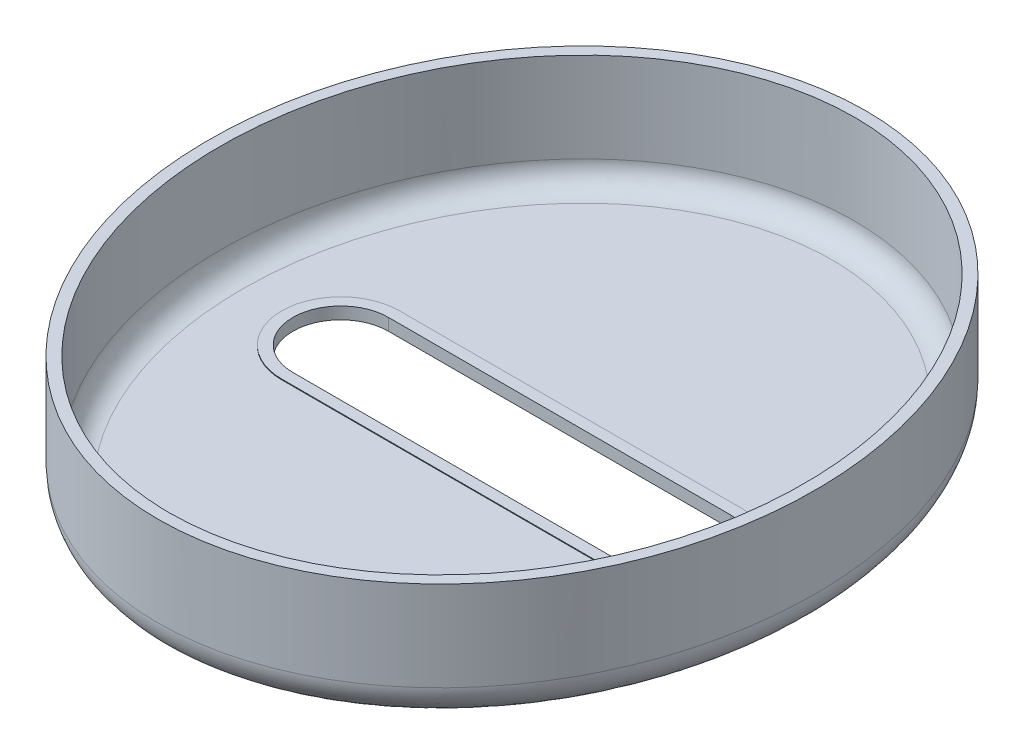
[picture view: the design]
ISO-10303-21;
HEADER;
FILE_DESCRIPTION(('STEP AP214'),'2;1');
FILE_NAME('part.step','',(''),(''),'','','');
FILE_SCHEMA(('AUTOMOTIVE_DESIGN { 1 0 10303 214 1 1 1 1 }'));
ENDSEC;
DATA;
#1=APPLICATION_CONTEXT('core data for automotive mechanical design processes');
#2=APPLICATION_PROTOCOL_DEFINITION('international standard','automotive_design',2000,#1);
#3=PRODUCT_CONTEXT('',#1,'mechanical');
#4=PRODUCT('Part','Part','',(#3));
#5=PRODUCT_RELATED_PRODUCT_CATEGORY('part','',(#4));
#6=PRODUCT_DEFINITION_FORMATION('','',#4);
#7=PRODUCT_DEFINITION_CONTEXT('part definition',#1,'design');
#8=PRODUCT_DEFINITION('design','',#6,#7);
#9=PRODUCT_DEFINITION_SHAPE('','',#8);
#10=(LENGTH_UNIT() NAMED_UNIT(*) SI_UNIT(.MILLI.,.METRE.));
#11=(NAMED_UNIT(*) PLANE_ANGLE_UNIT() SI_UNIT($,.RADIAN.));
#12=(NAMED_UNIT(*) SI_UNIT($,.STERADIAN.) SOLID_ANGLE_UNIT());
#13=UNCERTAINTY_MEASURE_WITH_UNIT(LENGTH_MEASURE(1.E-05),#10,'distance_accuracy_value','');
#14=(GEOMETRIC_REPRESENTATION_CONTEXT(3) GLOBAL_UNCERTAINTY_ASSIGNED_CONTEXT((#13)) GLOBAL_UNIT_ASSIGNED_CONTEXT((#10,
#11,#12)) REPRESENTATION_CONTEXT('',''));
#15=CARTESIAN_POINT('',(0.,0.,0.));
#16=DIRECTION('',(0.,0.,1.));
#17=DIRECTION('',(1.,0.,0.));
#18=AXIS2_PLACEMENT_3D('',#15,#16,#17);
#19=CARTESIAN_POINT('',(0.,11.,0.));
#20=DIRECTION('',(0.,1.,0.));
#21=DIRECTION('',(0.,0.,1.));
#22=AXIS2_PLACEMENT_3D('',#19,#20,#21);
#23=PLANE('',#22);
#24=CARTESIAN_POINT('',(0.,11.,0.));
#25=DIRECTION('',(0.,1.,0.));
#26=DIRECTION('',(0.,0.,-1.));
#27=AXIS2_PLACEMENT_3D('',#24,#25,#26);
#28=ELLIPSE('',#27,31.5,27.);
#29=CARTESIAN_POINT('',(0.,11.,-31.5));
#30=VERTEX_POINT('',#29);
#31=EDGE_CURVE('E205',#30,#30,#28,.T.);
#32=ORIENTED_EDGE('',*,*,#31,.T.);
#33=EDGE_LOOP('',(#32));
#34=FACE_BOUND('',#33,.T.);
#35=CARTESIAN_POINT('',(0.,11.,30.5));
#36=CARTESIAN_POINT('',(0.644223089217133,11.,30.499998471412));
#37=CARTESIAN_POINT('',(1.28846602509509,11.,30.4718512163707));
#38=CARTESIAN_POINT('',(2.57207033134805,11.,30.3596490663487));
#39=CARTESIAN_POINT('',(3.21143150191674,11.,30.2755918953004));
#40=CARTESIAN_POINT('',(4.48066001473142,11.,30.0526973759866));
#41=CARTESIAN_POINT('',(5.1105252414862,11.,29.9138480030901));
#42=CARTESIAN_POINT('',(6.35617141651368,11.,29.5832082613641));
#43=CARTESIAN_POINT('',(6.97195242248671,11.,29.3914181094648));
#44=CARTESIAN_POINT('',(8.18352809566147,11.,28.9579812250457));
#45=CARTESIAN_POINT('',(8.77937859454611,11.,28.7164902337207));
#46=CARTESIAN_POINT('',(9.94955938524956,11.,28.1861236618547));
#47=CARTESIAN_POINT('',(10.5238897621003,11.,27.8972482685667));
#48=CARTESIAN_POINT('',(11.6480725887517,11.,27.2752154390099));
#49=CARTESIAN_POINT('',(12.1979228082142,11.,26.9420539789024));
#50=CARTESIAN_POINT('',(13.2705915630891,11.,26.2347747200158));
#51=CARTESIAN_POINT('',(13.7934090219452,11.,25.8606552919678));
#52=CARTESIAN_POINT('',(14.8443375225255,11.,25.0482671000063));
#53=CARTESIAN_POINT('',(15.3704172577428,11.,24.6073714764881));
#54=CARTESIAN_POINT('',(16.3874753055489,11.,23.686844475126));
#55=CARTESIAN_POINT('',(16.8784523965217,11.,23.2072117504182));
#56=CARTESIAN_POINT('',(17.8239367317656,11.,22.2130919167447));
#57=CARTESIAN_POINT('',(18.2784346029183,11.,21.6985959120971));
#58=CARTESIAN_POINT('',(19.1498214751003,11.,20.6385796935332));
#59=CARTESIAN_POINT('',(19.566706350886,11.,20.0930560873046));
#60=CARTESIAN_POINT('',(20.190901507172,11.,19.2153396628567));
#61=CARTESIAN_POINT('',(20.4112281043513,11.,18.8923141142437));
#62=CARTESIAN_POINT('',(20.8392573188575,11.,18.2381042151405));
#63=CARTESIAN_POINT('',(21.0469625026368,11.,17.906921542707));
#64=CARTESIAN_POINT('',(21.6511362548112,11.,16.9018733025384));
#65=CARTESIAN_POINT('',(22.028665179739,11.,16.2165044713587));
#66=CARTESIAN_POINT('',(22.7327191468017,11.,14.8198249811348));
#67=CARTESIAN_POINT('',(23.0592226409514,11.,14.1085035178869));
#68=CARTESIAN_POINT('',(23.6608798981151,11.,12.664464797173));
#69=CARTESIAN_POINT('',(23.9360313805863,11.,11.9317465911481));
#70=CARTESIAN_POINT('',(24.4708720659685,11.,10.342021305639));
#71=CARTESIAN_POINT('',(24.7226069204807,11.,9.48233066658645));
#72=CARTESIAN_POINT('',(25.1587049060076,11.,7.74604003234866));
#73=CARTESIAN_POINT('',(25.3430623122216,11.,6.86943860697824));
#74=CARTESIAN_POINT('',(25.6445168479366,11.,5.10430928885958));
#75=CARTESIAN_POINT('',(25.7615871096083,11.,4.2157767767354));
#76=CARTESIAN_POINT('',(25.8866834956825,11.,2.87848787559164));
#77=CARTESIAN_POINT('',(25.9199644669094,11.,2.43195733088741));
#78=CARTESIAN_POINT('',(25.969713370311,11.,1.53785125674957));
#79=CARTESIAN_POINT('',(25.9861771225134,11.,1.09027549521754));
#80=CARTESIAN_POINT('',(26.0119135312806,11.,-0.341520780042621));
#81=CARTESIAN_POINT('',(25.9889619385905,11.,-1.32650344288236));
#82=CARTESIAN_POINT('',(25.8617095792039,11.,-3.29122285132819));
#83=CARTESIAN_POINT('',(25.7574073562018,11.,-4.27095950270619));
#84=CARTESIAN_POINT('',(25.5398768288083,11.,-5.7317745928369));
#85=CARTESIAN_POINT('',(25.4571177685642,11.,-6.21754243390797));
#86=CARTESIAN_POINT('',(25.271228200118,11.,-7.18503290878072));
#87=CARTESIAN_POINT('',(25.1681028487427,11.,-7.66675653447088));
#88=CARTESIAN_POINT('',(24.8282111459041,11.,-9.10429602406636));
#89=CARTESIAN_POINT('',(24.5608402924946,11.,-10.0530796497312));
#90=CARTESIAN_POINT('',(23.9420389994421,11.,-11.9313774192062));
#91=CARTESIAN_POINT('',(23.5899391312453,11.,-12.8606705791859));
#92=CARTESIAN_POINT('',(22.8029566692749,11.,-14.6837695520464));
#93=CARTESIAN_POINT('',(22.3680664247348,11.,-15.5775720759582));
#94=CARTESIAN_POINT('',(21.4167276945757,11.,-17.3192728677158));
#95=CARTESIAN_POINT('',(20.9003843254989,11.,-18.1672284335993));
#96=CARTESIAN_POINT('',(19.7870291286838,11.,-19.8083201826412));
#97=CARTESIAN_POINT('',(19.1900447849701,11.,-20.6014749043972));
#98=CARTESIAN_POINT('',(18.0791028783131,11.,-21.9292565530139));
#99=CARTESIAN_POINT('',(17.5824664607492,11.,-22.4784471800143));
#100=CARTESIAN_POINT('',(16.54696833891,11.,-23.5354446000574));
#101=CARTESIAN_POINT('',(16.0081136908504,11.,-24.0432582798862));
#102=CARTESIAN_POINT('',(14.890326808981,11.,-25.0123268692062));
#103=CARTESIAN_POINT('',(14.3114091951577,11.,-25.4735986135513));
#104=CARTESIAN_POINT('',(13.1159448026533,11.,-26.3446623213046));
#105=CARTESIAN_POINT('',(12.4993967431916,11.,-26.7544525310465));
#106=CARTESIAN_POINT('',(11.2280382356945,11.,-27.519856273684));
#107=CARTESIAN_POINT('',(10.5730069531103,11.,-27.8751039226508));
#108=CARTESIAN_POINT('',(9.23269544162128,11.,-28.5232263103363));
#109=CARTESIAN_POINT('',(8.54741484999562,11.,-28.8161003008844));
#110=CARTESIAN_POINT('',(7.15227044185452,11.,-29.3348060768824));
#111=CARTESIAN_POINT('',(6.44241915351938,11.,-29.5606714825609));
#112=CARTESIAN_POINT('',(5.00401481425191,11.,-29.9417582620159));
#113=CARTESIAN_POINT('',(4.27546419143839,11.,-30.0969887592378));
#114=CARTESIAN_POINT('',(2.88999504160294,11.,-30.3206349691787));
#115=CARTESIAN_POINT('',(2.23433463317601,11.,-30.3969060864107));
#116=CARTESIAN_POINT('',(0.918847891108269,11.,-30.4907361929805));
#117=CARTESIAN_POINT('',(0.259021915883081,11.,-30.5083001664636));
#118=CARTESIAN_POINT('',(-1.05934969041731,11.,-30.4844676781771));
#119=CARTESIAN_POINT('',(-1.717895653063,11.,-30.4430893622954));
#120=CARTESIAN_POINT('',(-3.02870017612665,11.,-30.3020075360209));
#121=CARTESIAN_POINT('',(-3.68095880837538,11.,-30.2023046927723));
#122=CARTESIAN_POINT('',(-4.94004583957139,11.,-29.9527667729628));
#123=CARTESIAN_POINT('',(-5.54745628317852,11.,-29.8058521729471));
#124=CARTESIAN_POINT('',(-6.7481607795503,11.,-29.4627882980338));
#125=CARTESIAN_POINT('',(-7.34145552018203,11.,-29.2666414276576));
#126=CARTESIAN_POINT('',(-8.51039797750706,11.,-28.8273863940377));
#127=CARTESIAN_POINT('',(-9.08604481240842,11.,-28.5842758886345));
#128=CARTESIAN_POINT('',(-10.2165331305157,11.,-28.053749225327));
#129=CARTESIAN_POINT('',(-10.7713736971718,11.,-27.7663311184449));
#130=CARTESIAN_POINT('',(-11.8839652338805,11.,-27.1351011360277));
#131=CARTESIAN_POINT('',(-12.4405451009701,11.,-26.7892262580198));
#132=CARTESIAN_POINT('',(-13.5252496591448,11.,-26.0554770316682));
#133=CARTESIAN_POINT('',(-14.0533737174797,11.,-25.6676017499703));
#134=CARTESIAN_POINT('',(-15.0792025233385,11.,-24.8533413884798));
#135=CARTESIAN_POINT('',(-15.5769002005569,11.,-24.4269474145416));
#136=CARTESIAN_POINT('',(-16.5401544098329,11.,-23.5392445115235));
#137=CARTESIAN_POINT('',(-17.0057070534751,11.,-23.0779313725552));
#138=CARTESIAN_POINT('',(-17.9570683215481,11.,-22.0668072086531));
#139=CARTESIAN_POINT('',(-18.4386430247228,11.,-21.5130098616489));
#140=CARTESIAN_POINT('',(-19.3586029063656,11.,-20.3706629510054));
#141=CARTESIAN_POINT('',(-19.7969851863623,11.,-19.7821110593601));
#142=CARTESIAN_POINT('',(-20.6298248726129,11.,-18.574440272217));
#143=CARTESIAN_POINT('',(-21.0242665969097,11.,-17.9553105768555));
#144=CARTESIAN_POINT('',(-21.7685015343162,11.,-16.6907670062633));
#145=CARTESIAN_POINT('',(-22.1182908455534,11.,-16.0453508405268));
#146=CARTESIAN_POINT('',(-22.8211831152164,11.,-14.6351444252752));
#147=CARTESIAN_POINT('',(-23.1671565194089,11.,-13.8667941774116));
#148=CARTESIAN_POINT('',(-23.7995656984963,11.,-12.3059750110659));
#149=CARTESIAN_POINT('',(-24.0859964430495,11.,-11.5135040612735));
#150=CARTESIAN_POINT('',(-24.5993301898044,11.,-9.90916573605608));
#151=CARTESIAN_POINT('',(-24.8262080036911,11.,-9.09729031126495));
#152=CARTESIAN_POINT('',(-25.2202914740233,11.,-7.45920121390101));
#153=CARTESIAN_POINT('',(-25.38749469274,11.,-6.63298695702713));
#154=CARTESIAN_POINT('',(-25.679695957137,11.,-4.86527590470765));
#155=CARTESIAN_POINT('',(-25.7966573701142,11.,-3.92244166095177));
#156=CARTESIAN_POINT('',(-25.9549412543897,11.,-2.03043896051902));
#157=CARTESIAN_POINT('',(-25.9962574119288,11.,-1.08126998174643));
#158=CARTESIAN_POINT('',(-26.0032573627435,11.,0.817856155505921));
#159=CARTESIAN_POINT('',(-25.9689100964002,11.,1.76781347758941));
#160=CARTESIAN_POINT('',(-25.860632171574,11.,3.18813072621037));
#161=CARTESIAN_POINT('',(-25.8150787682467,11.,3.66080802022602));
#162=CARTESIAN_POINT('',(-25.7050268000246,11.,4.60412450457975));
#163=CARTESIAN_POINT('',(-25.6405213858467,11.,5.07476289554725));
#164=CARTESIAN_POINT('',(-25.4104715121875,11.,6.53355258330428));
#165=CARTESIAN_POINT('',(-25.2122129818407,11.,7.51674329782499));
#166=CARTESIAN_POINT('',(-24.7312433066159,11.,9.46224155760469));
#167=CARTESIAN_POINT('',(-24.4485381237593,11.,10.4245505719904));
#168=CARTESIAN_POINT('',(-23.9611661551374,11.,11.8463902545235));
#169=CARTESIAN_POINT('',(-23.7880745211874,11.,12.3169167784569));
#170=CARTESIAN_POINT('',(-23.4208427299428,11.,13.2495371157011));
#171=CARTESIAN_POINT('',(-23.2267079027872,11.,13.7116330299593));
#172=CARTESIAN_POINT('',(-22.6126923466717,11.,15.0838170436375));
#173=CARTESIAN_POINT('',(-22.1611280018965,11.,15.9800139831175));
#174=CARTESIAN_POINT('',(-21.199602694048,11.,17.6806588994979));
#175=CARTESIAN_POINT('',(-20.6937843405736,11.,18.4874550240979));
#176=CARTESIAN_POINT('',(-19.6079406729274,11.,20.0497735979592));
#177=CARTESIAN_POINT('',(-19.0279107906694,11.,20.8052928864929));
#178=CARTESIAN_POINT('',(-17.7968313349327,11.,22.2539731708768));
#179=CARTESIAN_POINT('',(-17.1459049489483,11.,22.9472386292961));
#180=CARTESIAN_POINT('',(-15.7756219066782,11.,24.2623346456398));
#181=CARTESIAN_POINT('',(-15.0562940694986,11.,24.8841950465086));
#182=CARTESIAN_POINT('',(-13.7674275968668,11.,25.8809000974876));
#183=CARTESIAN_POINT('',(-13.2132808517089,11.,26.2757757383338));
#184=CARTESIAN_POINT('',(-12.0748825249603,11.,27.019418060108));
#185=CARTESIAN_POINT('',(-11.4906362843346,11.,27.3681928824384));
#186=CARTESIAN_POINT('',(-10.29555248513,11.,28.0154681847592));
#187=CARTESIAN_POINT('',(-9.68473840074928,11.,28.3140119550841));
#188=CARTESIAN_POINT('',(-8.43968412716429,11.,28.857535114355));
#189=CARTESIAN_POINT('',(-7.80544507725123,11.,29.1025171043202));
#190=CARTESIAN_POINT('',(-6.58580222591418,11.,29.5128105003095));
#191=CARTESIAN_POINT('',(-6.00230381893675,11.,29.6837998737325));
#192=CARTESIAN_POINT('',(-4.82348424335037,11.,29.9783949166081));
#193=CARTESIAN_POINT('',(-4.22816414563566,11.,30.1020048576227));
#194=CARTESIAN_POINT('',(-3.02944012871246,11.,30.3003877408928));
#195=CARTESIAN_POINT('',(-2.42603636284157,11.,30.3751616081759));
#196=CARTESIAN_POINT('',(-1.21509444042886,11.,30.4749699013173));
#197=CARTESIAN_POINT('',(-0.607556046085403,11.,30.5000014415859));
#198=CARTESIAN_POINT('',(0.,11.,30.5));
#199=B_SPLINE_CURVE_WITH_KNOTS('',3,(#35,#36,#37,#38,#39,#40,#41,#42,#43,#44,#45,#46,#47,#48,
#49,#50,#51,#52,#53,#54,#55,#56,#57,#58,#59,#60,#61,#62,#63,#64,#65,#66,#67,#68,#69,#70,#71,#72,
#73,#74,#75,#76,#77,#78,#79,#80,#81,#82,#83,#84,#85,#86,#87,#88,#89,#90,#91,#92,#93,#94,#95,#96,
#97,#98,#99,#100,#101,#102,#103,#104,#105,#106,#107,#108,#109,#110,#111,#112,#113,#114,#115,
#116,#117,#118,#119,#120,#121,#122,#123,#124,#125,#126,#127,#128,#129,#130,#131,#132,#133,#134,
#135,#136,#137,#138,#139,#140,#141,#142,#143,#144,#145,#146,#147,#148,#149,#150,#151,#152,#153,
#154,#155,#156,#157,#158,#159,#160,#161,#162,#163,#164,#165,#166,#167,#168,#169,#170,#171,#172,
#173,#174,#175,#176,#177,#178,#179,#180,#181,#182,#183,#184,#185,#186,#187,#188,#189,#190,#191,
#192,#193,#194,#195,#196,#197,#198),.UNSPECIFIED.,.T.,.F.,(4,2,2,2,2,2,2,2,2,2,2,2,2,2,2,2,2,2,
2,2,2,2,2,2,2,2,2,2,2,2,2,2,2,2,2,2,2,2,2,2,2,2,2,2,2,2,2,2,2,2,2,2,2,2,2,2,2,2,2,2,2,2,2,2,2,2,
2,2,2,2,2,2,2,2,2,2,2,2,2,2,2,4),(0.,1.93209281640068,3.86426429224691,5.79686003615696,
7.72944786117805,9.65606955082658,11.5826836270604,13.5094728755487,15.4363387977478,
17.4934609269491,19.55065461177,21.6083751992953,23.6663211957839,24.8390915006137,
26.011622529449,28.3566734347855,30.7027119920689,33.0488547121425,35.7333925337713,
38.4181583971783,41.1039955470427,42.4470291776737,43.7903965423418,46.7425554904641,
49.6947672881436,51.1726824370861,52.6502238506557,55.6034954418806,58.580914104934,
61.5586080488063,64.5324902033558,67.5053613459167,69.7245436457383,71.9433558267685,
74.1613625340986,76.3794447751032,78.6118111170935,80.8442042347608,83.0754753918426,
85.3064582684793,87.2841534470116,89.2616807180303,91.238599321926,93.2154953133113,
95.0881565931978,96.960726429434,98.8333896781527,100.706135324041,102.66997115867,
104.63385064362,106.598184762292,108.562756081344,110.762229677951,112.96185077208,
115.162254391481,117.36285015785,119.888214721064,122.413792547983,124.94043687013,
127.467184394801,130.314224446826,133.161502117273,136.009948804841,137.434220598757,
138.859007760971,141.864027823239,144.868835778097,146.372443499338,147.875671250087,
150.881455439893,153.734236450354,156.587193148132,159.435269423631,162.28215101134,
164.321466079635,166.360420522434,168.397608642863,170.434697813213,172.256915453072,
174.078968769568,175.900987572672,177.723112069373),.UNSPECIFIED.);
#200=CARTESIAN_POINT('',(0.,11.,30.5));
#201=VERTEX_POINT('',#200);
#202=EDGE_CURVE('E139',#201,#201,#199,.T.);
#203=ORIENTED_EDGE('',*,*,#202,.F.);
#204=EDGE_LOOP('',(#203));
#205=FACE_BOUND('',#204,.T.);
#206=ADVANCED_FACE('F50',(#34,#205),#23,.T.);
#207=CARTESIAN_POINT('',(0.,0.,0.));
#208=DIRECTION('',(0.,1.,0.));
#209=DIRECTION('',(0.,0.,1.));
#210=AXIS2_PLACEMENT_3D('',#207,#208,#209);
#211=PLANE('',#210);
#212=CARTESIAN_POINT('',(3.32786790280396,0.,-28.2237790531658));
#213=CARTESIAN_POINT('',(3.82146034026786,0.,-31.1828948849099));
#214=CARTESIAN_POINT('',(3.82146034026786,3.,-31.1828948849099));
#215=CARTESIAN_POINT('',(2.73134909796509,0.,-28.3232849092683));
#216=CARTESIAN_POINT('',(3.13719519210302,0.,-31.297038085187));
#217=CARTESIAN_POINT('',(3.13719519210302,3.,-31.297038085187));
#218=CARTESIAN_POINT('',(2.13043339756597,0.,-28.3962141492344));
#219=CARTESIAN_POINT('',(2.44729713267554,0.,-31.3807861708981));
#220=CARTESIAN_POINT('',(2.44729713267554,3.,-31.3807861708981));
#221=CARTESIAN_POINT('',(0.92450201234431,0.,-28.487839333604));
#222=CARTESIAN_POINT('',(1.0622304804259,0.,-31.4860213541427));
#223=CARTESIAN_POINT('',(1.0622304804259,3.,-31.4860213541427));
#224=CARTESIAN_POINT('',(0.319486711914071,0.,-28.506540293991));
#225=CARTESIAN_POINT('',(0.367062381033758,0.,-31.5075142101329));
#226=CARTESIAN_POINT('',(0.367062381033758,3.,-31.5075142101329));
#227=CARTESIAN_POINT('',(-0.889564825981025,0.,-28.4894260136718));
#228=CARTESIAN_POINT('',(-1.02204315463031,0.,-31.4878513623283));
#229=CARTESIAN_POINT('',(-1.02204315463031,3.,-31.4878513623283));
#230=CARTESIAN_POINT('',(-1.49360131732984,0.,-28.4536284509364));
#231=CARTESIAN_POINT('',(-1.7159809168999,0.,-31.4467159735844));
#232=CARTESIAN_POINT('',(-1.7159809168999,3.,-31.4467159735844));
#233=CARTESIAN_POINT('',(-2.69603399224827,0.,-28.3281035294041));
#234=CARTESIAN_POINT('',(-3.09661690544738,0.,-31.30258818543));
#235=CARTESIAN_POINT('',(-3.09661690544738,3.,-31.30258818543));
#236=CARTESIAN_POINT('',(-3.29443025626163,0.,-28.2383769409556));
#237=CARTESIAN_POINT('',(-3.78331523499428,0.,-31.1995966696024));
#238=CARTESIAN_POINT('',(-3.78331523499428,3.,-31.1995966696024));
#239=CARTESIAN_POINT('',(-4.44531250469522,0.,-28.0133215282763));
#240=CARTESIAN_POINT('',(-5.10273207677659,0.,-30.9415850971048));
#241=CARTESIAN_POINT('',(-5.10273207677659,3.,-30.9415850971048));
#242=CARTESIAN_POINT('',(-4.99840002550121,0.,-27.8810493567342));
#243=CARTESIAN_POINT('',(-5.73621852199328,0.,-30.7900546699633));
#244=CARTESIAN_POINT('',(-5.73621852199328,3.,-30.7900546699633));
#245=CARTESIAN_POINT('',(-6.09187018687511,0.,-27.5717608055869));
#246=CARTESIAN_POINT('',(-6.98708067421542,0.,-30.4362480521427));
#247=CARTESIAN_POINT('',(-6.98708067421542,3.,-30.4362480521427));
#248=CARTESIAN_POINT('',(-6.63225352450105,0.,-27.3947468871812));
#249=CARTESIAN_POINT('',(-7.60445726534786,0.,-30.2339746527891));
#250=CARTESIAN_POINT('',(-7.60445726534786,3.,-30.2339746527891));
#251=CARTESIAN_POINT('',(-7.69714435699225,0.,-26.998099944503));
#252=CARTESIAN_POINT('',(-8.81924785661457,0.,-29.781494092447));
#253=CARTESIAN_POINT('',(-8.81924785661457,3.,-29.781494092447));
#254=CARTESIAN_POINT('',(-8.22165101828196,0.,-26.7784646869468));
#255=CARTESIAN_POINT('',(-9.4166608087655,0.,-29.5312844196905));
#256=CARTESIAN_POINT('',(-9.4166608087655,3.,-29.5312844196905));
#257=CARTESIAN_POINT('',(-9.25197105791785,0.,-26.2990468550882));
#258=CARTESIAN_POINT('',(-10.5882214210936,0.,-28.9861464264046));
#259=CARTESIAN_POINT('',(-10.5882214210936,3.,-28.9861464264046));
#260=CARTESIAN_POINT('',(-9.75778354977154,0.,-26.0392623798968));
#261=CARTESIAN_POINT('',(-11.1623679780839,0.,-28.6912159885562));
#262=CARTESIAN_POINT('',(-11.1623679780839,3.,-28.6912159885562));
#263=CARTESIAN_POINT('',(-10.7743096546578,0.,-25.4676185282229));
#264=CARTESIAN_POINT('',(-12.3141540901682,0.,-28.0435090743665));
#265=CARTESIAN_POINT('',(-12.3141540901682,3.,-28.0435090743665));
#266=CARTESIAN_POINT('',(-11.2838883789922,0.,-25.153742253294));
#267=CARTESIAN_POINT('',(-12.890396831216,0.,-27.6885096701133));
#268=CARTESIAN_POINT('',(-12.890396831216,3.,-27.6885096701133));
#269=CARTESIAN_POINT('',(-12.2773888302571,0.,-24.4877777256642));
#270=CARTESIAN_POINT('',(-14.0116913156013,0.,-26.9368825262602));
#271=CARTESIAN_POINT('',(-14.0116913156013,3.,-26.9368825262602));
#272=CARTESIAN_POINT('',(-12.7613099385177,0.,-24.1356885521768));
#273=CARTESIAN_POINT('',(-14.556742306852,0.,-26.5402537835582));
#274=CARTESIAN_POINT('',(-14.556742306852,3.,-26.5402537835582));
#275=CARTESIAN_POINT('',(-13.701734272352,0.,-23.3965640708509));
#276=CARTESIAN_POINT('',(-15.6139206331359,0.,-25.7093671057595));
#277=CARTESIAN_POINT('',(-15.6139206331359,3.,-25.7093671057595));
#278=CARTESIAN_POINT('',(-14.1582341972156,0.,-23.0095245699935));
#279=CARTESIAN_POINT('',(-16.1260440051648,0.,-25.2751046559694));
#280=CARTESIAN_POINT('',(-16.1260440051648,3.,-25.2751046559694));
#281=CARTESIAN_POINT('',(-15.0425010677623,0.,-22.2036609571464));
#282=CARTESIAN_POINT('',(-17.1162016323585,0.,-24.3727391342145));
#283=CARTESIAN_POINT('',(-17.1162016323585,3.,-24.3727391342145));
#284=CARTESIAN_POINT('',(-15.4702572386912,0.,-21.7848250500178));
#285=CARTESIAN_POINT('',(-17.5942231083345,0.,-23.9046235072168));
#286=CARTESIAN_POINT('',(-17.5942231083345,3.,-23.9046235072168));
#287=CARTESIAN_POINT('',(-16.3490233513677,0.,-20.86279771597));
#288=CARTESIAN_POINT('',(-18.5745076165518,0.,-22.8760808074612));
#289=CARTESIAN_POINT('',(-18.5745076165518,3.,-22.8760808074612));
#290=CARTESIAN_POINT('',(-16.7959278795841,0.,-20.3556907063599));
#291=CARTESIAN_POINT('',(-19.0719580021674,0.,-22.3115311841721));
#292=CARTESIAN_POINT('',(-19.0719580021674,3.,-22.3115311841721));
#293=CARTESIAN_POINT('',(-17.6506078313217,0.,-19.3092813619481));
#294=CARTESIAN_POINT('',(-20.0215515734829,0.,-21.1489163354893));
#295=CARTESIAN_POINT('',(-20.0215515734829,3.,-21.1489163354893));
#296=CARTESIAN_POINT('',(-18.0583685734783,0.,-18.7699670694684));
#297=CARTESIAN_POINT('',(-20.4736777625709,0.,-20.5508386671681));
#298=CARTESIAN_POINT('',(-20.4736777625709,3.,-20.5508386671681));
#299=CARTESIAN_POINT('',(-18.8339916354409,0.,-17.6631848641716));
#300=CARTESIAN_POINT('',(-21.3322577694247,0.,-19.3256804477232));
#301=CARTESIAN_POINT('',(-21.3322577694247,3.,-19.3256804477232));
#302=CARTESIAN_POINT('',(-19.201842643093,0.,-17.095709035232));
#303=CARTESIAN_POINT('',(-21.7386986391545,0.,-18.6985917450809));
#304=CARTESIAN_POINT('',(-21.7386986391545,3.,-18.6985917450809));
#305=CARTESIAN_POINT('',(-19.8970506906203,0.,-15.9365636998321));
#306=CARTESIAN_POINT('',(-22.5057024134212,0.,-17.419738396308));
#307=CARTESIAN_POINT('',(-22.5057024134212,3.,-17.419738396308));
#308=CARTESIAN_POINT('',(-20.2244091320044,0.,-15.3448950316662));
#309=CARTESIAN_POINT('',(-22.8662669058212,0.,-16.7679746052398));
#310=CARTESIAN_POINT('',(-22.8662669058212,3.,-16.7679746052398));
#311=CARTESIAN_POINT('',(-20.8869781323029,0.,-14.0455948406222));
#312=CARTESIAN_POINT('',(-23.5951070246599,0.,-15.3387179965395));
#313=CARTESIAN_POINT('',(-23.5951070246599,3.,-15.3387179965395));
#314=CARTESIAN_POINT('',(-21.2152491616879,0.,-13.3344175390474));
#315=CARTESIAN_POINT('',(-23.9555910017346,0.,-14.5576373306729));
#316=CARTESIAN_POINT('',(-23.9555910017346,3.,-14.5576373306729));
#317=CARTESIAN_POINT('',(-21.8171364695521,0.,-11.8890678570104));
#318=CARTESIAN_POINT('',(-24.6157385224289,0.,-12.972382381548));
#319=CARTESIAN_POINT('',(-24.6157385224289,3.,-12.972382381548));
#320=CARTESIAN_POINT('',(-22.0907316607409,0.,-11.1548867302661));
#321=CARTESIAN_POINT('',(-24.9153786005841,0.,-12.1681993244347));
#322=CARTESIAN_POINT('',(-24.9153786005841,3.,-12.1681993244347));
#323=CARTESIAN_POINT('',(-22.5832120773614,0.,-9.66813085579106));
#324=CARTESIAN_POINT('',(-25.4542238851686,0.,-10.5414744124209));
#325=CARTESIAN_POINT('',(-25.4542238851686,3.,-10.5414744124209));
#326=CARTESIAN_POINT('',(-22.8020803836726,0.,-8.91555049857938));
#327=CARTESIAN_POINT('',(-25.6934104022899,0.,-9.71892696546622));
#328=CARTESIAN_POINT('',(-25.6934104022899,3.,-9.71892696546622));
#329=CARTESIAN_POINT('',(-23.1850310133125,0.,-7.39682306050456));
#330=CARTESIAN_POINT('',(-26.1116081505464,0.,-8.06040137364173));
#331=CARTESIAN_POINT('',(-26.1116081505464,3.,-8.06040137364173));
#332=CARTESIAN_POINT('',(-23.3491164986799,0.,-6.63067676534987));
#333=CARTESIAN_POINT('',(-26.2906228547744,0.,-7.22442400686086));
#334=CARTESIAN_POINT('',(-26.2906228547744,3.,-7.22442400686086));
#335=CARTESIAN_POINT('',(-23.7965307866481,0.,-4.10810926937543));
#336=CARTESIAN_POINT('',(-26.7785440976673,0.,-4.47358145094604));
#337=CARTESIAN_POINT('',(-26.7785440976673,3.,-4.47358145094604));
#338=CARTESIAN_POINT('',(-23.9664753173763,0.,-2.3303018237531));
#339=CARTESIAN_POINT('',(-26.9634950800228,0.,-2.53747281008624));
#340=CARTESIAN_POINT('',(-26.9634950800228,3.,-2.53747281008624));
#341=CARTESIAN_POINT('',(-24.024571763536,0.,1.23096797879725));
#342=CARTESIAN_POINT('',(-27.0267561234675,0.,1.34041530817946));
#343=CARTESIAN_POINT('',(-27.0267561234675,3.,1.34041530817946));
#344=CARTESIAN_POINT('',(-23.9125218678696,0.,3.01443347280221));
#345=CARTESIAN_POINT('',(-26.904846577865,0.,3.28219785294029));
#346=CARTESIAN_POINT('',(-26.904846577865,3.,3.28219785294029));
#347=CARTESIAN_POINT('',(-23.5251938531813,0.,5.71298229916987));
#348=CARTESIAN_POINT('',(-26.4826591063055,0.,6.22347841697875));
#349=CARTESIAN_POINT('',(-26.4826591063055,3.,6.22347841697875));
#350=CARTESIAN_POINT('',(-23.3509709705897,0.,6.64347954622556));
#351=CARTESIAN_POINT('',(-26.2926926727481,0.,7.23826737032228));
#352=CARTESIAN_POINT('',(-26.2926926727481,3.,7.23826737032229));
#353=CARTESIAN_POINT('',(-22.9226386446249,0.,8.48627192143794));
#354=CARTESIAN_POINT('',(-25.8251309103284,0.,9.24985190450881));
#355=CARTESIAN_POINT('',(-25.8251309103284,3.,9.24985190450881));
#356=CARTESIAN_POINT('',(-22.6685206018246,0.,9.39856507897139));
#357=CARTESIAN_POINT('',(-25.5475261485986,0.,10.2466455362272));
#358=CARTESIAN_POINT('',(-25.5475261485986,3.,10.2466455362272));
#359=CARTESIAN_POINT('',(-22.0805876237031,0.,11.1960957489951));
#360=CARTESIAN_POINT('',(-24.9043125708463,0.,12.213186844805));
#361=CARTESIAN_POINT('',(-24.9043125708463,3.,12.213186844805));
#362=CARTESIAN_POINT('',(-21.7468523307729,0.,12.0813593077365));
#363=CARTESIAN_POINT('',(-24.5387916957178,0.,13.1829604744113));
#364=CARTESIAN_POINT('',(-24.5387916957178,3.,13.1829604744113));
#365=CARTESIAN_POINT('',(-20.9994051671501,0.,13.817919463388));
#366=CARTESIAN_POINT('',(-23.7186469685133,0.,15.088423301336));
#367=CARTESIAN_POINT('',(-23.7186469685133,3.,15.088423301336));
#368=CARTESIAN_POINT('',(-20.5856735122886,0.,14.6692075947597));
#369=CARTESIAN_POINT('',(-23.2640010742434,0.,16.0241039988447));
#370=CARTESIAN_POINT('',(-23.2640010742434,3.,16.0241039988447));
#371=CARTESIAN_POINT('',(-19.7704514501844,0.,16.1605539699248));
#372=CARTESIAN_POINT('',(-22.3661639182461,0.,17.6665802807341));
#373=CARTESIAN_POINT('',(-22.3661639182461,3.,17.6665802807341));
#374=CARTESIAN_POINT('',(-19.3833892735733,0.,16.8085283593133));
#375=CARTESIAN_POINT('',(-21.9392313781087,0.,18.3814127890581));
#376=CARTESIAN_POINT('',(-21.9392313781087,3.,18.3814127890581));
#377=CARTESIAN_POINT('',(-18.5591743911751,0.,18.0717388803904));
#378=CARTESIAN_POINT('',(-21.028309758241,0.,19.777512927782));
#379=CARTESIAN_POINT('',(-21.028309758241,3.,19.777512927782));
#380=CARTESIAN_POINT('',(-18.1220296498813,0.,18.686980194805));
#381=CARTESIAN_POINT('',(-20.5443297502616,0.,20.4587858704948));
#382=CARTESIAN_POINT('',(-20.5443297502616,3.,20.4587858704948));
#383=CARTESIAN_POINT('',(-17.1983499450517,0.,19.8794054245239));
#384=CARTESIAN_POINT('',(-19.5194254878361,0.,21.7818870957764));
#385=CARTESIAN_POINT('',(-19.5194254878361,3.,21.7818870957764));
#386=CARTESIAN_POINT('',(-16.7118156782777,0.,20.4565898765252));
#387=CARTESIAN_POINT('',(-18.9785020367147,0.,22.423715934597));
#388=CARTESIAN_POINT('',(-18.9785020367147,3.,22.423715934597));
#389=CARTESIAN_POINT('',(-15.9462153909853,0.,21.289158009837));
#390=CARTESIAN_POINT('',(-18.1252674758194,0.,23.3515821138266));
#391=CARTESIAN_POINT('',(-18.1252674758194,3.,23.3515821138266));
#392=CARTESIAN_POINT('',(-15.6850398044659,0.,21.5611542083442));
#393=CARTESIAN_POINT('',(-17.8338709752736,0.,23.6550672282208));
#394=CARTESIAN_POINT('',(-17.8338709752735,3.,23.6550672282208));
#395=CARTESIAN_POINT('',(-15.1508434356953,0.,22.0934678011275));
#396=CARTESIAN_POINT('',(-17.2371396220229,0.,24.2496955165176));
#397=CARTESIAN_POINT('',(-17.2371396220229,3.,24.2496955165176));
#398=CARTESIAN_POINT('',(-14.8778179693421,0.,22.3537804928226));
#399=CARTESIAN_POINT('',(-16.9317992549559,0.,24.5408337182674));
#400=CARTESIAN_POINT('',(-16.9317992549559,3.,24.5408337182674));
#401=CARTESIAN_POINT('',(-14.0368624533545,0.,23.1200580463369));
#402=CARTESIAN_POINT('',(-15.9901350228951,0.,25.3988779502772));
#403=CARTESIAN_POINT('',(-15.9901350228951,3.,25.3988779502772));
#404=CARTESIAN_POINT('',(-13.4511921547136,0.,23.6068409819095));
#405=CARTESIAN_POINT('',(-15.3327777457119,0.,25.9453734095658));
#406=CARTESIAN_POINT('',(-15.3327777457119,3.,25.9453734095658));
#407=CARTESIAN_POINT('',(-12.236253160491,0.,24.5223482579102));
#408=CARTESIAN_POINT('',(-13.9655222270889,0.,26.9756556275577));
#409=CARTESIAN_POINT('',(-13.9655222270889,3.,26.9756556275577));
#410=CARTESIAN_POINT('',(-11.6069913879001,0.,24.9510817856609));
#411=CARTESIAN_POINT('',(-13.2556323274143,0.,27.4594523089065));
#412=CARTESIAN_POINT('',(-13.2556323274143,3.,27.4594523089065));
#413=CARTESIAN_POINT('',(-10.3095790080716,0.,25.7433995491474));
#414=CARTESIAN_POINT('',(-11.7881825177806,0.,28.3556092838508));
#415=CARTESIAN_POINT('',(-11.7881825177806,3.,28.3556092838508));
#416=CARTESIAN_POINT('',(-9.64147433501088,0.,26.1070587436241));
#417=CARTESIAN_POINT('',(-11.0306788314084,0.,28.7680517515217));
#418=CARTESIAN_POINT('',(-11.0306788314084,3.,28.7680517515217));
#419=CARTESIAN_POINT('',(-8.27123936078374,0.,26.7631715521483));
#420=CARTESIAN_POINT('',(-9.47336569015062,0.,29.5137406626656));
#421=CARTESIAN_POINT('',(-9.47336569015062,3.,29.5137406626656));
#422=CARTESIAN_POINT('',(-7.56912000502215,0.,27.0556478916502));
#423=CARTESIAN_POINT('',(-8.67356983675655,0.,29.8470123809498));
#424=CARTESIAN_POINT('',(-8.67356983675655,3.,29.8470123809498));
#425=CARTESIAN_POINT('',(-6.30425870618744,0.,27.5044896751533));
#426=CARTESIAN_POINT('',(-7.22982696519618,0.,30.3593315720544));
#427=CARTESIAN_POINT('',(-7.22982696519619,3.,30.3593315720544));
#428=CARTESIAN_POINT('',(-5.74708937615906,0.,27.6766907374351));
#429=CARTESIAN_POINT('',(-6.59290668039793,0.,30.5562206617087));
#430=CARTESIAN_POINT('',(-6.59290668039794,3.,30.5562206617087));
#431=CARTESIAN_POINT('',(-4.62027441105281,0.,27.9735826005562));
#432=CARTESIAN_POINT('',(-5.30320841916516,0.,30.8960281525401));
#433=CARTESIAN_POINT('',(-5.30320841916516,3.,30.8960281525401));
#434=CARTESIAN_POINT('',(-4.05063112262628,0.,28.0982822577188));
#435=CARTESIAN_POINT('',(-4.65043342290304,0.,31.0389566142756));
#436=CARTESIAN_POINT('',(-4.65043342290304,3.,31.0389566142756));
#437=CARTESIAN_POINT('',(-2.90301959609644,0.,28.29844776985));
#438=CARTESIAN_POINT('',(-3.33420052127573,0.,31.2685325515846));
#439=CARTESIAN_POINT('',(-3.33420052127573,3.,31.2685325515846));
#440=CARTESIAN_POINT('',(-2.32505528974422,0.,28.373936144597));
#441=CARTESIAN_POINT('',(-2.67074764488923,0.,31.3552057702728));
#442=CARTESIAN_POINT('',(-2.67074764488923,3.,31.3552057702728));
#443=CARTESIAN_POINT('',(-1.16472832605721,0.,28.4747134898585));
#444=CARTESIAN_POINT('',(-1.33819768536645,0.,31.4709409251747));
#445=CARTESIAN_POINT('',(-1.33819768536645,3.,31.4709409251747));
#446=CARTESIAN_POINT('',(-0.582365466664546,0.,28.500000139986));
#447=CARTESIAN_POINT('',(-0.669100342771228,0.,31.5000001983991));
#448=CARTESIAN_POINT('',(-0.669100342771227,3.,31.5000001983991));
#449=CARTESIAN_POINT('',(0.587898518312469,0.,28.499999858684));
#450=CARTESIAN_POINT('',(0.675457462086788,0.,31.4999997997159));
#451=CARTESIAN_POINT('',(0.675457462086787,3.,31.4999997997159));
#452=CARTESIAN_POINT('',(1.17579969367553,0.,28.4742301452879));
#453=CARTESIAN_POINT('',(1.35091798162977,0.,31.4703853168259));
#454=CARTESIAN_POINT('',(1.35091798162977,3.,31.4703853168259));
#455=CARTESIAN_POINT('',(2.34710426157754,0.,28.3715291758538));
#456=CARTESIAN_POINT('',(2.69606347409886,0.,31.3524420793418));
#457=CARTESIAN_POINT('',(2.69606347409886,3.,31.3524420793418));
#458=CARTESIAN_POINT('',(2.93050765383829,0.,28.2945979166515));
#459=CARTESIAN_POINT('',(3.36574844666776,0.,31.264113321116));
#460=CARTESIAN_POINT('',(3.36574844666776,3.,31.264113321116));
#461=CARTESIAN_POINT('',(4.08859119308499,0.,28.0906614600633));
#462=CARTESIAN_POINT('',(4.69394889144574,0.,31.0302199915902));
#463=CARTESIAN_POINT('',(4.69394889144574,3.,31.0302199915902));
#464=CARTESIAN_POINT('',(4.66326964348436,0.,27.9636466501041));
#465=CARTESIAN_POINT('',(5.35246219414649,0.,30.8846444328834));
#466=CARTESIAN_POINT('',(5.35246219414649,3.,30.8846444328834));
#467=CARTESIAN_POINT('',(5.79974822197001,0.,27.6613010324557));
#468=CARTESIAN_POINT('',(6.65313012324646,0.,30.5386188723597));
#469=CARTESIAN_POINT('',(6.65313012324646,3.,30.5386188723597));
#470=CARTESIAN_POINT('',(6.36154826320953,0.,27.4859698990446));
#471=CARTESIAN_POINT('',(7.29528463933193,0.,30.3381685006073));
#472=CARTESIAN_POINT('',(7.29528463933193,3.,30.3381685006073));
#473=CARTESIAN_POINT('',(7.46676990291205,0.,27.0899514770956));
#474=CARTESIAN_POINT('',(8.55667163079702,0.,29.8861941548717));
#475=CARTESIAN_POINT('',(8.55667163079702,3.,29.8861941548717));
#476=CARTESIAN_POINT('',(8.01024668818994,0.,26.8694178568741));
#477=CARTESIAN_POINT('',(9.17597359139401,0.,29.6348432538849));
#478=CARTESIAN_POINT('',(9.17597359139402,3.,29.6348432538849));
#479=CARTESIAN_POINT('',(9.07763464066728,0.,26.3853103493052));
#480=CARTESIAN_POINT('',(10.3901961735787,0.,29.0841402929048));
#481=CARTESIAN_POINT('',(10.3901961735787,3.,29.0841402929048));
#482=CARTESIAN_POINT('',(9.60154593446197,0.,26.1217367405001));
#483=CARTESIAN_POINT('',(10.9851169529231,0.,28.7847885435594));
#484=CARTESIAN_POINT('',(10.9851169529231,3.,28.7847885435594));
#485=CARTESIAN_POINT('',(10.6271182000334,0.,25.554492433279));
#486=CARTESIAN_POINT('',(12.1475479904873,0.,28.141848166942));
#487=CARTESIAN_POINT('',(12.1475479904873,3.,28.141848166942));
#488=CARTESIAN_POINT('',(11.1287802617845,0.,25.250823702));
#489=CARTESIAN_POINT('',(12.7150595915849,0.,27.798261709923));
#490=CARTESIAN_POINT('',(12.7150595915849,3.,27.798261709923));
#491=CARTESIAN_POINT('',(12.1078621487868,0.,24.6063443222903));
#492=CARTESIAN_POINT('',(13.8205571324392,0.,27.070569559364));
#493=CARTESIAN_POINT('',(13.8205571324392,3.,27.070569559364));
#494=CARTESIAN_POINT('',(12.585272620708,0.,24.2655195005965));
#495=CARTESIAN_POINT('',(14.3585316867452,0.,26.6864484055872));
#496=CARTESIAN_POINT('',(14.3585316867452,3.,26.6864484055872));
#497=CARTESIAN_POINT('',(13.5482049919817,0.,23.5234809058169));
#498=CARTESIAN_POINT('',(15.4415642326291,0.,25.8518613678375));
#499=CARTESIAN_POINT('',(15.4415642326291,3.,25.8518613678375));
#500=CARTESIAN_POINT('',(14.0317244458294,0.,23.1196665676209));
#501=CARTESIAN_POINT('',(15.984213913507,0.,25.3985911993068));
#502=CARTESIAN_POINT('',(15.984213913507,3.,25.3985911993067));
#503=CARTESIAN_POINT('',(14.9669650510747,0.,22.2766477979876));
#504=CARTESIAN_POINT('',(17.0317578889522,0.,24.4543410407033));
#505=CARTESIAN_POINT('',(17.0317578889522,3.,24.4543410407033));
#506=CARTESIAN_POINT('',(15.4186746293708,0.,21.8374306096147));
#507=CARTESIAN_POINT('',(17.5366384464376,0.,23.9633474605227));
#508=CARTESIAN_POINT('',(17.5366384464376,3.,23.9633474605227));
#509=CARTESIAN_POINT('',(16.7239729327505,0.,20.4722717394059));
#510=CARTESIAN_POINT('',(18.9928546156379,0.,22.4403621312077));
#511=CARTESIAN_POINT('',(18.9928546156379,3.,22.4403621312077));
#512=CARTESIAN_POINT('',(17.5281926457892,0.,19.4984624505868));
#513=CARTESIAN_POINT('',(19.8862829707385,0.,21.3579601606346));
#514=CARTESIAN_POINT('',(19.8862829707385,3.,21.3579601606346));
#515=CARTESIAN_POINT('',(19.1079818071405,0.,17.2977565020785));
#516=CARTESIAN_POINT('',(21.6360228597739,0.,18.9205208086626));
#517=CARTESIAN_POINT('',(21.6360228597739,3.,18.9205208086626));
#518=CARTESIAN_POINT('',(19.8610461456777,0.,16.0548238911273));
#519=CARTESIAN_POINT('',(22.4665374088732,0.,17.5489640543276));
#520=CARTESIAN_POINT('',(22.4665374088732,3.,17.5489640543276));
#521=CARTESIAN_POINT('',(21.1801233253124,0.,13.4733214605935));
#522=CARTESIAN_POINT('',(23.9175950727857,0.,14.7091531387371));
#523=CARTESIAN_POINT('',(23.9175950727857,3.,14.7091531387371));
#524=CARTESIAN_POINT('',(21.7460253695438,0.,12.1346955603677));
#525=CARTESIAN_POINT('',(24.5380138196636,0.,13.2408423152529));
#526=CARTESIAN_POINT('',(24.5380138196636,3.,13.2408423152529));
#527=CARTESIAN_POINT('',(22.7627401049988,0.,9.18148031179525));
#528=CARTESIAN_POINT('',(25.6508428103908,0.,10.0084704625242));
#529=CARTESIAN_POINT('',(25.6508428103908,3.,10.0084704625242));
#530=CARTESIAN_POINT('',(23.1823682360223,0.,7.55615824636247));
#531=CARTESIAN_POINT('',(26.1087819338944,0.,8.23370794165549));
#532=CARTESIAN_POINT('',(26.1087819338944,3.,8.23370794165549));
#533=CARTESIAN_POINT('',(23.7721161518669,0.,4.25999473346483));
#534=CARTESIAN_POINT('',(26.7519155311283,0.,4.63916027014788));
#535=CARTESIAN_POINT('',(26.7519155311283,3.,4.63916027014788));
#536=CARTESIAN_POINT('',(23.9421075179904,0.,2.58913030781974));
#537=CARTESIAN_POINT('',(26.9369696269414,0.,2.81935243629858));
#538=CARTESIAN_POINT('',(26.9369696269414,3.,2.81935243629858));
#539=CARTESIAN_POINT('',(24.0127335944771,0.,-0.0102903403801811));
#540=CARTESIAN_POINT('',(27.013860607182,0.,-0.0112294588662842));
#541=CARTESIAN_POINT('',(27.013860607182,3.,-0.0112294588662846));
#542=CARTESIAN_POINT('',(23.9997225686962,0.,-0.9373304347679));
#543=CARTESIAN_POINT('',(26.9997004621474,0.,-1.0205999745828));
#544=CARTESIAN_POINT('',(26.9997004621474,3.,-1.0205999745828));
#545=CARTESIAN_POINT('',(23.8973913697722,0.,-2.78756822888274));
#546=CARTESIAN_POINT('',(26.8882598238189,0.,-3.03559922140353));
#547=CARTESIAN_POINT('',(26.8882598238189,3.,-3.03559922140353));
#548=CARTESIAN_POINT('',(23.8080569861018,0.,-3.71076518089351));
#549=CARTESIAN_POINT('',(26.7909638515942,0.,-4.04122722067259));
#550=CARTESIAN_POINT('',(26.7909638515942,3.,-4.04122722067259));
#551=CARTESIAN_POINT('',(23.5528290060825,0.,-5.54727258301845));
#552=CARTESIAN_POINT('',(26.5127940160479,0.,-6.04280925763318));
#553=CARTESIAN_POINT('',(26.5127940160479,3.,-6.04280925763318));
#554=CARTESIAN_POINT('',(23.3868720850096,0.,-6.46057421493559));
#555=CARTESIAN_POINT('',(26.3318510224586,0.,-7.03875459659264));
#556=CARTESIAN_POINT('',(26.3318510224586,3.,-7.03875459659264));
#557=CARTESIAN_POINT('',(22.9783156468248,0.,-8.26950818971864));
#558=CARTESIAN_POINT('',(25.8859321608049,0.,-9.01311693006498));
#559=CARTESIAN_POINT('',(25.8859321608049,3.,-9.01311693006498));
#560=CARTESIAN_POINT('',(22.7357498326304,0.,-9.16514811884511));
#561=CARTESIAN_POINT('',(25.6209932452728,0.,-9.99154143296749));
#562=CARTESIAN_POINT('',(25.6209932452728,3.,-9.9915414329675));
#563=CARTESIAN_POINT('',(22.1704958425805,0.,-10.9424754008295));
#564=CARTESIAN_POINT('',(25.0027377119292,0.,-11.9355224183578));
#565=CARTESIAN_POINT('',(25.0027377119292,3.,-11.9355224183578));
#566=CARTESIAN_POINT('',(21.8468981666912,0.,-11.8238744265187));
#567=CARTESIAN_POINT('',(24.6484175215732,0.,-12.9007918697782));
#568=CARTESIAN_POINT('',(24.6484175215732,3.,-12.9007918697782));
#569=CARTESIAN_POINT('',(21.121007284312,0.,-13.5538678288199));
#570=CARTESIAN_POINT('',(23.852187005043,0.,-14.7984242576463));
#571=CARTESIAN_POINT('',(23.8521870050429,3.,-14.7984242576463));
#572=CARTESIAN_POINT('',(20.7187058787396,0.,-14.4024587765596));
#573=CARTESIAN_POINT('',(23.4102675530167,0.,-15.7307837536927));
#574=CARTESIAN_POINT('',(23.4102675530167,3.,-15.7307837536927));
#575=CARTESIAN_POINT('',(19.8363503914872,0.,-16.0568107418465));
#576=CARTESIAN_POINT('',(22.4389181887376,0.,-17.5519930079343));
#577=CARTESIAN_POINT('',(22.4389181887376,3.,-17.5519930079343));
#578=CARTESIAN_POINT('',(19.3564040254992,0.,-16.8626290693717));
#579=CARTESIAN_POINT('',(21.9096094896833,0.,-18.4409008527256));
#580=CARTESIAN_POINT('',(21.9096094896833,3.,-18.4409008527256));
#581=CARTESIAN_POINT('',(18.3193044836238,0.,-18.422847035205));
#582=CARTESIAN_POINT('',(20.7629440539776,0.,-20.1659514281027));
#583=CARTESIAN_POINT('',(20.7629440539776,3.,-20.1659514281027));
#584=CARTESIAN_POINT('',(17.7621799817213,0.,-19.1772656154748));
#585=CARTESIAN_POINT('',(20.1456200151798,0.,-21.0021135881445));
#586=CARTESIAN_POINT('',(20.1456200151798,3.,-21.0021135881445));
#587=CARTESIAN_POINT('',(16.7320424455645,0.,-20.4301589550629));
#588=CARTESIAN_POINT('',(19.0008913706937,0.,-22.3943727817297));
#589=CARTESIAN_POINT('',(19.0008913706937,3.,-22.3943727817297));
#590=CARTESIAN_POINT('',(16.2764802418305,0.,-20.9430566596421));
#591=CARTESIAN_POINT('',(18.4937020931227,0.,-22.9654881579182));
#592=CARTESIAN_POINT('',(18.4937020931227,3.,-22.9654881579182));
#593=CARTESIAN_POINT('',(15.3261602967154,0.,-21.9310907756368));
#594=CARTESIAN_POINT('',(17.4333393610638,0.,-24.06793285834));
#595=CARTESIAN_POINT('',(17.4333393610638,3.,-24.06793285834));
#596=CARTESIAN_POINT('',(14.8314113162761,0.,-22.4062355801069));
#597=CARTESIAN_POINT('',(16.880176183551,0.,-24.5992710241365));
#598=CARTESIAN_POINT('',(16.880176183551,3.,-24.5992710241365));
#599=CARTESIAN_POINT('',(13.8044818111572,0.,-23.31391927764));
#600=CARTESIAN_POINT('',(15.7293282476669,0.,-25.6164831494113));
#601=CARTESIAN_POINT('',(15.7293282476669,3.,-25.6164831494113));
#602=CARTESIAN_POINT('',(13.2723134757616,0.,-23.7464719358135));
#603=CARTESIAN_POINT('',(15.1316579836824,0.,-26.1023717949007));
#604=CARTESIAN_POINT('',(15.1316579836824,3.,-26.1023717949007));
#605=CARTESIAN_POINT('',(12.1726512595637,0.,-24.5642353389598));
#606=CARTESIAN_POINT('',(13.8937160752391,0.,-27.022966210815));
#607=CARTESIAN_POINT('',(13.8937160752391,3.,-27.022966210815));
#608=CARTESIAN_POINT('',(11.6051561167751,0.,-24.9494443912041));
#609=CARTESIAN_POINT('',(13.2534429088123,0.,-27.4576701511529));
#610=CARTESIAN_POINT('',(13.2534429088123,3.,-27.4576701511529));
#611=CARTESIAN_POINT('',(10.4337247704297,0.,-25.670076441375));
#612=CARTESIAN_POINT('',(11.9287012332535,0.,-28.2726134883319));
#613=CARTESIAN_POINT('',(11.9287012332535,3.,-28.2726134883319));
#614=CARTESIAN_POINT('',(9.8295580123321,0.,-26.0051257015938));
#615=CARTESIAN_POINT('',(11.2439506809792,0.,-28.6524433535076));
#616=CARTESIAN_POINT('',(11.2439506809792,3.,-28.6524433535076));
#617=CARTESIAN_POINT('',(8.59242441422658,0.,-26.617200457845));
#618=CARTESIAN_POINT('',(9.83872532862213,0.,-29.3476806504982));
#619=CARTESIAN_POINT('',(9.83872532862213,3.,-29.3476806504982));
#620=CARTESIAN_POINT('',(7.95945718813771,0.,-26.8942251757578));
#621=CARTESIAN_POINT('',(9.11825004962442,0.,-29.6630872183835));
#622=CARTESIAN_POINT('',(9.11825004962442,3.,-29.6630872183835));
#623=CARTESIAN_POINT('',(6.67001602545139,0.,-27.3855637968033));
#624=CARTESIAN_POINT('',(7.6477216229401,0.,-30.2234275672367));
#625=CARTESIAN_POINT('',(7.6477216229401,3.,-30.2234275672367));
#626=CARTESIAN_POINT('',(6.01355664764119,0.,-27.5999158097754));
#627=CARTESIAN_POINT('',(6.89768676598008,0.,-30.4684041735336));
#628=CARTESIAN_POINT('',(6.89768676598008,3.,-30.4684041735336));
#629=CARTESIAN_POINT('',(4.68259149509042,0.,-27.9622844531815));
#630=CARTESIAN_POINT('',(5.374693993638,0.,-30.8830525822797));
#631=CARTESIAN_POINT('',(5.374693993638,3.,-30.8830525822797));
#632=CARTESIAN_POINT('',(4.00808839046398,0.,-28.1103108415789));
#633=CARTESIAN_POINT('',(4.60173946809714,0.,-31.0527354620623));
#634=CARTESIAN_POINT('',(4.60173946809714,3.,-31.0527354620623));
#635=CARTESIAN_POINT('',(3.32786790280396,0.,-28.2237790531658));
#636=CARTESIAN_POINT('',(3.82146034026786,0.,-31.1828948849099));
#637=CARTESIAN_POINT('',(3.82146034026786,3.,-31.1828948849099));
#638=(BOUNDED_SURFACE() B_SPLINE_SURFACE(3,2,((#212,#213,#214),(#215,#216,#217),(#218,#219,
#220),(#221,#222,#223),(#224,#225,#226),(#227,#228,#229),(#230,#231,#232),(#233,#234,#235),
(#236,#237,#238),(#239,#240,#241),(#242,#243,#244),(#245,#246,#247),(#248,#249,#250),(#251,#252,
#253),(#254,#255,#256),(#257,#258,#259),(#260,#261,#262),(#263,#264,#265),(#266,#267,#268),
(#269,#270,#271),(#272,#273,#274),(#275,#276,#277),(#278,#279,#280),(#281,#282,#283),(#284,#285,
#286),(#287,#288,#289),(#290,#291,#292),(#293,#294,#295),(#296,#297,#298),(#299,#300,#301),
(#302,#303,#304),(#305,#306,#307),(#308,#309,#310),(#311,#312,#313),(#314,#315,#316),(#317,#318,
#319),(#320,#321,#322),(#323,#324,#325),(#326,#327,#328),(#329,#330,#331),(#332,#333,#334),
(#335,#336,#337),(#338,#339,#340),(#341,#342,#343),(#344,#345,#346),(#347,#348,#349),(#350,#351,
#352),(#353,#354,#355),(#356,#357,#358),(#359,#360,#361),(#362,#363,#364),(#365,#366,#367),
(#368,#369,#370),(#371,#372,#373),(#374,#375,#376),(#377,#378,#379),(#380,#381,#382),(#383,#384,
#385),(#386,#387,#388),(#389,#390,#391),(#392,#393,#394),(#395,#396,#397),(#398,#399,#400),
(#401,#402,#403),(#404,#405,#406),(#407,#408,#409),(#410,#411,#412),(#413,#414,#415),(#416,#417,
#418),(#419,#420,#421),(#422,#423,#424),(#425,#426,#427),(#428,#429,#430),(#431,#432,#433),
(#434,#435,#436),(#437,#438,#439),(#440,#441,#442),(#443,#444,#445),(#446,#447,#448),(#449,#450,
#451),(#452,#453,#454),(#455,#456,#457),(#458,#459,#460),(#461,#462,#463),(#464,#465,#466),
(#467,#468,#469),(#470,#471,#472),(#473,#474,#475),(#476,#477,#478),(#479,#480,#481),(#482,#483,
#484),(#485,#486,#487),(#488,#489,#490),(#491,#492,#493),(#494,#495,#496),(#497,#498,#499),
(#500,#501,#502),(#503,#504,#505),(#506,#507,#508),(#509,#510,#511),(#512,#513,#514),(#515,#516,
#517),(#518,#519,#520),(#521,#522,#523),(#524,#525,#526),(#527,#528,#529),(#530,#531,#532),
(#533,#534,#535),(#536,#537,#538),(#539,#540,#541),(#542,#543,#544),(#545,#546,#547),(#548,#549,
#550),(#551,#552,#553),(#554,#555,#556),(#557,#558,#559),(#560,#561,#562),(#563,#564,#565),
(#566,#567,#568),(#569,#570,#571),(#572,#573,#574),(#575,#576,#577),(#578,#579,#580),(#581,#582,
#583),(#584,#585,#586),(#587,#588,#589),(#590,#591,#592),(#593,#594,#595),(#596,#597,#598),
(#599,#600,#601),(#602,#603,#604),(#605,#606,#607),(#608,#609,#610),(#611,#612,#613),(#614,#615,
#616),(#617,#618,#619),(#620,#621,#622),(#623,#624,#625),(#626,#627,#628),(#629,#630,#631),
(#632,#633,#634),(#635,#636,#637)),.UNSPECIFIED.,.T.,.F.,.F.) B_SPLINE_SURFACE_WITH_KNOTS((4,2,
2,2,2,2,2,2,2,2,2,2,2,2,2,2,2,2,2,2,2,2,2,2,2,2,2,2,2,2,2,2,2,2,2,2,2,2,2,2,2,2,2,2,2,2,2,2,2,2,
2,2,2,2,2,2,2,2,2,2,2,2,2,2,2,2,2,2,2,2,4),(3,3),(0.,1.81360808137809,3.62704840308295,
5.43990061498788,7.2527269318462,8.95686398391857,10.6609073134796,12.3650399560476,
14.069253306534,15.8628689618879,17.6565278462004,19.4504022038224,21.2449452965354,
23.2707135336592,25.2972386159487,27.324336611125,29.3513644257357,31.6988319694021,
34.047203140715,36.3962994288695,38.7452601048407,44.078740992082,49.4160399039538,
52.2530385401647,55.0903426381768,57.9248203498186,60.7599999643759,63.0221246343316,
65.2838900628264,67.545623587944,68.6765633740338,69.8079543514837,72.0890589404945,
74.3698020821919,76.6479008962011,78.9252714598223,80.6728623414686,82.420127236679,
84.1665919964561,85.9131374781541,87.6762768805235,89.4394163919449,91.2028944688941,
92.9663844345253,94.7239758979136,96.48155598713,98.2390498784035,99.9972165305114,
101.885160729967,103.773788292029,107.54930442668,111.89272141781,116.238705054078,
121.254568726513,126.27301176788,129.051728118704,131.830961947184,134.612496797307,
137.392809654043,140.205849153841,143.019181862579,145.828644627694,148.63706637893,
150.693121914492,152.74871907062,154.803649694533,156.858653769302,158.928279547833,
160.997933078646,163.066325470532,165.134413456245),(0.,1.),
.UNSPECIFIED.) GEOMETRIC_REPRESENTATION_ITEM() RATIONAL_B_SPLINE_SURFACE(((1.,0.707106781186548,
1.),(1.,0.707106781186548,1.),(1.,0.707106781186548,1.),(1.,0.707106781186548,1.),(1.,
0.707106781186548,1.),(1.,0.707106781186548,1.),(1.,0.707106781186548,1.),(1.,0.707106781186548,
1.),(1.,0.707106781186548,1.),(1.,0.707106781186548,1.),(1.,0.707106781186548,1.),(1.,
0.707106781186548,1.),(1.,0.707106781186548,1.),(1.,0.707106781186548,1.),(1.,0.707106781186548,
1.),(1.,0.707106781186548,1.),(1.,0.707106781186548,1.),(1.,0.707106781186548,1.),(1.,
0.707106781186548,1.),(1.,0.707106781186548,1.),(1.,0.707106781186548,1.),(1.,0.707106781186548,
1.),(1.,0.707106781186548,1.),(1.,0.707106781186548,1.),(1.,0.707106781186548,1.),(1.,
0.707106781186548,1.),(1.,0.707106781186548,1.),(1.,0.707106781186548,1.),(1.,0.707106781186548,
1.),(1.,0.707106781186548,1.),(1.,0.707106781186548,1.),(1.,0.707106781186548,1.),(1.,
0.707106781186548,1.),(1.,0.707106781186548,1.),(1.,0.707106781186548,1.),(1.,0.707106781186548,
1.),(1.,0.707106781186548,1.),(1.,0.707106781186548,1.),(1.,0.707106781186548,1.),(1.,
0.707106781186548,1.),(1.,0.707106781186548,1.),(1.,0.707106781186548,1.),(1.,0.707106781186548,
1.),(1.,0.707106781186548,1.),(1.,0.707106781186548,1.),(1.,0.707106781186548,1.),(1.,
0.707106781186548,1.),(1.,0.707106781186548,1.),(1.,0.707106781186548,1.),(1.,0.707106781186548,
1.),(1.,0.707106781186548,1.),(1.,0.707106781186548,1.),(1.,0.707106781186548,1.),(1.,
0.707106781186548,1.),(1.,0.707106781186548,1.),(1.,0.707106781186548,1.),(1.,0.707106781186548,
1.),(1.,0.707106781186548,1.),(1.,0.707106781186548,1.),(1.,0.707106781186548,1.),(1.,
0.707106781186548,1.),(1.,0.707106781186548,1.),(1.,0.707106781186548,1.),(1.,0.707106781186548,
1.),(1.,0.707106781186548,1.),(1.,0.707106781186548,1.),(1.,0.707106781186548,1.),(1.,
0.707106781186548,1.),(1.,0.707106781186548,1.),(1.,0.707106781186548,1.),(1.,0.707106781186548,
1.),(1.,0.707106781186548,1.),(1.,0.707106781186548,1.),(1.,0.707106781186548,1.),(1.,
0.707106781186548,1.),(1.,0.707106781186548,1.),(1.,0.707106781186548,1.),(1.,0.707106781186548,
1.),(1.,0.707106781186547,1.),(1.,0.707106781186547,1.),(1.,0.707106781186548,1.),(1.,
0.707106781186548,1.),(1.,0.707106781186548,1.),(1.,0.707106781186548,1.),(1.,0.707106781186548,
1.),(1.,0.707106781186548,1.),(1.,0.707106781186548,1.),(1.,0.707106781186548,1.),(1.,
0.707106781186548,1.),(1.,0.707106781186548,1.),(1.,0.707106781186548,1.),(1.,0.707106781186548,
1.),(1.,0.707106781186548,1.),(1.,0.707106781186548,1.),(1.,0.707106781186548,1.),(1.,
0.707106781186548,1.),(1.,0.707106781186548,1.),(1.,0.707106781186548,1.),(1.,0.707106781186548,
1.),(1.,0.707106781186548,1.),(1.,0.707106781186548,1.),(1.,0.707106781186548,1.),(1.,
0.707106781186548,1.),(1.,0.707106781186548,1.),(1.,0.707106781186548,1.),(1.,0.707106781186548,
1.),(1.,0.707106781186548,1.),(1.,0.707106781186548,1.),(1.,0.707106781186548,1.),(1.,
0.707106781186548,1.),(1.,0.707106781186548,1.),(1.,0.707106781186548,1.),(1.,0.707106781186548,
1.),(1.,0.707106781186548,1.),(1.,0.707106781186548,1.),(1.,0.707106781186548,1.),(1.,
0.707106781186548,1.),(1.,0.707106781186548,1.),(1.,0.707106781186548,1.),(1.,0.707106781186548,
1.),(1.,0.707106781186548,1.),(1.,0.707106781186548,1.),(1.,0.707106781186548,1.),(1.,
0.707106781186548,1.),(1.,0.707106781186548,1.),(1.,0.707106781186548,1.),(1.,0.707106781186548,
1.),(1.,0.707106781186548,1.),(1.,0.707106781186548,1.),(1.,0.707106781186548,1.),(1.,
0.707106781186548,1.),(1.,0.707106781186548,1.),(1.,0.707106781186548,1.),(1.,0.707106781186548,
1.),(1.,0.707106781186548,1.),(1.,0.707106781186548,1.),(1.,0.707106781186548,1.),(1.,
0.707106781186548,1.),(1.,0.707106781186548,1.),(1.,0.707106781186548,1.),(1.,0.707106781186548,
1.),(1.,0.707106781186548,1.))) REPRESENTATION_ITEM('') SURFACE());
#639=CARTESIAN_POINT('',(3.32786790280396,0.,-28.2237790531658));
#640=CARTESIAN_POINT('',(4.00808839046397,0.,-28.1103108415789));
#641=CARTESIAN_POINT('',(4.68259149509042,0.,-27.9622844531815));
#642=CARTESIAN_POINT('',(6.0135566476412,0.,-27.5999158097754));
#643=CARTESIAN_POINT('',(6.67001602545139,0.,-27.3855637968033));
#644=CARTESIAN_POINT('',(7.95945718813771,0.,-26.8942251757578));
#645=CARTESIAN_POINT('',(8.59242441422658,0.,-26.617200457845));
#646=CARTESIAN_POINT('',(9.8295580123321,0.,-26.0051257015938));
#647=CARTESIAN_POINT('',(10.4337247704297,0.,-25.670076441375));
#648=CARTESIAN_POINT('',(11.6051561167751,0.,-24.9494443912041));
#649=CARTESIAN_POINT('',(12.1726512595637,0.,-24.5642353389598));
#650=CARTESIAN_POINT('',(13.2723134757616,0.,-23.7464719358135));
#651=CARTESIAN_POINT('',(13.8044818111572,0.,-23.31391927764));
#652=CARTESIAN_POINT('',(14.8314113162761,0.,-22.4062355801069));
#653=CARTESIAN_POINT('',(15.3261602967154,0.,-21.9310907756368));
#654=CARTESIAN_POINT('',(16.2764802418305,0.,-20.9430566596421));
#655=CARTESIAN_POINT('',(16.7320424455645,0.,-20.4301589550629));
#656=CARTESIAN_POINT('',(17.7621799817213,0.,-19.1772656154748));
#657=CARTESIAN_POINT('',(18.3193044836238,0.,-18.422847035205));
#658=CARTESIAN_POINT('',(19.3564040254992,0.,-16.8626290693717));
#659=CARTESIAN_POINT('',(19.8363503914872,0.,-16.0568107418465));
#660=CARTESIAN_POINT('',(20.7187058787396,0.,-14.4024587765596));
#661=CARTESIAN_POINT('',(21.121007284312,0.,-13.5538678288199));
#662=CARTESIAN_POINT('',(21.8468981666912,0.,-11.8238744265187));
#663=CARTESIAN_POINT('',(22.1704958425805,0.,-10.9424754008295));
#664=CARTESIAN_POINT('',(22.7357498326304,0.,-9.16514811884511));
#665=CARTESIAN_POINT('',(22.9783156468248,0.,-8.26950818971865));
#666=CARTESIAN_POINT('',(23.3868720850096,0.,-6.46057421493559));
#667=CARTESIAN_POINT('',(23.5528290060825,0.,-5.54727258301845));
#668=CARTESIAN_POINT('',(23.8080569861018,0.,-3.71076518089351));
#669=CARTESIAN_POINT('',(23.8973913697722,0.,-2.78756822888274));
#670=CARTESIAN_POINT('',(23.9997225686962,0.,-0.937330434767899));
#671=CARTESIAN_POINT('',(24.0127335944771,0.,-0.0102903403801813));
#672=CARTESIAN_POINT('',(23.9421075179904,0.,2.58913030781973));
#673=CARTESIAN_POINT('',(23.7721161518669,0.,4.25999473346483));
#674=CARTESIAN_POINT('',(23.1823682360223,0.,7.55615824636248));
#675=CARTESIAN_POINT('',(22.7627401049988,0.,9.18148031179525));
#676=CARTESIAN_POINT('',(21.7460253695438,0.,12.1346955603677));
#677=CARTESIAN_POINT('',(21.1801233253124,0.,13.4733214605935));
#678=CARTESIAN_POINT('',(19.8610461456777,0.,16.0548238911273));
#679=CARTESIAN_POINT('',(19.1079818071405,0.,17.2977565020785));
#680=CARTESIAN_POINT('',(17.5281926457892,0.,19.4984624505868));
#681=CARTESIAN_POINT('',(16.7239729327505,0.,20.4722717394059));
#682=CARTESIAN_POINT('',(15.4186746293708,0.,21.8374306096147));
#683=CARTESIAN_POINT('',(14.9669650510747,0.,22.2766477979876));
#684=CARTESIAN_POINT('',(14.0317244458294,0.,23.1196665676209));
#685=CARTESIAN_POINT('',(13.5482049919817,0.,23.5234809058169));
#686=CARTESIAN_POINT('',(12.585272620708,0.,24.2655195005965));
#687=CARTESIAN_POINT('',(12.1078621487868,0.,24.6063443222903));
#688=CARTESIAN_POINT('',(11.1287802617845,0.,25.2508237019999));
#689=CARTESIAN_POINT('',(10.6271182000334,0.,25.554492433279));
#690=CARTESIAN_POINT('',(9.60154593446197,0.,26.1217367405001));
#691=CARTESIAN_POINT('',(9.07763464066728,0.,26.3853103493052));
#692=CARTESIAN_POINT('',(8.01024668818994,0.,26.8694178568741));
#693=CARTESIAN_POINT('',(7.46676990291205,0.,27.0899514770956));
#694=CARTESIAN_POINT('',(6.36154826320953,0.,27.4859698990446));
#695=CARTESIAN_POINT('',(5.79974822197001,0.,27.6613010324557));
#696=CARTESIAN_POINT('',(4.66326964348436,0.,27.9636466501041));
#697=CARTESIAN_POINT('',(4.08859119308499,0.,28.0906614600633));
#698=CARTESIAN_POINT('',(2.93050765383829,0.,28.2945979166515));
#699=CARTESIAN_POINT('',(2.34710426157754,0.,28.3715291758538));
#700=CARTESIAN_POINT('',(1.17579969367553,0.,28.4742301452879));
#701=CARTESIAN_POINT('',(0.58789851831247,0.,28.499999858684));
#702=CARTESIAN_POINT('',(-0.582365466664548,0.,28.500000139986));
#703=CARTESIAN_POINT('',(-1.16472832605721,0.,28.4747134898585));
#704=CARTESIAN_POINT('',(-2.32505528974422,0.,28.373936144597));
#705=CARTESIAN_POINT('',(-2.90301959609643,0.,28.2984477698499));
#706=CARTESIAN_POINT('',(-4.05063112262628,0.,28.0982822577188));
#707=CARTESIAN_POINT('',(-4.62027441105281,0.,27.9735826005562));
#708=CARTESIAN_POINT('',(-5.74708937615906,0.,27.6766907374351));
#709=CARTESIAN_POINT('',(-6.30425870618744,0.,27.5044896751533));
#710=CARTESIAN_POINT('',(-7.56912000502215,0.,27.0556478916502));
#711=CARTESIAN_POINT('',(-8.27123936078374,0.,26.7631715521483));
#712=CARTESIAN_POINT('',(-9.64147433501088,0.,26.1070587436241));
#713=CARTESIAN_POINT('',(-10.3095790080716,0.,25.7433995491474));
#714=CARTESIAN_POINT('',(-11.6069913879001,0.,24.9510817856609));
#715=CARTESIAN_POINT('',(-12.236253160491,0.,24.5223482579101));
#716=CARTESIAN_POINT('',(-13.4511921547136,0.,23.6068409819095));
#717=CARTESIAN_POINT('',(-14.0368624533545,0.,23.1200580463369));
#718=CARTESIAN_POINT('',(-14.8778179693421,0.,22.3537804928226));
#719=CARTESIAN_POINT('',(-15.1508434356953,0.,22.0934678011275));
#720=CARTESIAN_POINT('',(-15.6850398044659,0.,21.5611542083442));
#721=CARTESIAN_POINT('',(-15.9462153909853,0.,21.289158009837));
#722=CARTESIAN_POINT('',(-16.7118156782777,0.,20.4565898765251));
#723=CARTESIAN_POINT('',(-17.1983499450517,0.,19.8794054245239));
#724=CARTESIAN_POINT('',(-18.1220296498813,0.,18.686980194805));
#725=CARTESIAN_POINT('',(-18.5591743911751,0.,18.0717388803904));
#726=CARTESIAN_POINT('',(-19.3833892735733,0.,16.8085283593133));
#727=CARTESIAN_POINT('',(-19.7704514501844,0.,16.1605539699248));
#728=CARTESIAN_POINT('',(-20.5856735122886,0.,14.6692075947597));
#729=CARTESIAN_POINT('',(-20.9994051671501,0.,13.817919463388));
#730=CARTESIAN_POINT('',(-21.7468523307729,0.,12.0813593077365));
#731=CARTESIAN_POINT('',(-22.0805876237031,0.,11.1960957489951));
#732=CARTESIAN_POINT('',(-22.6685206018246,0.,9.39856507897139));
#733=CARTESIAN_POINT('',(-22.9226386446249,0.,8.48627192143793));
#734=CARTESIAN_POINT('',(-23.3509709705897,0.,6.64347954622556));
#735=CARTESIAN_POINT('',(-23.5251938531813,0.,5.71298229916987));
#736=CARTESIAN_POINT('',(-23.9125218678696,0.,3.01443347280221));
#737=CARTESIAN_POINT('',(-24.024571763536,0.,1.23096797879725));
#738=CARTESIAN_POINT('',(-23.9664753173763,0.,-2.3303018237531));
#739=CARTESIAN_POINT('',(-23.7965307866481,0.,-4.10810926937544));
#740=CARTESIAN_POINT('',(-23.3491164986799,0.,-6.63067676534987));
#741=CARTESIAN_POINT('',(-23.1850310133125,0.,-7.39682306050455));
#742=CARTESIAN_POINT('',(-22.8020803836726,0.,-8.91555049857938));
#743=CARTESIAN_POINT('',(-22.5832120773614,0.,-9.66813085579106));
#744=CARTESIAN_POINT('',(-22.0907316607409,0.,-11.1548867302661));
#745=CARTESIAN_POINT('',(-21.8171364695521,0.,-11.8890678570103));
#746=CARTESIAN_POINT('',(-21.2152491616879,0.,-13.3344175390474));
#747=CARTESIAN_POINT('',(-20.8869781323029,0.,-14.0455948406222));
#748=CARTESIAN_POINT('',(-20.2244091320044,0.,-15.3448950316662));
#749=CARTESIAN_POINT('',(-19.8970506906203,0.,-15.9365636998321));
#750=CARTESIAN_POINT('',(-19.201842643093,0.,-17.095709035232));
#751=CARTESIAN_POINT('',(-18.8339916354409,0.,-17.6631848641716));
#752=CARTESIAN_POINT('',(-18.0583685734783,0.,-18.7699670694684));
#753=CARTESIAN_POINT('',(-17.6506078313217,0.,-19.3092813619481));
#754=CARTESIAN_POINT('',(-16.7959278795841,0.,-20.3556907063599));
#755=CARTESIAN_POINT('',(-16.3490233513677,0.,-20.86279771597));
#756=CARTESIAN_POINT('',(-15.4702572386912,0.,-21.7848250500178));
#757=CARTESIAN_POINT('',(-15.0425010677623,0.,-22.2036609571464));
#758=CARTESIAN_POINT('',(-14.1582341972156,0.,-23.0095245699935));
#759=CARTESIAN_POINT('',(-13.701734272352,0.,-23.3965640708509));
#760=CARTESIAN_POINT('',(-12.7613099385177,0.,-24.1356885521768));
#761=CARTESIAN_POINT('',(-12.2773888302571,0.,-24.4877777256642));
#762=CARTESIAN_POINT('',(-11.2838883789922,0.,-25.153742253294));
#763=CARTESIAN_POINT('',(-10.7743096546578,0.,-25.4676185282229));
#764=CARTESIAN_POINT('',(-9.75778354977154,0.,-26.0392623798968));
#765=CARTESIAN_POINT('',(-9.25197105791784,0.,-26.2990468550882));
#766=CARTESIAN_POINT('',(-8.22165101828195,0.,-26.7784646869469));
#767=CARTESIAN_POINT('',(-7.69714435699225,0.,-26.998099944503));
#768=CARTESIAN_POINT('',(-6.63225352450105,0.,-27.3947468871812));
#769=CARTESIAN_POINT('',(-6.09187018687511,0.,-27.5717608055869));
#770=CARTESIAN_POINT('',(-4.99840002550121,0.,-27.8810493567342));
#771=CARTESIAN_POINT('',(-4.44531250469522,0.,-28.0133215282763));
#772=CARTESIAN_POINT('',(-3.29443025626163,0.,-28.2383769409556));
#773=CARTESIAN_POINT('',(-2.69603399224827,0.,-28.3281035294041));
#774=CARTESIAN_POINT('',(-1.49360131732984,0.,-28.4536284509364));
#775=CARTESIAN_POINT('',(-0.889564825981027,0.,-28.4894260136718));
#776=CARTESIAN_POINT('',(0.319486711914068,0.,-28.506540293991));
#777=CARTESIAN_POINT('',(0.924502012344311,0.,-28.487839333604));
#778=CARTESIAN_POINT('',(2.13043339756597,0.,-28.3962141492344));
#779=CARTESIAN_POINT('',(2.73134909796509,0.,-28.3232849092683));
#780=CARTESIAN_POINT('',(3.32786790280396,0.,-28.2237790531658));
#781=B_SPLINE_CURVE_WITH_KNOTS('',3,(#639,#640,#641,#642,#643,#644,#645,#646,#647,#648,#649,
#650,#651,#652,#653,#654,#655,#656,#657,#658,#659,#660,#661,#662,#663,#664,#665,#666,#667,#668,
#669,#670,#671,#672,#673,#674,#675,#676,#677,#678,#679,#680,#681,#682,#683,#684,#685,#686,#687,
#688,#689,#690,#691,#692,#693,#694,#695,#696,#697,#698,#699,#700,#701,#702,#703,#704,#705,#706,
#707,#708,#709,#710,#711,#712,#713,#714,#715,#716,#717,#718,#719,#720,#721,#722,#723,#724,#725,
#726,#727,#728,#729,#730,#731,#732,#733,#734,#735,#736,#737,#738,#739,#740,#741,#742,#743,#744,
#745,#746,#747,#748,#749,#750,#751,#752,#753,#754,#755,#756,#757,#758,#759,#760,#761,#762,#763,
#764,#765,#766,#767,#768,#769,#770,#771,#772,#773,#774,#775,#776,#777,#778,#779,#780),
.UNSPECIFIED.,.T.,.F.,(4,2,2,2,2,2,2,2,2,2,2,2,2,2,2,2,2,2,2,2,2,2,2,2,2,2,2,2,2,2,2,2,2,2,2,2,
2,2,2,2,2,2,2,2,2,2,2,2,2,2,2,2,2,2,2,2,2,2,2,2,2,2,2,2,2,2,2,2,2,2,4),(0.,2.06808798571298,
4.13648037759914,6.20613390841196,8.27575968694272,10.3307637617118,12.3856943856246,
14.4412915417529,16.4973470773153,19.3057688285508,22.1152315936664,24.9285643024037,
27.7416038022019,30.5219166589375,33.3034515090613,36.0826853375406,38.8614016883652,
43.8798447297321,48.8957084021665,53.2416920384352,57.585109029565,61.3606251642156,
63.249252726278,65.1371969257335,66.8953635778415,68.6528574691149,70.4104375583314,
72.1680290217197,73.9315189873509,75.6949970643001,77.4581365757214,79.2212759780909,
80.9678214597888,82.714286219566,84.4615511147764,86.2091419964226,88.4865125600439,
90.764611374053,93.0453545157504,95.3264591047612,96.4578500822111,97.5887898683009,
99.8505233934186,102.112288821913,104.374413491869,107.209593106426,110.044070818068,
112.88137491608,115.718373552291,121.055672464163,126.389153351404,128.738114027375,
131.08721031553,133.435581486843,135.783049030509,137.81007684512,139.837174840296,
141.863699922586,143.88946815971,145.684011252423,147.477885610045,149.271544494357,
151.065160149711,152.769373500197,154.473506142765,156.177549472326,157.881686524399,
159.694512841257,161.507365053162,163.320805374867,165.134413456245),.UNSPECIFIED.);
#782=CARTESIAN_POINT('',(3.32786790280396,0.,-28.2237790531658));
#783=VERTEX_POINT('',#782);
#784=EDGE_CURVE('E246',#783,#783,#781,.T.);
#785=ORIENTED_EDGE('',*,*,#784,.T.);
#786=EDGE_LOOP('',(#785));
#787=FACE_BOUND('',#786,.T.);
#788=CARTESIAN_POINT('',(-15.25,0.,0.));
#789=DIRECTION('',(0.,1.,0.));
#790=DIRECTION('',(0.,0.,1.));
#791=AXIS2_PLACEMENT_3D('',#788,#789,#790);
#792=CIRCLE('',#791,4.25);
#793=CARTESIAN_POINT('',(-15.25,0.,-4.25));
#794=VERTEX_POINT('',#793);
#795=CARTESIAN_POINT('',(-15.25,0.,4.25));
#796=VERTEX_POINT('',#795);
#797=EDGE_CURVE('E142',#794,#796,#792,.T.);
#798=ORIENTED_EDGE('',*,*,#797,.T.);
#799=DIRECTION('',(1.,0.,0.));
#800=VECTOR('',#799,1.);
#801=CARTESIAN_POINT('',(-15.25,0.,4.25));
#802=LINE('',#801,#800);
#803=CARTESIAN_POINT('',(15.25,0.,4.25));
#804=VERTEX_POINT('',#803);
#805=EDGE_CURVE('E203',#796,#804,#802,.T.);
#806=ORIENTED_EDGE('',*,*,#805,.T.);
#807=CARTESIAN_POINT('',(15.25,0.,0.));
#808=DIRECTION('',(0.,-1.,0.));
#809=DIRECTION('',(0.,0.,-1.));
#810=AXIS2_PLACEMENT_3D('',#807,#808,#809);
#811=CIRCLE('',#810,4.25);
#812=CARTESIAN_POINT('',(15.25,0.,-4.25));
#813=VERTEX_POINT('',#812);
#814=EDGE_CURVE('E413',#813,#804,#811,.T.);
#815=ORIENTED_EDGE('',*,*,#814,.F.);
#816=DIRECTION('',(1.,0.,0.));
#817=VECTOR('',#816,1.);
#818=CARTESIAN_POINT('',(-15.25,0.,-4.25));
#819=LINE('',#818,#817);
#820=EDGE_CURVE('E412',#794,#813,#819,.T.);
#821=ORIENTED_EDGE('',*,*,#820,.F.);
#822=EDGE_LOOP('',(#798,#806,#815,#821));
#823=FACE_BOUND('',#822,.T.);
#824=ADVANCED_FACE('F225',(#787,#823),#211,.F.);
#825=DIRECTION('',(0.,-1.,0.));
#826=VECTOR('',#825,1.);
#827=SURFACE_OF_LINEAR_EXTRUSION('',#28,#826);
#828=CARTESIAN_POINT('',(3.82146034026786,3.,-31.1828948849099));
#829=CARTESIAN_POINT('',(3.13719519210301,3.,-31.297038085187));
#830=CARTESIAN_POINT('',(2.44729713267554,3.,-31.3807861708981));
#831=CARTESIAN_POINT('',(1.0622304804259,3.,-31.4860213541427));
#832=CARTESIAN_POINT('',(0.367062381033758,3.,-31.5075142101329));
#833=CARTESIAN_POINT('',(-1.02204315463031,3.,-31.4878513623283));
#834=CARTESIAN_POINT('',(-1.7159809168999,3.,-31.4467159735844));
#835=CARTESIAN_POINT('',(-3.09661690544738,3.,-31.30258818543));
#836=CARTESIAN_POINT('',(-3.78331523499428,3.,-31.1995966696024));
#837=CARTESIAN_POINT('',(-5.10273207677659,3.,-30.9415850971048));
#838=CARTESIAN_POINT('',(-5.73621852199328,3.,-30.7900546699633));
#839=CARTESIAN_POINT('',(-6.98708067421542,3.,-30.4362480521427));
#840=CARTESIAN_POINT('',(-7.60445726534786,3.,-30.2339746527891));
#841=CARTESIAN_POINT('',(-8.81924785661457,3.,-29.781494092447));
#842=CARTESIAN_POINT('',(-9.4166608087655,3.,-29.5312844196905));
#843=CARTESIAN_POINT('',(-10.5882214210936,3.,-28.9861464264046));
#844=CARTESIAN_POINT('',(-11.1623679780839,3.,-28.6912159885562));
#845=CARTESIAN_POINT('',(-12.3141540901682,3.,-28.0435090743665));
#846=CARTESIAN_POINT('',(-12.890396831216,3.,-27.6885096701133));
#847=CARTESIAN_POINT('',(-14.0116913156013,3.,-26.9368825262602));
#848=CARTESIAN_POINT('',(-14.556742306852,3.,-26.5402537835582));
#849=CARTESIAN_POINT('',(-15.6139206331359,3.,-25.7093671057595));
#850=CARTESIAN_POINT('',(-16.1260440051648,3.,-25.2751046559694));
#851=CARTESIAN_POINT('',(-17.1162016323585,3.,-24.3727391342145));
#852=CARTESIAN_POINT('',(-17.5942231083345,3.,-23.9046235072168));
#853=CARTESIAN_POINT('',(-18.5745076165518,3.,-22.8760808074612));
#854=CARTESIAN_POINT('',(-19.0719580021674,3.,-22.3115311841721));
#855=CARTESIAN_POINT('',(-20.0215515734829,3.,-21.1489163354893));
#856=CARTESIAN_POINT('',(-20.4736777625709,3.,-20.5508386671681));
#857=CARTESIAN_POINT('',(-21.3322577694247,3.,-19.3256804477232));
#858=CARTESIAN_POINT('',(-21.7386986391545,3.,-18.6985917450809));
#859=CARTESIAN_POINT('',(-22.5057024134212,3.,-17.419738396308));
#860=CARTESIAN_POINT('',(-22.8662669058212,3.,-16.7679746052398));
#861=CARTESIAN_POINT('',(-23.5951070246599,3.,-15.3387179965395));
#862=CARTESIAN_POINT('',(-23.9555910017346,3.,-14.5576373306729));
#863=CARTESIAN_POINT('',(-24.6157385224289,3.,-12.972382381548));
#864=CARTESIAN_POINT('',(-24.9153786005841,3.,-12.1681993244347));
#865=CARTESIAN_POINT('',(-25.4542238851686,3.,-10.5414744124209));
#866=CARTESIAN_POINT('',(-25.6934104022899,3.,-9.71892696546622));
#867=CARTESIAN_POINT('',(-26.1116081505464,3.,-8.06040137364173));
#868=CARTESIAN_POINT('',(-26.2906228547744,3.,-7.22442400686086));
#869=CARTESIAN_POINT('',(-26.7785440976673,3.,-4.47358145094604));
#870=CARTESIAN_POINT('',(-26.9634950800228,3.,-2.53747281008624));
#871=CARTESIAN_POINT('',(-27.0267561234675,3.,1.34041530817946));
#872=CARTESIAN_POINT('',(-26.904846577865,3.,3.28219785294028));
#873=CARTESIAN_POINT('',(-26.4826591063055,3.,6.22347841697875));
#874=CARTESIAN_POINT('',(-26.2926926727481,3.,7.23826737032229));
#875=CARTESIAN_POINT('',(-25.8251309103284,3.,9.24985190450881));
#876=CARTESIAN_POINT('',(-25.5475261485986,3.,10.2466455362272));
#877=CARTESIAN_POINT('',(-24.9043125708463,3.,12.213186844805));
#878=CARTESIAN_POINT('',(-24.5387916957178,3.,13.1829604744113));
#879=CARTESIAN_POINT('',(-23.7186469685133,3.,15.088423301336));
#880=CARTESIAN_POINT('',(-23.2640010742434,3.,16.0241039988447));
#881=CARTESIAN_POINT('',(-22.3661639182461,3.,17.6665802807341));
#882=CARTESIAN_POINT('',(-21.9392313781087,3.,18.3814127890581));
#883=CARTESIAN_POINT('',(-21.028309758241,3.,19.777512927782));
#884=CARTESIAN_POINT('',(-20.5443297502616,3.,20.4587858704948));
#885=CARTESIAN_POINT('',(-19.5194254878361,3.,21.7818870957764));
#886=CARTESIAN_POINT('',(-18.9785020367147,3.,22.423715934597));
#887=CARTESIAN_POINT('',(-18.1252674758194,3.,23.3515821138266));
#888=CARTESIAN_POINT('',(-17.8338709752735,3.,23.6550672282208));
#889=CARTESIAN_POINT('',(-17.2371396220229,3.,24.2496955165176));
#890=CARTESIAN_POINT('',(-16.9317992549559,3.,24.5408337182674));
#891=CARTESIAN_POINT('',(-15.9901350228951,3.,25.3988779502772));
#892=CARTESIAN_POINT('',(-15.3327777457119,3.,25.9453734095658));
#893=CARTESIAN_POINT('',(-13.9655222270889,3.,26.9756556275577));
#894=CARTESIAN_POINT('',(-13.2556323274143,3.,27.4594523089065));
#895=CARTESIAN_POINT('',(-11.7881825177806,3.,28.3556092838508));
#896=CARTESIAN_POINT('',(-11.0306788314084,3.,28.7680517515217));
#897=CARTESIAN_POINT('',(-9.47336569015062,3.,29.5137406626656));
#898=CARTESIAN_POINT('',(-8.67356983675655,3.,29.8470123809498));
#899=CARTESIAN_POINT('',(-7.22982696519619,3.,30.3593315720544));
#900=CARTESIAN_POINT('',(-6.59290668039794,3.,30.5562206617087));
#901=CARTESIAN_POINT('',(-5.30320841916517,3.,30.8960281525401));
#902=CARTESIAN_POINT('',(-4.65043342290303,3.,31.0389566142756));
#903=CARTESIAN_POINT('',(-3.33420052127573,3.,31.2685325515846));
#904=CARTESIAN_POINT('',(-2.67074764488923,3.,31.3552057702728));
#905=CARTESIAN_POINT('',(-1.33819768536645,3.,31.4709409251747));
#906=CARTESIAN_POINT('',(-0.66910034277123,3.,31.5000001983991));
#907=CARTESIAN_POINT('',(0.675457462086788,3.,31.4999997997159));
#908=CARTESIAN_POINT('',(1.35091798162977,3.,31.4703853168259));
#909=CARTESIAN_POINT('',(2.69606347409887,3.,31.3524420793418));
#910=CARTESIAN_POINT('',(3.36574844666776,3.,31.264113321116));
#911=CARTESIAN_POINT('',(4.69394889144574,3.,31.0302199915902));
#912=CARTESIAN_POINT('',(5.35246219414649,3.,30.8846444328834));
#913=CARTESIAN_POINT('',(6.65313012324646,3.,30.5386188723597));
#914=CARTESIAN_POINT('',(7.29528463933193,3.,30.3381685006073));
#915=CARTESIAN_POINT('',(8.55667163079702,3.,29.8861941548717));
#916=CARTESIAN_POINT('',(9.17597359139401,3.,29.6348432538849));
#917=CARTESIAN_POINT('',(10.3901961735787,3.,29.0841402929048));
#918=CARTESIAN_POINT('',(10.9851169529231,3.,28.7847885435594));
#919=CARTESIAN_POINT('',(12.1475479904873,3.,28.141848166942));
#920=CARTESIAN_POINT('',(12.7150595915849,3.,27.798261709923));
#921=CARTESIAN_POINT('',(13.8205571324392,3.,27.070569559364));
#922=CARTESIAN_POINT('',(14.3585316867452,3.,26.6864484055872));
#923=CARTESIAN_POINT('',(15.4415642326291,3.,25.8518613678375));
#924=CARTESIAN_POINT('',(15.984213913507,3.,25.3985911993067));
#925=CARTESIAN_POINT('',(17.0317578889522,3.,24.4543410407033));
#926=CARTESIAN_POINT('',(17.5366384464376,3.,23.9633474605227));
#927=CARTESIAN_POINT('',(18.9928546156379,3.,22.4403621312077));
#928=CARTESIAN_POINT('',(19.8862829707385,3.,21.3579601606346));
#929=CARTESIAN_POINT('',(21.6360228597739,3.,18.9205208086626));
#930=CARTESIAN_POINT('',(22.4665374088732,3.,17.5489640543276));
#931=CARTESIAN_POINT('',(23.9175950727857,3.,14.7091531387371));
#932=CARTESIAN_POINT('',(24.5380138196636,3.,13.2408423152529));
#933=CARTESIAN_POINT('',(25.6508428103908,3.,10.0084704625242));
#934=CARTESIAN_POINT('',(26.1087819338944,3.,8.23370794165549));
#935=CARTESIAN_POINT('',(26.7519155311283,3.,4.63916027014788));
#936=CARTESIAN_POINT('',(26.9369696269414,3.,2.81935243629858));
#937=CARTESIAN_POINT('',(27.013860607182,3.,-0.0112294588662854));
#938=CARTESIAN_POINT('',(26.9997004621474,3.,-1.0205999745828));
#939=CARTESIAN_POINT('',(26.8882598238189,3.,-3.03559922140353));
#940=CARTESIAN_POINT('',(26.7909638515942,3.,-4.04122722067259));
#941=CARTESIAN_POINT('',(26.5127940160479,3.,-6.04280925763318));
#942=CARTESIAN_POINT('',(26.3318510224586,3.,-7.03875459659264));
#943=CARTESIAN_POINT('',(25.8859321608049,3.,-9.01311693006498));
#944=CARTESIAN_POINT('',(25.6209932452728,3.,-9.9915414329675));
#945=CARTESIAN_POINT('',(25.0027377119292,3.,-11.9355224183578));
#946=CARTESIAN_POINT('',(24.6484175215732,3.,-12.9007918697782));
#947=CARTESIAN_POINT('',(23.8521870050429,3.,-14.7984242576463));
#948=CARTESIAN_POINT('',(23.4102675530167,3.,-15.7307837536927));
#949=CARTESIAN_POINT('',(22.4389181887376,3.,-17.5519930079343));
#950=CARTESIAN_POINT('',(21.9096094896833,3.,-18.4409008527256));
#951=CARTESIAN_POINT('',(20.7629440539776,3.,-20.1659514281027));
#952=CARTESIAN_POINT('',(20.1456200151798,3.,-21.0021135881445));
#953=CARTESIAN_POINT('',(19.0008913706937,3.,-22.3943727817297));
#954=CARTESIAN_POINT('',(18.4937020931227,3.,-22.9654881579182));
#955=CARTESIAN_POINT('',(17.4333393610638,3.,-24.06793285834));
#956=CARTESIAN_POINT('',(16.880176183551,3.,-24.5992710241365));
#957=CARTESIAN_POINT('',(15.7293282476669,3.,-25.6164831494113));
#958=CARTESIAN_POINT('',(15.1316579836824,3.,-26.1023717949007));
#959=CARTESIAN_POINT('',(13.8937160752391,3.,-27.022966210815));
#960=CARTESIAN_POINT('',(13.2534429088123,3.,-27.4576701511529));
#961=CARTESIAN_POINT('',(11.9287012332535,3.,-28.2726134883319));
#962=CARTESIAN_POINT('',(11.2439506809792,3.,-28.6524433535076));
#963=CARTESIAN_POINT('',(9.83872532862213,3.,-29.3476806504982));
#964=CARTESIAN_POINT('',(9.11825004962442,3.,-29.6630872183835));
#965=CARTESIAN_POINT('',(7.6477216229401,3.,-30.2234275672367));
#966=CARTESIAN_POINT('',(6.89768676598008,3.,-30.4684041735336));
#967=CARTESIAN_POINT('',(5.374693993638,3.,-30.8830525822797));
#968=CARTESIAN_POINT('',(4.60173946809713,3.,-31.0527354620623));
#969=CARTESIAN_POINT('',(3.82146034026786,3.,-31.1828948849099));
#970=B_SPLINE_CURVE_WITH_KNOTS('',3,(#828,#829,#830,#831,#832,#833,#834,#835,#836,#837,#838,
#839,#840,#841,#842,#843,#844,#845,#846,#847,#848,#849,#850,#851,#852,#853,#854,#855,#856,#857,
#858,#859,#860,#861,#862,#863,#864,#865,#866,#867,#868,#869,#870,#871,#872,#873,#874,#875,#876,
#877,#878,#879,#880,#881,#882,#883,#884,#885,#886,#887,#888,#889,#890,#891,#892,#893,#894,#895,
#896,#897,#898,#899,#900,#901,#902,#903,#904,#905,#906,#907,#908,#909,#910,#911,#912,#913,#914,
#915,#916,#917,#918,#919,#920,#921,#922,#923,#924,#925,#926,#927,#928,#929,#930,#931,#932,#933,
#934,#935,#936,#937,#938,#939,#940,#941,#942,#943,#944,#945,#946,#947,#948,#949,#950,#951,#952,
#953,#954,#955,#956,#957,#958,#959,#960,#961,#962,#963,#964,#965,#966,#967,#968,#969),
.UNSPECIFIED.,.T.,.F.,(4,2,2,2,2,2,2,2,2,2,2,2,2,2,2,2,2,2,2,2,2,2,2,2,2,2,2,2,2,2,2,2,2,2,2,2,
2,2,2,2,2,2,2,2,2,2,2,2,2,2,2,2,2,2,2,2,2,2,2,2,2,2,2,2,2,2,2,2,2,2,4),(0.,1.81360808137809,
3.62704840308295,5.43990061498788,7.2527269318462,8.95686398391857,10.6609073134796,
12.3650399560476,14.069253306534,15.8628689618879,17.6565278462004,19.4504022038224,
21.2449452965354,23.2707135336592,25.2972386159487,27.324336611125,29.3513644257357,
31.6988319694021,34.047203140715,36.3962994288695,38.7452601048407,44.078740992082,
49.4160399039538,52.2530385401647,55.0903426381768,57.9248203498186,60.7599999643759,
63.0221246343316,65.2838900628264,67.545623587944,68.6765633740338,69.8079543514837,
72.0890589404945,74.3698020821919,76.6479008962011,78.9252714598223,80.6728623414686,
82.420127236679,84.1665919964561,85.9131374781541,87.6762768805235,89.4394163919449,
91.2028944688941,92.9663844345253,94.7239758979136,96.48155598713,98.2390498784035,
99.9972165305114,101.885160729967,103.773788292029,107.54930442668,111.89272141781,
116.238705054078,121.254568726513,126.27301176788,129.051728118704,131.830961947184,
134.612496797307,137.392809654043,140.205849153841,143.019181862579,145.828644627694,
148.63706637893,150.693121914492,152.74871907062,154.803649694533,156.858653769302,
158.928279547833,160.997933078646,163.066325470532,165.134413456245),.UNSPECIFIED.);
#971=CARTESIAN_POINT('',(3.82146034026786,3.,-31.1828948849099));
#972=VERTEX_POINT('',#971);
#973=EDGE_CURVE('E209',#972,#972,#970,.T.);
#974=ORIENTED_EDGE('',*,*,#973,.T.);
#975=EDGE_LOOP('',(#974));
#976=FACE_BOUND('',#975,.T.);
#977=ORIENTED_EDGE('',*,*,#31,.F.);
#978=EDGE_LOOP('',(#977));
#979=FACE_BOUND('',#978,.T.);
#980=ADVANCED_FACE('F221',(#976,#979),#827,.F.);
#981=CARTESIAN_POINT('',(-15.25,11.,0.));
#982=DIRECTION('',(0.,-1.,0.));
#983=DIRECTION('',(0.,0.,-1.));
#984=AXIS2_PLACEMENT_3D('',#981,#982,#983);
#985=CYLINDRICAL_SURFACE('',#984,4.25);
#986=CARTESIAN_POINT('',(-15.25,1.06856936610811,0.));
#987=DIRECTION('',(0.,-1.,0.));
#988=DIRECTION('',(0.,0.,-1.));
#989=AXIS2_PLACEMENT_3D('',#986,#987,#988);
#990=CIRCLE('',#989,4.25);
#991=CARTESIAN_POINT('',(-15.25,1.06856936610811,4.25));
#992=VERTEX_POINT('',#991);
#993=CARTESIAN_POINT('',(-15.25,1.06856936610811,-4.25));
#994=VERTEX_POINT('',#993);
#995=EDGE_CURVE('E69',#992,#994,#990,.T.);
#996=ORIENTED_EDGE('',*,*,#995,.F.);
#997=DIRECTION('',(0.,-1.,0.));
#998=VECTOR('',#997,1.);
#999=CARTESIAN_POINT('',(-15.25,11.,4.25));
#1000=LINE('',#999,#998);
#1001=EDGE_CURVE('E198',#992,#796,#1000,.T.);
#1002=ORIENTED_EDGE('',*,*,#1001,.T.);
#1003=ORIENTED_EDGE('',*,*,#797,.F.);
#1004=DIRECTION('',(0.,-1.,0.));
#1005=VECTOR('',#1004,1.);
#1006=CARTESIAN_POINT('',(-15.25,11.,-4.25));
#1007=LINE('',#1006,#1005);
#1008=EDGE_CURVE('E200',#994,#794,#1007,.T.);
#1009=ORIENTED_EDGE('',*,*,#1008,.F.);
#1010=EDGE_LOOP('',(#996,#1002,#1003,#1009));
#1011=FACE_BOUND('',#1010,.T.);
#1012=ADVANCED_FACE('F196',(#1011),#985,.F.);
#1013=CARTESIAN_POINT('',(-15.25,11.,4.25));
#1014=DIRECTION('',(0.,0.,-1.));
#1015=DIRECTION('',(-1.,0.,0.));
#1016=AXIS2_PLACEMENT_3D('',#1013,#1014,#1015);
#1017=PLANE('',#1016);
#1018=DIRECTION('',(-1.,0.,0.));
#1019=VECTOR('',#1018,1.);
#1020=CARTESIAN_POINT('',(-15.25,1.06856936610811,4.25));
#1021=LINE('',#1020,#1019);
#1022=CARTESIAN_POINT('',(15.25,1.06856936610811,4.25));
#1023=VERTEX_POINT('',#1022);
#1024=EDGE_CURVE('E189',#1023,#992,#1021,.T.);
#1025=ORIENTED_EDGE('',*,*,#1024,.F.);
#1026=DIRECTION('',(0.,-1.,0.));
#1027=VECTOR('',#1026,1.);
#1028=CARTESIAN_POINT('',(15.25,11.,4.25));
#1029=LINE('',#1028,#1027);
#1030=EDGE_CURVE('E206',#1023,#804,#1029,.T.);
#1031=ORIENTED_EDGE('',*,*,#1030,.T.);
#1032=ORIENTED_EDGE('',*,*,#805,.F.);
#1033=ORIENTED_EDGE('',*,*,#1001,.F.);
#1034=EDGE_LOOP('',(#1025,#1031,#1032,#1033));
#1035=FACE_BOUND('',#1034,.T.);
#1036=ADVANCED_FACE('F201',(#1035),#1017,.T.);
#1037=CARTESIAN_POINT('',(15.25,11.,0.));
#1038=DIRECTION('',(0.,-1.,0.));
#1039=DIRECTION('',(0.,0.,-1.));
#1040=AXIS2_PLACEMENT_3D('',#1037,#1038,#1039);
#1041=CYLINDRICAL_SURFACE('',#1040,4.25);
#1042=ORIENTED_EDGE('',*,*,#1030,.F.);
#1043=CARTESIAN_POINT('',(15.25,1.06856936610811,0.));
#1044=DIRECTION('',(0.,-1.,0.));
#1045=DIRECTION('',(0.,0.,-1.));
#1046=AXIS2_PLACEMENT_3D('',#1043,#1044,#1045);
#1047=CIRCLE('',#1046,4.25);
#1048=CARTESIAN_POINT('',(15.25,1.06856936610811,-4.25));
#1049=VERTEX_POINT('',#1048);
#1050=EDGE_CURVE('E187',#1023,#1049,#1047,.F.);
#1051=ORIENTED_EDGE('',*,*,#1050,.T.);
#1052=DIRECTION('',(0.,-1.,0.));
#1053=VECTOR('',#1052,1.);
#1054=CARTESIAN_POINT('',(15.25,11.,-4.25));
#1055=LINE('',#1054,#1053);
#1056=EDGE_CURVE('E211',#1049,#813,#1055,.T.);
#1057=ORIENTED_EDGE('',*,*,#1056,.T.);
#1058=ORIENTED_EDGE('',*,*,#814,.T.);
#1059=EDGE_LOOP('',(#1042,#1051,#1057,#1058));
#1060=FACE_BOUND('',#1059,.T.);
#1061=ADVANCED_FACE('F289',(#1060),#1041,.F.);
#1062=CARTESIAN_POINT('',(-15.25,11.,-4.25));
#1063=DIRECTION('',(0.,0.,-1.));
#1064=DIRECTION('',(-1.,0.,0.));
#1065=AXIS2_PLACEMENT_3D('',#1062,#1063,#1064);
#1066=PLANE('',#1065);
#1067=ORIENTED_EDGE('',*,*,#1056,.F.);
#1068=DIRECTION('',(-1.,0.,0.));
#1069=VECTOR('',#1068,1.);
#1070=CARTESIAN_POINT('',(-15.25,1.06856936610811,-4.25));
#1071=LINE('',#1070,#1069);
#1072=EDGE_CURVE('E125',#1049,#994,#1071,.T.);
#1073=ORIENTED_EDGE('',*,*,#1072,.T.);
#1074=ORIENTED_EDGE('',*,*,#1008,.T.);
#1075=ORIENTED_EDGE('',*,*,#820,.T.);
#1076=EDGE_LOOP('',(#1067,#1073,#1074,#1075));
#1077=FACE_BOUND('',#1076,.T.);
#1078=ADVANCED_FACE('F261',(#1077),#1066,.F.);
#1079=CARTESIAN_POINT('',(0.,1.,0.));
#1080=DIRECTION('',(0.,1.,0.));
#1081=DIRECTION('',(0.,0.,1.));
#1082=AXIS2_PLACEMENT_3D('',#1079,#1080,#1081);
#1083=PLANE('',#1082);
#1084=CARTESIAN_POINT('',(-0.852127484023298,3.,30.4835993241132));
#1085=CARTESIAN_POINT('',(-0.852127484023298,0.999999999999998,30.4835993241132));
#1086=CARTESIAN_POINT('',(-0.77517688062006,1.,28.4850802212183));
#1087=CARTESIAN_POINT('',(-1.48441312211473,3.,30.4592585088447));
#1088=CARTESIAN_POINT('',(-1.48441312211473,0.999999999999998,30.4592585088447));
#1089=CARTESIAN_POINT('',(-1.35038823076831,1.,28.4629362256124));
#1090=CARTESIAN_POINT('',(-2.11552294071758,3.,30.4077956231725));
#1091=CARTESIAN_POINT('',(-2.11552294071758,1.,30.4077956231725));
#1092=CARTESIAN_POINT('',(-1.92460887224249,1.,28.4161196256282));
#1093=CARTESIAN_POINT('',(-3.37048370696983,3.,30.2514603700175));
#1094=CARTESIAN_POINT('',(-3.37048370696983,1.,30.2514603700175));
#1095=CARTESIAN_POINT('',(-3.0669382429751,1.,28.2738152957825));
#1096=CARTESIAN_POINT('',(-3.99433534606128,3.,30.1465931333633));
#1097=CARTESIAN_POINT('',(-3.99433534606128,1.,30.1465931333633));
#1098=CARTESIAN_POINT('',(-3.63504755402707,1.,28.178332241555));
#1099=CARTESIAN_POINT('',(-5.23009165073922,3.,29.885060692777));
#1100=CARTESIAN_POINT('',(-5.23009165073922,1.,29.885060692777));
#1101=CARTESIAN_POINT('',(-4.76117045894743,1.,27.9400020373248));
#1102=CARTESIAN_POINT('',(-5.84199721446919,3.,29.7283993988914));
#1103=CARTESIAN_POINT('',(-5.84199721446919,1.,29.7283993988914));
#1104=CARTESIAN_POINT('',(-5.31918481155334,1.,27.7971584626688));
#1105=CARTESIAN_POINT('',(-7.04969616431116,3.,29.3655467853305));
#1106=CARTESIAN_POINT('',(-7.04969616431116,1.,29.3655467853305));
#1107=CARTESIAN_POINT('',(-6.42153165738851,1.,27.4659585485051));
#1108=CARTESIAN_POINT('',(-7.64548899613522,3.,29.1593537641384));
#1109=CARTESIAN_POINT('',(-7.64548899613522,0.999999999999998,29.1593537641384));
#1110=CARTESIAN_POINT('',(-6.9658636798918,1.,27.2776006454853));
#1111=CARTESIAN_POINT('',(-8.81949779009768,3.,28.6993444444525));
#1112=CARTESIAN_POINT('',(-8.81949779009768,0.999999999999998,28.6993444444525));
#1113=CARTESIAN_POINT('',(-8.03963724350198,1.,26.8568659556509));
#1114=CARTESIAN_POINT('',(-9.39763688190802,3.,28.4453470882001));
#1115=CARTESIAN_POINT('',(-9.39763688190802,1.,28.4453470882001));
#1116=CARTESIAN_POINT('',(-8.56901307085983,1.,26.6243217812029));
#1117=CARTESIAN_POINT('',(-10.5307464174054,3.,27.8934440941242));
#1118=CARTESIAN_POINT('',(-10.5307464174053,1.,27.8934440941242));
#1119=CARTESIAN_POINT('',(-9.60780749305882,1.,26.1183565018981));
#1120=CARTESIAN_POINT('',(-11.0857170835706,3.,27.5955388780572));
#1121=CARTESIAN_POINT('',(-11.0857170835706,1.,27.5955388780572));
#1122=CARTESIAN_POINT('',(-10.1172262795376,1.,25.8449357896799));
#1123=CARTESIAN_POINT('',(-12.1699389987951,3.,26.9591917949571));
#1124=CARTESIAN_POINT('',(-12.1699389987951,1.,26.9591917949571));
#1125=CARTESIAN_POINT('',(-11.1137287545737,1.,25.2600723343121));
#1126=CARTESIAN_POINT('',(-12.6991895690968,3.,26.6207488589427));
#1127=CARTESIAN_POINT('',(-12.6991895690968,1.,26.6207488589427));
#1128=CARTESIAN_POINT('',(-11.6008118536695,1.,24.9486285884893));
#1129=CARTESIAN_POINT('',(-13.7301084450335,3.,25.9066678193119));
#1130=CARTESIAN_POINT('',(-13.7301084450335,1.,25.9066678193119));
#1131=CARTESIAN_POINT('',(-12.550828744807,1.,24.290585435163));
#1132=CARTESIAN_POINT('',(-14.2317662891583,3.,25.5310157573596));
#1133=CARTESIAN_POINT('',(-14.2317662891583,0.999999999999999,25.5310157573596));
#1134=CARTESIAN_POINT('',(-13.0137533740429,1.,23.943972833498));
#1135=CARTESIAN_POINT('',(-15.2546879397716,3.,24.7065809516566));
#1136=CARTESIAN_POINT('',(-15.2546879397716,0.999999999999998,24.7065809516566));
#1137=CARTESIAN_POINT('',(-13.9589115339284,1.,23.182211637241));
#1138=CARTESIAN_POINT('',(-15.7728649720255,3.,24.2542424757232));
#1139=CARTESIAN_POINT('',(-15.7728649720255,1.,24.2542424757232));
#1140=CARTESIAN_POINT('',(-14.438418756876,1.,22.763675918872));
#1141=CARTESIAN_POINT('',(-16.7723361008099,3.,23.3130969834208));
#1142=CARTESIAN_POINT('',(-16.7723361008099,1.,23.3130969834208));
#1143=CARTESIAN_POINT('',(-15.3645608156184,1.,21.8915815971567));
#1144=CARTESIAN_POINT('',(-17.2536164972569,3.,22.8242765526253));
#1145=CARTESIAN_POINT('',(-17.2536164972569,1.,22.8242765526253));
#1146=CARTESIAN_POINT('',(-15.8111834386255,1.,21.4380101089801));
#1147=CARTESIAN_POINT('',(-18.6404370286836,3.,21.3093664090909));
#1148=CARTESIAN_POINT('',(-18.6404370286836,0.999999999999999,21.3093664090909));
#1149=CARTESIAN_POINT('',(-17.0997840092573,1.,20.030383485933));
#1150=CARTESIAN_POINT('',(-19.4893788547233,3.,20.2344823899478));
#1151=CARTESIAN_POINT('',(-19.4893788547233,0.999999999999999,20.2344823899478));
#1152=CARTESIAN_POINT('',(-17.8908853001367,1.,19.0290971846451));
#1153=CARTESIAN_POINT('',(-21.1476564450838,3.,17.8158425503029));
#1154=CARTESIAN_POINT('',(-21.1476564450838,0.999999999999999,17.8158425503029));
#1155=CARTESIAN_POINT('',(-19.4393134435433,1.,16.7706669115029));
#1156=CARTESIAN_POINT('',(-21.9315814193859,3.,16.4560094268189));
#1157=CARTESIAN_POINT('',(-21.9315814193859,1.,16.4560094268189));
#1158=CARTESIAN_POINT('',(-20.1734346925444,1.,15.4977303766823));
#1159=CARTESIAN_POINT('',(-23.2927075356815,3.,13.6431180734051));
#1160=CARTESIAN_POINT('',(-23.2927075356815,1.,13.6431180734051));
#1161=CARTESIAN_POINT('',(-21.4502113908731,1.,12.8591655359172));
#1162=CARTESIAN_POINT('',(-23.8697904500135,3.,12.1900070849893));
#1163=CARTESIAN_POINT('',(-23.8697904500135,0.999999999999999,12.1900070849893));
#1164=CARTESIAN_POINT('',(-21.9927573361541,1.,11.4934847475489));
#1165=CARTESIAN_POINT('',(-24.891136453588,3.,8.99626356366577));
#1166=CARTESIAN_POINT('',(-24.891136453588,0.999999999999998,8.99626356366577));
#1167=CARTESIAN_POINT('',(-22.9539794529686,1.,8.48773290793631));
#1168=CARTESIAN_POINT('',(-25.3017130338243,3.,7.24558330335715));
#1169=CARTESIAN_POINT('',(-25.3017130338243,1.,7.24558330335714));
#1170=CARTESIAN_POINT('',(-23.3411378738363,1.,6.83758288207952));
#1171=CARTESIAN_POINT('',(-25.8530212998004,3.,3.70399488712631));
#1172=CARTESIAN_POINT('',(-25.8530212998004,1.,3.70399488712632));
#1173=CARTESIAN_POINT('',(-23.8611959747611,1.,3.49674706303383));
#1174=CARTESIAN_POINT('',(-25.9936128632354,3.,1.91306632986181));
#1175=CARTESIAN_POINT('',(-25.9936128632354,0.999999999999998,1.91306632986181));
#1176=CARTESIAN_POINT('',(-23.9939636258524,1.,1.80604068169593));
#1177=CARTESIAN_POINT('',(-26.0031903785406,3.,-0.863109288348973));
#1178=CARTESIAN_POINT('',(-26.0031903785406,0.999999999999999,-0.863109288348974));
#1179=CARTESIAN_POINT('',(-24.0030155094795,1.,-0.814822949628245));
#1180=CARTESIAN_POINT('',(-25.9658018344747,3.,-1.84895501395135));
#1181=CARTESIAN_POINT('',(-25.9658018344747,1.,-1.84895501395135));
#1182=CARTESIAN_POINT('',(-23.9677116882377,1.,-1.74552487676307));
#1183=CARTESIAN_POINT('',(-25.8093757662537,3.,-3.81499186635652));
#1184=CARTESIAN_POINT('',(-25.8093757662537,1.,-3.81499186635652));
#1185=CARTESIAN_POINT('',(-23.8200654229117,1.,-3.60118812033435));
#1186=CARTESIAN_POINT('',(-25.6903229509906,3.,-4.79518189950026));
#1187=CARTESIAN_POINT('',(-25.6903229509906,1.,-4.79518189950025));
#1188=CARTESIAN_POINT('',(-23.7077085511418,1.,-4.52614832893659));
#1189=CARTESIAN_POINT('',(-25.3701131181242,3.,-6.74375741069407));
#1190=CARTESIAN_POINT('',(-25.3701131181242,1.,-6.74375741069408));
#1191=CARTESIAN_POINT('',(-23.4056760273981,1.,-6.36411191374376));
#1192=CARTESIAN_POINT('',(-25.1688895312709,3.,-7.71213266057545));
#1193=CARTESIAN_POINT('',(-25.1688895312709,1.,-7.71213266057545));
#1194=CARTESIAN_POINT('',(-23.2159376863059,1.,-7.2771049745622));
#1195=CARTESIAN_POINT('',(-24.6839927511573,3.,-9.62902842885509));
#1196=CARTESIAN_POINT('',(-24.6839927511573,1.,-9.62902842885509));
#1197=CARTESIAN_POINT('',(-22.7590819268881,1.,-9.08314780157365));
#1198=CARTESIAN_POINT('',(-24.4003571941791,3.,-10.5775577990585));
#1199=CARTESIAN_POINT('',(-24.4003571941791,0.999999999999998,-10.5775577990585));
#1200=CARTESIAN_POINT('',(-22.4919998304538,1.,-9.97620647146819));
#1201=CARTESIAN_POINT('',(-23.7489948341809,3.,-12.4508599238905));
#1202=CARTESIAN_POINT('',(-23.7489948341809,0.999999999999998,-12.4508599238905));
#1203=CARTESIAN_POINT('',(-21.8792906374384,1.,-11.7383425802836));
#1204=CARTESIAN_POINT('',(-23.380993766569,3.,-13.3755440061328));
#1205=CARTESIAN_POINT('',(-23.380993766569,1.,-13.3755440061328));
#1206=CARTESIAN_POINT('',(-21.5334073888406,1.,-12.6073312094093));
#1207=CARTESIAN_POINT('',(-22.560890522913,3.,-15.1897186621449));
#1208=CARTESIAN_POINT('',(-22.560890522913,1.,-15.1897186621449));
#1209=CARTESIAN_POINT('',(-20.7635960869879,1.,-14.3102531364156));
#1210=CARTESIAN_POINT('',(-22.1087797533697,3.,-16.0792056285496));
#1211=CARTESIAN_POINT('',(-22.1087797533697,1.,-16.0792056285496));
#1212=CARTESIAN_POINT('',(-20.3396600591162,1.,-15.1441828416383));
#1213=CARTESIAN_POINT('',(-21.1210199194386,3.,-17.8122984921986));
#1214=CARTESIAN_POINT('',(-21.1210199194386,1.,-17.8122984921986));
#1215=CARTESIAN_POINT('',(-19.4148979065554,1.,-16.7667417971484));
#1216=CARTESIAN_POINT('',(-20.5854950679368,3.,-18.6559701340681));
#1217=CARTESIAN_POINT('',(-20.5854950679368,1.,-18.6559701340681));
#1218=CARTESIAN_POINT('',(-18.9141861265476,1.,-17.5554360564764));
#1219=CARTESIAN_POINT('',(-19.4308784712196,3.,-20.2882286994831));
#1220=CARTESIAN_POINT('',(-19.4308784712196,1.,-20.2882286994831));
#1221=CARTESIAN_POINT('',(-17.8365779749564,1.,-19.0788287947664));
#1222=CARTESIAN_POINT('',(-18.8118193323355,3.,-21.0768369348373));
#1223=CARTESIAN_POINT('',(-18.8118193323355,0.999999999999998,-21.0768369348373));
#1224=CARTESIAN_POINT('',(-17.2597113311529,1.,-19.8135481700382));
#1225=CARTESIAN_POINT('',(-17.6735773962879,3.,-22.3791400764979));
#1226=CARTESIAN_POINT('',(-17.6735773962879,0.999999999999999,-22.3791400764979));
#1227=CARTESIAN_POINT('',(-16.2011984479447,1.,-21.0246330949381));
#1228=CARTESIAN_POINT('',(-17.1738568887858,3.,-22.9087236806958));
#1229=CARTESIAN_POINT('',(-17.1738568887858,1.,-22.9087236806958));
#1230=CARTESIAN_POINT('',(-15.7370954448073,1.,-21.5164149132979));
#1231=CARTESIAN_POINT('',(-16.1323991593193,3.,-23.9279742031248));
#1232=CARTESIAN_POINT('',(-16.1323991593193,1.,-23.9279742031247));
#1233=CARTESIAN_POINT('',(-14.7713551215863,1.,-22.4615621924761));
#1234=CARTESIAN_POINT('',(-15.5906714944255,3.,-24.4176501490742));
#1235=CARTESIAN_POINT('',(-15.5906714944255,1.,-24.4176501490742));
#1236=CARTESIAN_POINT('',(-14.2697263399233,1.,-22.9149363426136));
#1237=CARTESIAN_POINT('',(-14.4669080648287,3.,-25.3518279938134));
#1238=CARTESIAN_POINT('',(-14.4669080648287,1.,-25.3518279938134));
#1239=CARTESIAN_POINT('',(-13.2308076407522,1.,-23.7785837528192));
#1240=CARTESIAN_POINT('',(-13.8848830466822,3.,-25.7963418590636));
#1241=CARTESIAN_POINT('',(-13.8848830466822,1.,-25.7963418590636));
#1242=CARTESIAN_POINT('',(-12.6935272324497,1.,-24.188868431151));
#1243=CARTESIAN_POINT('',(-12.6827326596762,3.,-26.6349270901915));
#1244=CARTESIAN_POINT('',(-12.6827326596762,1.,-26.6349270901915));
#1245=CARTESIAN_POINT('',(-11.5855841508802,1.,-24.9617377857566));
#1246=CARTESIAN_POINT('',(-12.0626061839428,3.,-27.0289969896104));
#1247=CARTESIAN_POINT('',(-12.0626061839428,0.999999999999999,-27.0289969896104));
#1248=CARTESIAN_POINT('',(-11.01492050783,1.,-25.3243210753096));
#1249=CARTESIAN_POINT('',(-10.783025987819,3.,-27.7637450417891));
#1250=CARTESIAN_POINT('',(-10.783025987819,0.999999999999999,-27.7637450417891));
#1251=CARTESIAN_POINT('',(-9.83924532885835,1.,-25.9994063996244));
#1252=CARTESIAN_POINT('',(-10.1233251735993,3.,-28.1040259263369));
#1253=CARTESIAN_POINT('',(-10.1233251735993,1.,-28.1040259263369));
#1254=CARTESIAN_POINT('',(-9.2340194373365,1.,-26.3115361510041));
#1255=CARTESIAN_POINT('',(-8.77298140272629,3.,-28.7223406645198));
#1256=CARTESIAN_POINT('',(-8.77298140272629,1.,-28.7223406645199));
#1257=CARTESIAN_POINT('',(-7.99697818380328,1.,-26.8779710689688));
#1258=CARTESIAN_POINT('',(-8.08233704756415,3.,-29.0003717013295));
#1259=CARTESIAN_POINT('',(-8.08233704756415,1.,-29.0003717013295));
#1260=CARTESIAN_POINT('',(-7.36516162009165,1.,-27.1322736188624));
#1261=CARTESIAN_POINT('',(-6.67645318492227,3.,-29.4888994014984));
#1262=CARTESIAN_POINT('',(-6.67645318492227,1.,-29.4888994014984));
#1263=CARTESIAN_POINT('',(-6.08062209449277,1.,-27.5786362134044));
#1264=CARTESIAN_POINT('',(-5.96124058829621,3.,-29.6994675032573));
#1265=CARTESIAN_POINT('',(-5.9612405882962,1.,-29.6994675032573));
#1266=CARTESIAN_POINT('',(-5.42792205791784,1.,-27.7707621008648));
#1267=CARTESIAN_POINT('',(-4.51225347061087,3.,-30.049274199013));
#1268=CARTESIAN_POINT('',(-4.51225347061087,1.,-30.049274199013));
#1269=CARTESIAN_POINT('',(-4.10682694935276,1.,-28.0896949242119));
#1270=CARTESIAN_POINT('',(-3.77848413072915,3.,-30.1885324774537));
#1271=CARTESIAN_POINT('',(-3.77848413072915,0.999999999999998,-30.1885324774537));
#1272=CARTESIAN_POINT('',(-3.43843626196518,1.,-28.2165198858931));
#1273=CARTESIAN_POINT('',(-2.49418411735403,3.,-30.3660438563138));
#1274=CARTESIAN_POINT('',(-2.49418411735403,0.999999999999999,-30.3660438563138));
#1275=CARTESIAN_POINT('',(-2.26923331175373,1.,-28.3781218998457));
#1276=CARTESIAN_POINT('',(-1.94612685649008,3.,-30.4212167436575));
#1277=CARTESIAN_POINT('',(-1.94612685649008,1.,-30.4212167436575));
#1278=CARTESIAN_POINT('',(-1.77049914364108,1.,-28.4283240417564));
#1279=CARTESIAN_POINT('',(-0.847230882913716,3.,-30.4906231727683));
#1280=CARTESIAN_POINT('',(-0.847230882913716,1.,-30.4906231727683));
#1281=CARTESIAN_POINT('',(-0.770694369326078,1.,-28.4914721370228));
#1282=CARTESIAN_POINT('',(-0.296392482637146,3.,-30.5048612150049));
#1283=CARTESIAN_POINT('',(-0.296392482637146,1.,-30.5048612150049));
#1284=CARTESIAN_POINT('',(-0.269624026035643,1.,-28.5044221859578));
#1285=CARTESIAN_POINT('',(0.804659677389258,3.,-30.4922220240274));
#1286=CARTESIAN_POINT('',(0.804659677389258,1.,-30.4922220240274));
#1287=CARTESIAN_POINT('',(0.731984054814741,1.,-28.4929244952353));
#1288=CARTESIAN_POINT('',(1.3548735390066,3.,-30.465352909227));
#1289=CARTESIAN_POINT('',(1.3548735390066,1.,-30.465352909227));
#1290=CARTESIAN_POINT('',(1.23252187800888,1.,-28.4684841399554));
#1291=CARTESIAN_POINT('',(2.45155714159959,3.,-30.3708436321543));
#1292=CARTESIAN_POINT('',(2.45155714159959,1.,-30.3708436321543));
#1293=CARTESIAN_POINT('',(2.23045374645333,1.,-28.3824848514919));
#1294=CARTESIAN_POINT('',(2.99802627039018,3.,-30.3031969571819));
#1295=CARTESIAN_POINT('',(2.99802627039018,0.999999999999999,-30.3031969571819));
#1296=CARTESIAN_POINT('',(2.72784727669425,1.,-28.3209199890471));
#1297=CARTESIAN_POINT('',(4.20471419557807,3.,-30.1084085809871));
#1298=CARTESIAN_POINT('',(4.20471419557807,0.999999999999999,-30.1084085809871));
#1299=CARTESIAN_POINT('',(3.82669359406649,1.,-28.1435403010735));
#1300=CARTESIAN_POINT('',(4.86322638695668,3.,-29.9713867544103));
#1301=CARTESIAN_POINT('',(4.86322638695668,1.,-29.9713867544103));
#1302=CARTESIAN_POINT('',(4.42670966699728,1.,-28.0187105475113));
#1303=CARTESIAN_POINT('',(6.16442847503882,3.,-29.6398674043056));
#1304=CARTESIAN_POINT('',(6.16442847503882,1.,-29.6398674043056));
#1305=CARTESIAN_POINT('',(5.6133483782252,1.,-27.7163789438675));
#1306=CARTESIAN_POINT('',(6.8071159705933,3.,-29.4453612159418));
#1307=CARTESIAN_POINT('',(6.80711597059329,1.,-29.4453612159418));
#1308=CARTESIAN_POINT('',(6.19996898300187,1.,-27.5388691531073));
#1309=CARTESIAN_POINT('',(8.0722777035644,3.,-29.0018130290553));
#1310=CARTESIAN_POINT('',(8.0722777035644,1.,-29.0018130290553));
#1311=CARTESIAN_POINT('',(7.35601252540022,1.,-27.1335759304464));
#1312=CARTESIAN_POINT('',(8.69473731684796,3.,-28.7527325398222));
#1313=CARTESIAN_POINT('',(8.69473731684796,1.,-28.7527325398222));
#1314=CARTESIAN_POINT('',(7.92542300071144,1.,-26.9057570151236));
#1315=CARTESIAN_POINT('',(9.91486759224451,3.,-28.2037696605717));
#1316=CARTESIAN_POINT('',(9.91486759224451,1.,-28.2037696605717));
#1317=CARTESIAN_POINT('',(9.04295507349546,1.,-26.4029548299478));
#1318=CARTESIAN_POINT('',(10.5125389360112,3.,-27.9038886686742));
#1319=CARTESIAN_POINT('',(10.5125389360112,0.999999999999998,-27.9038886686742));
#1320=CARTESIAN_POINT('',(9.59107725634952,1.,-26.1279728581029));
#1321=CARTESIAN_POINT('',(11.6768482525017,3.,-27.2589289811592));
#1322=CARTESIAN_POINT('',(11.6768482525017,0.999999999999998,-27.2589289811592));
#1323=CARTESIAN_POINT('',(10.6602898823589,1.,-25.5356908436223));
#1324=CARTESIAN_POINT('',(12.2436276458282,3.,-26.9140860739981));
#1325=CARTESIAN_POINT('',(12.2436276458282,1.,-26.9140860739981));
#1326=CARTESIAN_POINT('',(11.1815028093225,1.,-25.2186114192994));
#1327=CARTESIAN_POINT('',(13.3470190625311,3.,-26.1819583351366));
#1328=CARTESIAN_POINT('',(13.3470190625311,1.,-26.1819583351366));
#1329=CARTESIAN_POINT('',(12.1975771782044,1.,-24.5444204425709));
#1330=CARTESIAN_POINT('',(13.8836200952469,3.,-25.794658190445));
#1331=CARTESIAN_POINT('',(13.8836200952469,1.,-25.794658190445));
#1332=CARTESIAN_POINT('',(12.6924290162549,1.,-24.1872944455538));
#1333=CARTESIAN_POINT('',(14.9243041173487,3.,-24.981901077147));
#1334=CARTESIAN_POINT('',(14.9243041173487,1.,-24.981901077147));
#1335=CARTESIAN_POINT('',(13.6534536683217,1.,-23.4367497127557));
#1336=CARTESIAN_POINT('',(15.4283990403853,3.,-24.5564582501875));
#1337=CARTESIAN_POINT('',(15.4283990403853,1.,-24.5564582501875));
#1338=CARTESIAN_POINT('',(14.119637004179,1.,-23.0433444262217));
#1339=CARTESIAN_POINT('',(16.4030550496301,3.,-23.6710547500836));
#1340=CARTESIAN_POINT('',(16.4030550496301,1.,-23.6710547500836));
#1341=CARTESIAN_POINT('',(15.0221821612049,1.,-22.2234483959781));
#1342=CARTESIAN_POINT('',(16.8736033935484,3.,-23.2110810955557));
#1343=CARTESIAN_POINT('',(16.8736033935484,0.999999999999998,-23.2110810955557));
#1344=CARTESIAN_POINT('',(15.4585326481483,1.,-21.7969452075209));
#1345=CARTESIAN_POINT('',(17.8280299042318,3.,-22.2100796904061));
#1346=CARTESIAN_POINT('',(17.8280299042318,0.999999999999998,-22.2100796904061));
#1347=CARTESIAN_POINT('',(16.3447026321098,1.,-20.8675302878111));
#1348=CARTESIAN_POINT('',(18.3080442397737,3.,-21.6656265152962));
#1349=CARTESIAN_POINT('',(18.3080442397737,1.,-21.6656265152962));
#1350=CARTESIAN_POINT('',(16.7910564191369,1.,-20.361309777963));
#1351=CARTESIAN_POINT('',(19.2249068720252,3.,-20.543820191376));
#1352=CARTESIAN_POINT('',(19.2249068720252,1.,-20.543820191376));
#1353=CARTESIAN_POINT('',(17.6447095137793,1.,-19.3168439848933));
#1354=CARTESIAN_POINT('',(19.6617392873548,3.,-19.9664550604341));
#1355=CARTESIAN_POINT('',(19.6617392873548,1.,-19.9664550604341));
#1356=CARTESIAN_POINT('',(18.0519944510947,1.,-18.7785870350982));
#1357=CARTESIAN_POINT('',(20.9066563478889,3.,-18.1915365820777));
#1358=CARTESIAN_POINT('',(20.9066563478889,0.999999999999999,-18.1915365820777));
#1359=CARTESIAN_POINT('',(19.2140338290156,1.,-17.1218185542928));
#1360=CARTESIAN_POINT('',(21.6495131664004,3.,-16.9507853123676));
#1361=CARTESIAN_POINT('',(21.6495131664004,0.999999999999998,-16.9507853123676));
#1362=CARTESIAN_POINT('',(19.9093004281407,1.,-15.9609614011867));
#1363=CARTESIAN_POINT('',(23.0639150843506,3.,-14.1814101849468));
#1364=CARTESIAN_POINT('',(23.0639150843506,0.999999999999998,-14.1814101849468));
#1365=CARTESIAN_POINT('',(21.2352561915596,1.,-13.3647550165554));
#1366=CARTESIAN_POINT('',(23.7051156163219,3.,-12.6384608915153));
#1367=CARTESIAN_POINT('',(23.7051156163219,1.,-12.6384608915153));
#1368=CARTESIAN_POINT('',(21.8378907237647,1.,-11.9151791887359));
#1369=CARTESIAN_POINT('',(24.7534588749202,3.,-9.47995182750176));
#1370=CARTESIAN_POINT('',(24.7534588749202,1.,-9.47995182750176));
#1371=CARTESIAN_POINT('',(22.8243147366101,1.,-8.94324060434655));
#1372=CARTESIAN_POINT('',(25.1604715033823,3.,-7.86435223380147));
#1373=CARTESIAN_POINT('',(25.1604715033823,0.999999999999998,-7.86435223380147));
#1374=CARTESIAN_POINT('',(23.2079825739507,1.,-7.42083789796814));
#1375=CARTESIAN_POINT('',(25.7820877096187,3.,-4.37217195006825));
#1376=CARTESIAN_POINT('',(25.7820877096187,0.999999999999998,-4.37217195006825));
#1377=CARTESIAN_POINT('',(23.7942215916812,1.,-4.12737648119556));
#1378=CARTESIAN_POINT('',(25.9630035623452,3.,-2.48997524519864));
#1379=CARTESIAN_POINT('',(25.9630035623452,1.,-2.48997524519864));
#1380=CARTESIAN_POINT('',(23.9650748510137,1.,-2.35065454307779));
#1381=CARTESIAN_POINT('',(26.0267757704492,3.,1.28108716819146));
#1382=CARTESIAN_POINT('',(26.0267757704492,1.,1.28108716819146));
#1383=CARTESIAN_POINT('',(24.0252763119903,1.,1.20940015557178));
#1384=CARTESIAN_POINT('',(25.9094195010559,3.,3.16995667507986));
#1385=CARTESIAN_POINT('',(25.9094195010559,0.999999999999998,3.16995667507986));
#1386=CARTESIAN_POINT('',(23.9144236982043,1.,2.99273672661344));
#1387=CARTESIAN_POINT('',(25.5008212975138,3.,6.03023401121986));
#1388=CARTESIAN_POINT('',(25.5008212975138,0.999999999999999,6.03023401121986));
#1389=CARTESIAN_POINT('',(23.5289517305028,1.,5.69121456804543));
#1390=CARTESIAN_POINT('',(25.3167636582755,3.,7.01700030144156));
#1391=CARTESIAN_POINT('',(25.3167636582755,1.,7.01700030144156));
#1392=CARTESIAN_POINT('',(23.3553507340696,1.,6.62178968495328));
#1393=CARTESIAN_POINT('',(24.8636129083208,3.,8.97254972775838));
#1394=CARTESIAN_POINT('',(24.8636129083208,1.,8.97254972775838));
#1395=CARTESIAN_POINT('',(22.9282718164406,1.,8.46481619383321));
#1396=CARTESIAN_POINT('',(24.5945106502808,3.,9.94133091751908));
#1397=CARTESIAN_POINT('',(24.5945106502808,1.,9.94133091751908));
#1398=CARTESIAN_POINT('',(22.6747853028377,1.,9.37726562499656));
#1399=CARTESIAN_POINT('',(23.9710636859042,3.,11.8519456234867));
#1400=CARTESIAN_POINT('',(23.9710636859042,1.,11.8519456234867));
#1401=CARTESIAN_POINT('',(22.0881049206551,1.,11.1752073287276));
#1402=CARTESIAN_POINT('',(23.6168001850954,3.,12.793803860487));
#1403=CARTESIAN_POINT('',(23.6168001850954,1.,12.793803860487));
#1404=CARTESIAN_POINT('',(21.7549869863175,1.,12.0607243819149));
#1405=CARTESIAN_POINT('',(22.8222425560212,3.,14.6434715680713));
#1406=CARTESIAN_POINT('',(22.8222425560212,1.,14.6434715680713));
#1407=CARTESIAN_POINT('',(21.0087986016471,1.,13.7977905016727));
#1408=CARTESIAN_POINT('',(22.3819340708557,3.,15.5512753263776));
#1409=CARTESIAN_POINT('',(22.3819340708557,0.999999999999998,15.5512753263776));
#1410=CARTESIAN_POINT('',(20.5957148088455,1.,14.6493338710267));
#1411=CARTESIAN_POINT('',(21.5127172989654,3.,17.1442502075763));
#1412=CARTESIAN_POINT('',(21.5127172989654,0.999999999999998,17.1442502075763));
#1413=CARTESIAN_POINT('',(19.7814882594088,1.,16.1415331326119));
#1414=CARTESIAN_POINT('',(21.0994270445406,3.,17.8373904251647));
#1415=CARTESIAN_POINT('',(21.0994270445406,1.,17.8373904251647));
#1416=CARTESIAN_POINT('',(19.3947465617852,1.,16.79007824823));
#1417=CARTESIAN_POINT('',(20.2180515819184,3.,19.1904094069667));
#1418=CARTESIAN_POINT('',(20.2180515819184,1.,19.1904094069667));
#1419=CARTESIAN_POINT('',(18.5711135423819,1.,18.0544549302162));
#1420=CARTESIAN_POINT('',(19.749976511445,3.,19.8502942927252));
#1421=CARTESIAN_POINT('',(19.749976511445,1.,19.8502942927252));
#1422=CARTESIAN_POINT('',(18.1342314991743,1.,18.6702925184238));
#1423=CARTESIAN_POINT('',(18.7593206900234,3.,21.1311634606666));
#1424=CARTESIAN_POINT('',(18.7593206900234,1.,21.1311634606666));
#1425=CARTESIAN_POINT('',(17.2109999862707,1.,19.8639856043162));
#1426=CARTESIAN_POINT('',(18.2367286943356,3.,21.7521396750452));
#1427=CARTESIAN_POINT('',(18.2367286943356,1.,21.7521396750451));
#1428=CARTESIAN_POINT('',(16.7246403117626,1.,20.4418332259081));
#1429=CARTESIAN_POINT('',(17.1383629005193,3.,22.9483024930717));
#1430=CARTESIAN_POINT('',(17.1383629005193,1.,22.9483024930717));
#1431=CARTESIAN_POINT('',(15.7041215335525,1.,21.5532178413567));
#1432=CARTESIAN_POINT('',(16.56261692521,3.,23.5235127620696));
#1433=CARTESIAN_POINT('',(16.56261692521,0.999999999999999,23.5235127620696));
#1434=CARTESIAN_POINT('',(15.1699874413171,1.,22.0867777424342));
#1435=CARTESIAN_POINT('',(15.3540947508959,3.,24.626383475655));
#1436=CARTESIAN_POINT('',(15.3540947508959,0.999999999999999,24.626383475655));
#1437=CARTESIAN_POINT('',(14.0507846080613,1.,23.1081379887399));
#1438=CARTESIAN_POINT('',(14.7208588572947,3.,25.1535779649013));
#1439=CARTESIAN_POINT('',(14.7208588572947,1.,25.1535779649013));
#1440=CARTESIAN_POINT('',(13.4653068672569,1.,23.5954914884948));
#1441=CARTESIAN_POINT('',(13.4049605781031,3.,26.1466892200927));
#1442=CARTESIAN_POINT('',(13.4049605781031,1.,26.1466892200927));
#1443=CARTESIAN_POINT('',(12.2508748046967,1.,24.5120267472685));
#1444=CARTESIAN_POINT('',(12.7223274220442,3.,26.612641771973));
#1445=CARTESIAN_POINT('',(12.7223274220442,1.,26.612641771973));
#1446=CARTESIAN_POINT('',(11.6219462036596,1.,24.9412424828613));
#1447=CARTESIAN_POINT('',(11.3118783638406,3.,27.4755071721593));
#1448=CARTESIAN_POINT('',(11.3118783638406,1.,27.4755071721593));
#1449=CARTESIAN_POINT('',(10.3247943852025,1.,25.7347972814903));
#1450=CARTESIAN_POINT('',(10.5840883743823,3.,27.872459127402));
#1451=CARTESIAN_POINT('',(10.5840883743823,1.,27.872459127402));
#1452=CARTESIAN_POINT('',(9.65659371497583,1.,26.0991730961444));
#1453=CARTESIAN_POINT('',(9.08881917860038,3.,28.589834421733));
#1454=CARTESIAN_POINT('',(9.08881917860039,1.,28.589834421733));
#1455=CARTESIAN_POINT('',(8.28603730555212,1.,26.756717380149));
#1456=CARTESIAN_POINT('',(8.3213486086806,3.,28.9102743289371));
#1457=CARTESIAN_POINT('',(8.3213486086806,0.999999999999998,28.9102743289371));
#1458=CARTESIAN_POINT('',(7.58368900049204,1.,27.0499012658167));
#1459=CARTESIAN_POINT('',(6.86907257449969,3.,29.4267795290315));
#1460=CARTESIAN_POINT('',(6.8690725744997,0.999999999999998,29.4267795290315));
#1461=CARTESIAN_POINT('',(6.25651667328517,1.,27.5219132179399));
#1462=CARTESIAN_POINT('',(6.18861490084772,3.,29.63418546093));
#1463=CARTESIAN_POINT('',(6.18861490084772,1.,29.6341854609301));
#1464=CARTESIAN_POINT('',(5.63539721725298,1.,27.7111993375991));
#1465=CARTESIAN_POINT('',(4.80994534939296,3.,29.984471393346));
#1466=CARTESIAN_POINT('',(4.80994534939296,1.,29.984471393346));
#1467=CARTESIAN_POINT('',(4.37812799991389,1.,28.0306410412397));
#1468=CARTESIAN_POINT('',(4.11173534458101,3.,30.1273581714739));
#1469=CARTESIAN_POINT('',(4.11173534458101,1.,30.1273581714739));
#1470=CARTESIAN_POINT('',(3.74197982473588,1.,28.1608028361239));
#1471=CARTESIAN_POINT('',(2.70448121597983,3.,30.3458195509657));
#1472=CARTESIAN_POINT('',(2.70448121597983,1.,30.3458195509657));
#1473=CARTESIAN_POINT('',(2.46059022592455,1.,28.3597253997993));
#1474=CARTESIAN_POINT('',(1.99544484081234,3.,30.4214401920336));
#1475=CARTESIAN_POINT('',(1.99544484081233,1.,30.4214401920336));
#1476=CARTESIAN_POINT('',(1.81535532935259,1.,28.4285281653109));
#1477=CARTESIAN_POINT('',(0.573066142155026,3.,30.5040294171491));
#1478=CARTESIAN_POINT('',(0.573066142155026,1.,30.5040294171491));
#1479=CARTESIAN_POINT('',(0.521269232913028,1.,28.5036685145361));
#1480=CARTESIAN_POINT('',(-0.140275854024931,3.,30.5110031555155));
#1481=CARTESIAN_POINT('',(-0.14027585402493,0.999999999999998,30.5110031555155));
#1482=CARTESIAN_POINT('',(-0.127581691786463,1.,28.5100107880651));
#1483=CARTESIAN_POINT('',(-0.852127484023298,3.,30.4835993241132));
#1484=CARTESIAN_POINT('',(-0.852127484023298,0.999999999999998,30.4835993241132));
#1485=CARTESIAN_POINT('',(-0.77517688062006,1.,28.4850802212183));
#1486=(BOUNDED_SURFACE() B_SPLINE_SURFACE(3,2,((#1084,#1085,#1086),(#1087,#1088,#1089),(#1090,
#1091,#1092),(#1093,#1094,#1095),(#1096,#1097,#1098),(#1099,#1100,#1101),(#1102,#1103,#1104),
(#1105,#1106,#1107),(#1108,#1109,#1110),(#1111,#1112,#1113),(#1114,#1115,#1116),(#1117,#1118,
#1119),(#1120,#1121,#1122),(#1123,#1124,#1125),(#1126,#1127,#1128),(#1129,#1130,#1131),(#1132,
#1133,#1134),(#1135,#1136,#1137),(#1138,#1139,#1140),(#1141,#1142,#1143),(#1144,#1145,#1146),
(#1147,#1148,#1149),(#1150,#1151,#1152),(#1153,#1154,#1155),(#1156,#1157,#1158),(#1159,#1160,
#1161),(#1162,#1163,#1164),(#1165,#1166,#1167),(#1168,#1169,#1170),(#1171,#1172,#1173),(#1174,
#1175,#1176),(#1177,#1178,#1179),(#1180,#1181,#1182),(#1183,#1184,#1185),(#1186,#1187,#1188),
(#1189,#1190,#1191),(#1192,#1193,#1194),(#1195,#1196,#1197),(#1198,#1199,#1200),(#1201,#1202,
#1203),(#1204,#1205,#1206),(#1207,#1208,#1209),(#1210,#1211,#1212),(#1213,#1214,#1215),(#1216,
#1217,#1218),(#1219,#1220,#1221),(#1222,#1223,#1224),(#1225,#1226,#1227),(#1228,#1229,#1230),
(#1231,#1232,#1233),(#1234,#1235,#1236),(#1237,#1238,#1239),(#1240,#1241,#1242),(#1243,#1244,
#1245),(#1246,#1247,#1248),(#1249,#1250,#1251),(#1252,#1253,#1254),(#1255,#1256,#1257),(#1258,
#1259,#1260),(#1261,#1262,#1263),(#1264,#1265,#1266),(#1267,#1268,#1269),(#1270,#1271,#1272),
(#1273,#1274,#1275),(#1276,#1277,#1278),(#1279,#1280,#1281),(#1282,#1283,#1284),(#1285,#1286,
#1287),(#1288,#1289,#1290),(#1291,#1292,#1293),(#1294,#1295,#1296),(#1297,#1298,#1299),(#1300,
#1301,#1302),(#1303,#1304,#1305),(#1306,#1307,#1308),(#1309,#1310,#1311),(#1312,#1313,#1314),
(#1315,#1316,#1317),(#1318,#1319,#1320),(#1321,#1322,#1323),(#1324,#1325,#1326),(#1327,#1328,
#1329),(#1330,#1331,#1332),(#1333,#1334,#1335),(#1336,#1337,#1338),(#1339,#1340,#1341),(#1342,
#1343,#1344),(#1345,#1346,#1347),(#1348,#1349,#1350),(#1351,#1352,#1353),(#1354,#1355,#1356),
(#1357,#1358,#1359),(#1360,#1361,#1362),(#1363,#1364,#1365),(#1366,#1367,#1368),(#1369,#1370,
#1371),(#1372,#1373,#1374),(#1375,#1376,#1377),(#1378,#1379,#1380),(#1381,#1382,#1383),(#1384,
#1385,#1386),(#1387,#1388,#1389),(#1390,#1391,#1392),(#1393,#1394,#1395),(#1396,#1397,#1398),
(#1399,#1400,#1401),(#1402,#1403,#1404),(#1405,#1406,#1407),(#1408,#1409,#1410),(#1411,#1412,
#1413),(#1414,#1415,#1416),(#1417,#1418,#1419),(#1420,#1421,#1422),(#1423,#1424,#1425),(#1426,
#1427,#1428),(#1429,#1430,#1431),(#1432,#1433,#1434),(#1435,#1436,#1437),(#1438,#1439,#1440),
(#1441,#1442,#1443),(#1444,#1445,#1446),(#1447,#1448,#1449),(#1450,#1451,#1452),(#1453,#1454,
#1455),(#1456,#1457,#1458),(#1459,#1460,#1461),(#1462,#1463,#1464),(#1465,#1466,#1467),(#1468,
#1469,#1470),(#1471,#1472,#1473),(#1474,#1475,#1476),(#1477,#1478,#1479),(#1480,#1481,#1482),
(#1483,#1484,#1485)),.UNSPECIFIED.,.T.,.F.,.F.) B_SPLINE_SURFACE_WITH_KNOTS((4,2,2,2,2,2,2,2,2,
2,2,2,2,2,2,2,2,2,2,2,2,2,2,2,2,2,2,2,2,2,2,2,2,2,2,2,2,2,2,2,2,2,2,2,2,2,2,2,2,2,2,2,2,2,2,2,2,
2,2,2,2,2,2,2,2,2,4),(3,3),(0.,1.72631974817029,3.45247367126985,5.17849731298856,
6.90458025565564,8.63733728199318,10.3700776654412,12.1028637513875,13.8363023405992,
15.7437444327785,17.6518913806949,21.4666870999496,25.8584642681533,30.2527477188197,
35.317311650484,40.3845033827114,43.1758990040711,45.9678174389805,48.7620022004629,
51.5549129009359,54.3570351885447,57.1594439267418,59.9577187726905,62.7549044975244,
64.78156437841,66.8077645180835,68.8334263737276,70.8591471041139,72.8991928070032,
74.9393308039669,76.9773012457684,79.0147088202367,80.5171731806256,82.0194723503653,
83.5214748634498,85.0237173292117,86.8597702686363,88.6961001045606,90.5337292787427,
92.3713078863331,94.1996108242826,96.0285753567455,97.8568645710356,99.6858445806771,
101.708478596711,103.731853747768,107.777184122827,112.468687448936,117.16279453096,
122.495176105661,127.831359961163,130.668292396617,133.505530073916,136.340072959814,
139.175089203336,141.438207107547,143.700906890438,145.964074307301,148.226063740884,
150.508075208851,152.788747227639,155.068122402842,157.347003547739,159.292243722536,
161.237279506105,163.180983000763,165.124540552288),(0.,1.),
.UNSPECIFIED.) GEOMETRIC_REPRESENTATION_ITEM() RATIONAL_B_SPLINE_SURFACE(((1.,0.707106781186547,
1.),(1.,0.707106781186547,1.),(1.,0.707106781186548,1.),(1.,0.707106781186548,1.),(1.,
0.707106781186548,1.),(1.,0.707106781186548,1.),(1.,0.707106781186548,1.),(1.,0.707106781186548,
1.),(1.,0.707106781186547,1.),(1.,0.707106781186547,1.),(1.,0.707106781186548,1.),(1.,
0.707106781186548,1.),(1.,0.707106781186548,1.),(1.,0.707106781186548,1.),(1.,0.707106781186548,
1.),(1.,0.707106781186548,1.),(1.,0.707106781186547,1.),(1.,0.707106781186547,1.),(1.,
0.707106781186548,1.),(1.,0.707106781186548,1.),(1.,0.707106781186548,1.),(1.,0.707106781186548,
1.),(1.,0.707106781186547,1.),(1.,0.707106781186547,1.),(1.,0.707106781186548,1.),(1.,
0.707106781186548,1.),(1.,0.707106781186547,1.),(1.,0.707106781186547,1.),(1.,0.707106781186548,
1.),(1.,0.707106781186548,1.),(1.,0.707106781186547,1.),(1.,0.707106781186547,1.),(1.,
0.707106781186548,1.),(1.,0.707106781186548,1.),(1.,0.707106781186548,1.),(1.,0.707106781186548,
1.),(1.,0.707106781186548,1.),(1.,0.707106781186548,1.),(1.,0.707106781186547,1.),(1.,
0.707106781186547,1.),(1.,0.707106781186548,1.),(1.,0.707106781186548,1.),(1.,0.707106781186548,
1.),(1.,0.707106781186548,1.),(1.,0.707106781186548,1.),(1.,0.707106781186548,1.),(1.,
0.707106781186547,1.),(1.,0.707106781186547,1.),(1.,0.707106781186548,1.),(1.,0.707106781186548,
1.),(1.,0.707106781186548,1.),(1.,0.707106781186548,1.),(1.,0.707106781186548,1.),(1.,
0.707106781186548,1.),(1.,0.707106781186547,1.),(1.,0.707106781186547,1.),(1.,0.707106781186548,
1.),(1.,0.707106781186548,1.),(1.,0.707106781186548,1.),(1.,0.707106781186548,1.),(1.,
0.707106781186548,1.),(1.,0.707106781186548,1.),(1.,0.707106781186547,1.),(1.,0.707106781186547,
1.),(1.,0.707106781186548,1.),(1.,0.707106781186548,1.),(1.,0.707106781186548,1.),(1.,
0.707106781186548,1.),(1.,0.707106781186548,1.),(1.,0.707106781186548,1.),(1.,0.707106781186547,
1.),(1.,0.707106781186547,1.),(1.,0.707106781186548,1.),(1.,0.707106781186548,1.),(1.,
0.707106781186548,1.),(1.,0.707106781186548,1.),(1.,0.707106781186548,1.),(1.,0.707106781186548,
1.),(1.,0.707106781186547,1.),(1.,0.707106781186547,1.),(1.,0.707106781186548,1.),(1.,
0.707106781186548,1.),(1.,0.707106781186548,1.),(1.,0.707106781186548,1.),(1.,0.707106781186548,
1.),(1.,0.707106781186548,1.),(1.,0.707106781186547,1.),(1.,0.707106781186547,1.),(1.,
0.707106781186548,1.),(1.,0.707106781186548,1.),(1.,0.707106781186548,1.),(1.,0.707106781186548,
1.),(1.,0.707106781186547,1.),(1.,0.707106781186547,1.),(1.,0.707106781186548,1.),(1.,
0.707106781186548,1.),(1.,0.707106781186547,1.),(1.,0.707106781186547,1.),(1.,0.707106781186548,
1.),(1.,0.707106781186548,1.),(1.,0.707106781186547,1.),(1.,0.707106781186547,1.),(1.,
0.707106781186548,1.),(1.,0.707106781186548,1.),(1.,0.707106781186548,1.),(1.,0.707106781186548,
1.),(1.,0.707106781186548,1.),(1.,0.707106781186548,1.),(1.,0.707106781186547,1.),(1.,
0.707106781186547,1.),(1.,0.707106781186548,1.),(1.,0.707106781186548,1.),(1.,0.707106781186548,
1.),(1.,0.707106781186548,1.),(1.,0.707106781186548,1.),(1.,0.707106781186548,1.),(1.,
0.707106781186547,1.),(1.,0.707106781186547,1.),(1.,0.707106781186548,1.),(1.,0.707106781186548,
1.),(1.,0.707106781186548,1.),(1.,0.707106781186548,1.),(1.,0.707106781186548,1.),(1.,
0.707106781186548,1.),(1.,0.707106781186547,1.),(1.,0.707106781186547,1.),(1.,0.707106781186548,
1.),(1.,0.707106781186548,1.),(1.,0.707106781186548,1.),(1.,0.707106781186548,1.),(1.,
0.707106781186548,1.),(1.,0.707106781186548,1.),(1.,0.707106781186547,1.),(1.,0.707106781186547,1.))) REPRESENTATION_ITEM('') SURFACE());
#1487=CARTESIAN_POINT('',(-0.77517688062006,1.,28.4850802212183));
#1488=CARTESIAN_POINT('',(-0.127581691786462,1.,28.5100107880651));
#1489=CARTESIAN_POINT('',(0.521269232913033,1.,28.5036685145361));
#1490=CARTESIAN_POINT('',(1.8153553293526,1.,28.4285281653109));
#1491=CARTESIAN_POINT('',(2.46059022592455,1.,28.3597253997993));
#1492=CARTESIAN_POINT('',(3.74197982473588,1.,28.1608028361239));
#1493=CARTESIAN_POINT('',(4.3781279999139,1.,28.0306410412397));
#1494=CARTESIAN_POINT('',(5.63539721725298,1.,27.7111993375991));
#1495=CARTESIAN_POINT('',(6.25651667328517,1.,27.5219132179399));
#1496=CARTESIAN_POINT('',(7.58368900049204,1.,27.0499012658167));
#1497=CARTESIAN_POINT('',(8.28603730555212,1.,26.756717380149));
#1498=CARTESIAN_POINT('',(9.65659371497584,1.,26.0991730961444));
#1499=CARTESIAN_POINT('',(10.3247943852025,1.,25.7347972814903));
#1500=CARTESIAN_POINT('',(11.6219462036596,1.,24.9412424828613));
#1501=CARTESIAN_POINT('',(12.2508748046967,1.,24.5120267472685));
#1502=CARTESIAN_POINT('',(13.4653068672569,1.,23.5954914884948));
#1503=CARTESIAN_POINT('',(14.0507846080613,1.,23.1081379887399));
#1504=CARTESIAN_POINT('',(15.1699874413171,1.,22.0867777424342));
#1505=CARTESIAN_POINT('',(15.7041215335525,1.,21.5532178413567));
#1506=CARTESIAN_POINT('',(16.7246403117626,1.,20.4418332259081));
#1507=CARTESIAN_POINT('',(17.2109999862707,1.,19.8639856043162));
#1508=CARTESIAN_POINT('',(18.1342314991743,1.,18.6702925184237));
#1509=CARTESIAN_POINT('',(18.5711135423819,1.,18.0544549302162));
#1510=CARTESIAN_POINT('',(19.3947465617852,1.,16.79007824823));
#1511=CARTESIAN_POINT('',(19.7814882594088,1.,16.1415331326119));
#1512=CARTESIAN_POINT('',(20.5957148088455,1.,14.6493338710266));
#1513=CARTESIAN_POINT('',(21.0087986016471,1.,13.7977905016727));
#1514=CARTESIAN_POINT('',(21.7549869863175,1.,12.0607243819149));
#1515=CARTESIAN_POINT('',(22.0881049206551,1.,11.1752073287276));
#1516=CARTESIAN_POINT('',(22.6747853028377,1.,9.37726562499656));
#1517=CARTESIAN_POINT('',(22.9282718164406,1.,8.46481619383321));
#1518=CARTESIAN_POINT('',(23.3553507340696,1.,6.62178968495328));
#1519=CARTESIAN_POINT('',(23.5289517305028,1.,5.69121456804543));
#1520=CARTESIAN_POINT('',(23.9144236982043,1.,2.99273672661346));
#1521=CARTESIAN_POINT('',(24.0252763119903,1.,1.20940015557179));
#1522=CARTESIAN_POINT('',(23.9650748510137,1.,-2.3506545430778));
#1523=CARTESIAN_POINT('',(23.7942215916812,1.,-4.12737648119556));
#1524=CARTESIAN_POINT('',(23.2079825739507,1.,-7.42083789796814));
#1525=CARTESIAN_POINT('',(22.8243147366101,1.,-8.94324060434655));
#1526=CARTESIAN_POINT('',(21.8378907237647,1.,-11.9151791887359));
#1527=CARTESIAN_POINT('',(21.2352561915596,1.,-13.3647550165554));
#1528=CARTESIAN_POINT('',(19.9093004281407,1.,-15.9609614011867));
#1529=CARTESIAN_POINT('',(19.2140338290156,1.,-17.1218185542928));
#1530=CARTESIAN_POINT('',(18.0519944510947,1.,-18.7785870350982));
#1531=CARTESIAN_POINT('',(17.6447095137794,1.,-19.3168439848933));
#1532=CARTESIAN_POINT('',(16.7910564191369,1.,-20.361309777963));
#1533=CARTESIAN_POINT('',(16.3447026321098,1.,-20.8675302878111));
#1534=CARTESIAN_POINT('',(15.4585326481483,1.,-21.7969452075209));
#1535=CARTESIAN_POINT('',(15.0221821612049,1.,-22.2234483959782));
#1536=CARTESIAN_POINT('',(14.119637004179,1.,-23.0433444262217));
#1537=CARTESIAN_POINT('',(13.6534536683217,1.,-23.4367497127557));
#1538=CARTESIAN_POINT('',(12.6924290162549,1.,-24.1872944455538));
#1539=CARTESIAN_POINT('',(12.1975771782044,1.,-24.5444204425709));
#1540=CARTESIAN_POINT('',(11.1815028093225,1.,-25.2186114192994));
#1541=CARTESIAN_POINT('',(10.6602898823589,1.,-25.5356908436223));
#1542=CARTESIAN_POINT('',(9.59107725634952,1.,-26.1279728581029));
#1543=CARTESIAN_POINT('',(9.04295507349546,1.,-26.4029548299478));
#1544=CARTESIAN_POINT('',(7.92542300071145,1.,-26.9057570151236));
#1545=CARTESIAN_POINT('',(7.35601252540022,1.,-27.1335759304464));
#1546=CARTESIAN_POINT('',(6.19996898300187,1.,-27.5388691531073));
#1547=CARTESIAN_POINT('',(5.6133483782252,1.,-27.7163789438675));
#1548=CARTESIAN_POINT('',(4.42670966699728,1.,-28.0187105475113));
#1549=CARTESIAN_POINT('',(3.82669359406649,1.,-28.1435403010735));
#1550=CARTESIAN_POINT('',(2.72784727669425,1.,-28.3209199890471));
#1551=CARTESIAN_POINT('',(2.23045374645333,1.,-28.3824848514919));
#1552=CARTESIAN_POINT('',(1.23252187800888,1.,-28.4684841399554));
#1553=CARTESIAN_POINT('',(0.731984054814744,1.,-28.4929244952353));
#1554=CARTESIAN_POINT('',(-0.269624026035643,1.,-28.5044221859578));
#1555=CARTESIAN_POINT('',(-0.770694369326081,1.,-28.4914721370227));
#1556=CARTESIAN_POINT('',(-1.77049914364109,1.,-28.4283240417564));
#1557=CARTESIAN_POINT('',(-2.26923331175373,1.,-28.3781218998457));
#1558=CARTESIAN_POINT('',(-3.43843626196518,1.,-28.2165198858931));
#1559=CARTESIAN_POINT('',(-4.10682694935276,1.,-28.0896949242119));
#1560=CARTESIAN_POINT('',(-5.42792205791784,1.,-27.7707621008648));
#1561=CARTESIAN_POINT('',(-6.08062209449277,1.,-27.5786362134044));
#1562=CARTESIAN_POINT('',(-7.36516162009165,1.,-27.1322736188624));
#1563=CARTESIAN_POINT('',(-7.99697818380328,1.,-26.8779710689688));
#1564=CARTESIAN_POINT('',(-9.2340194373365,1.,-26.3115361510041));
#1565=CARTESIAN_POINT('',(-9.83924532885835,1.,-25.9994063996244));
#1566=CARTESIAN_POINT('',(-11.01492050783,1.,-25.3243210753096));
#1567=CARTESIAN_POINT('',(-11.5855841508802,1.,-24.9617377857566));
#1568=CARTESIAN_POINT('',(-12.6935272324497,1.,-24.188868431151));
#1569=CARTESIAN_POINT('',(-13.2308076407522,1.,-23.7785837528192));
#1570=CARTESIAN_POINT('',(-14.2697263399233,1.,-22.9149363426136));
#1571=CARTESIAN_POINT('',(-14.7713551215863,1.,-22.4615621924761));
#1572=CARTESIAN_POINT('',(-15.7370954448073,1.,-21.5164149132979));
#1573=CARTESIAN_POINT('',(-16.2011984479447,1.,-21.0246330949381));
#1574=CARTESIAN_POINT('',(-17.2597113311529,1.,-19.8135481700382));
#1575=CARTESIAN_POINT('',(-17.8365779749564,1.,-19.0788287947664));
#1576=CARTESIAN_POINT('',(-18.9141861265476,1.,-17.5554360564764));
#1577=CARTESIAN_POINT('',(-19.4148979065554,1.,-16.7667417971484));
#1578=CARTESIAN_POINT('',(-20.3396600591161,1.,-15.1441828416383));
#1579=CARTESIAN_POINT('',(-20.7635960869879,1.,-14.3102531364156));
#1580=CARTESIAN_POINT('',(-21.5334073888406,1.,-12.6073312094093));
#1581=CARTESIAN_POINT('',(-21.8792906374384,1.,-11.7383425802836));
#1582=CARTESIAN_POINT('',(-22.4919998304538,1.,-9.9762064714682));
#1583=CARTESIAN_POINT('',(-22.7590819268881,1.,-9.08314780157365));
#1584=CARTESIAN_POINT('',(-23.2159376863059,1.,-7.2771049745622));
#1585=CARTESIAN_POINT('',(-23.4056760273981,1.,-6.36411191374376));
#1586=CARTESIAN_POINT('',(-23.7077085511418,1.,-4.52614832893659));
#1587=CARTESIAN_POINT('',(-23.8200654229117,1.,-3.60118812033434));
#1588=CARTESIAN_POINT('',(-23.9677116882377,1.,-1.74552487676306));
#1589=CARTESIAN_POINT('',(-24.0030155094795,1.,-0.814822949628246));
#1590=CARTESIAN_POINT('',(-23.9939636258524,1.,1.80604068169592));
#1591=CARTESIAN_POINT('',(-23.8611959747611,1.,3.49674706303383));
#1592=CARTESIAN_POINT('',(-23.3411378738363,1.,6.83758288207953));
#1593=CARTESIAN_POINT('',(-22.9539794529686,1.,8.48773290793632));
#1594=CARTESIAN_POINT('',(-21.9927573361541,1.,11.4934847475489));
#1595=CARTESIAN_POINT('',(-21.4502113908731,1.,12.8591655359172));
#1596=CARTESIAN_POINT('',(-20.1734346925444,1.,15.4977303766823));
#1597=CARTESIAN_POINT('',(-19.4393134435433,1.,16.7706669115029));
#1598=CARTESIAN_POINT('',(-17.8908853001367,1.,19.0290971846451));
#1599=CARTESIAN_POINT('',(-17.0997840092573,1.,20.030383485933));
#1600=CARTESIAN_POINT('',(-15.8111834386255,1.,21.4380101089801));
#1601=CARTESIAN_POINT('',(-15.3645608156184,1.,21.8915815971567));
#1602=CARTESIAN_POINT('',(-14.438418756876,1.,22.763675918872));
#1603=CARTESIAN_POINT('',(-13.9589115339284,1.,23.182211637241));
#1604=CARTESIAN_POINT('',(-13.0137533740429,1.,23.943972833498));
#1605=CARTESIAN_POINT('',(-12.550828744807,1.,24.290585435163));
#1606=CARTESIAN_POINT('',(-11.6008118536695,1.,24.9486285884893));
#1607=CARTESIAN_POINT('',(-11.1137287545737,1.,25.2600723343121));
#1608=CARTESIAN_POINT('',(-10.1172262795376,1.,25.8449357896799));
#1609=CARTESIAN_POINT('',(-9.60780749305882,1.,26.1183565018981));
#1610=CARTESIAN_POINT('',(-8.56901307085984,1.,26.6243217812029));
#1611=CARTESIAN_POINT('',(-8.03963724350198,1.,26.8568659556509));
#1612=CARTESIAN_POINT('',(-6.9658636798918,1.,27.2776006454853));
#1613=CARTESIAN_POINT('',(-6.42153165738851,1.,27.4659585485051));
#1614=CARTESIAN_POINT('',(-5.31918481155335,1.,27.7971584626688));
#1615=CARTESIAN_POINT('',(-4.76117045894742,1.,27.9400020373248));
#1616=CARTESIAN_POINT('',(-3.63504755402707,1.,28.178332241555));
#1617=CARTESIAN_POINT('',(-3.0669382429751,1.,28.2738152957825));
#1618=CARTESIAN_POINT('',(-1.9246088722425,1.,28.4161196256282));
#1619=CARTESIAN_POINT('',(-1.35038823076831,1.,28.4629362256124));
#1620=CARTESIAN_POINT('',(-0.77517688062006,1.,28.4850802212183));
#1621=B_SPLINE_CURVE_WITH_KNOTS('',3,(#1487,#1488,#1489,#1490,#1491,#1492,#1493,#1494,#1495,
#1496,#1497,#1498,#1499,#1500,#1501,#1502,#1503,#1504,#1505,#1506,#1507,#1508,#1509,#1510,#1511,
#1512,#1513,#1514,#1515,#1516,#1517,#1518,#1519,#1520,#1521,#1522,#1523,#1524,#1525,#1526,#1527,
#1528,#1529,#1530,#1531,#1532,#1533,#1534,#1535,#1536,#1537,#1538,#1539,#1540,#1541,#1542,#1543,
#1544,#1545,#1546,#1547,#1548,#1549,#1550,#1551,#1552,#1553,#1554,#1555,#1556,#1557,#1558,#1559,
#1560,#1561,#1562,#1563,#1564,#1565,#1566,#1567,#1568,#1569,#1570,#1571,#1572,#1573,#1574,#1575,
#1576,#1577,#1578,#1579,#1580,#1581,#1582,#1583,#1584,#1585,#1586,#1587,#1588,#1589,#1590,#1591,
#1592,#1593,#1594,#1595,#1596,#1597,#1598,#1599,#1600,#1601,#1602,#1603,#1604,#1605,#1606,#1607,
#1608,#1609,#1610,#1611,#1612,#1613,#1614,#1615,#1616,#1617,#1618,#1619,#1620),.UNSPECIFIED.,
.T.,.F.,(4,2,2,2,2,2,2,2,2,2,2,2,2,2,2,2,2,2,2,2,2,2,2,2,2,2,2,2,2,2,2,2,2,2,2,2,2,2,2,2,2,2,2,
2,2,2,2,2,2,2,2,2,2,2,2,2,2,2,2,2,2,2,2,2,2,2,4),(0.,1.94355755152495,3.887261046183,
5.83229682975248,7.77753700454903,10.0564181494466,12.335793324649,14.6164653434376,
16.8984768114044,19.160466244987,21.42363366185,23.6863334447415,25.949451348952,
28.784467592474,31.619010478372,34.4562481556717,37.2931805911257,42.6293644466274,
47.9617460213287,52.655853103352,57.3473564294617,61.3926868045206,63.4160619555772,
65.4386959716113,67.2676759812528,69.0959651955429,70.9249297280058,72.7532326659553,
74.5908112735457,76.4284404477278,78.2647702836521,80.1008232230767,81.6030656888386,
83.1050682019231,84.6073673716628,86.1098317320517,88.14723930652,90.1852097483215,
92.2253477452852,94.2653934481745,96.2911141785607,98.3167760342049,100.342976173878,
102.369636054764,105.166821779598,107.965096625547,110.767505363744,113.569627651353,
116.362538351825,119.156723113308,121.948641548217,124.740037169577,129.807228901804,
134.871792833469,139.266076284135,143.657853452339,147.472649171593,149.38079611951,
151.288238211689,153.021676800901,154.754462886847,156.487203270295,158.219960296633,
159.9460432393,161.672066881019,163.398220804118,165.124540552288),.UNSPECIFIED.);
#1622=CARTESIAN_POINT('',(-0.77517688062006,1.,28.4850802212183));
#1623=VERTEX_POINT('',#1622);
#1624=EDGE_CURVE('E62',#1623,#1623,#1621,.T.);
#1625=ORIENTED_EDGE('',*,*,#1624,.T.);
#1626=EDGE_LOOP('',(#1625));
#1627=FACE_BOUND('',#1626,.T.);
#1628=CARTESIAN_POINT('',(-15.25,1.,0.));
#1629=DIRECTION('',(0.,1.,0.));
#1630=DIRECTION('',(0.,0.,1.));
#1631=AXIS2_PLACEMENT_3D('',#1628,#1629,#1630);
#1632=CIRCLE('',#1631,5.25);
#1633=CARTESIAN_POINT('',(-15.25,1.,-5.25));
#1634=VERTEX_POINT('',#1633);
#1635=CARTESIAN_POINT('',(-15.25,1.,5.25));
#1636=VERTEX_POINT('',#1635);
#1637=EDGE_CURVE('E138',#1634,#1636,#1632,.T.);
#1638=ORIENTED_EDGE('',*,*,#1637,.F.);
#1639=DIRECTION('',(1.,0.,0.));
#1640=VECTOR('',#1639,1.);
#1641=CARTESIAN_POINT('',(-15.25,1.,-5.25));
#1642=LINE('',#1641,#1640);
#1643=CARTESIAN_POINT('',(15.25,1.,-5.25));
#1644=VERTEX_POINT('',#1643);
#1645=EDGE_CURVE('E173',#1634,#1644,#1642,.T.);
#1646=ORIENTED_EDGE('',*,*,#1645,.T.);
#1647=CARTESIAN_POINT('',(15.25,1.,0.));
#1648=DIRECTION('',(0.,1.,0.));
#1649=DIRECTION('',(0.,0.,1.));
#1650=AXIS2_PLACEMENT_3D('',#1647,#1648,#1649);
#1651=CIRCLE('',#1650,5.25);
#1652=CARTESIAN_POINT('',(15.25,1.,5.25));
#1653=VERTEX_POINT('',#1652);
#1654=EDGE_CURVE('E171',#1644,#1653,#1651,.F.);
#1655=ORIENTED_EDGE('',*,*,#1654,.T.);
#1656=DIRECTION('',(1.,0.,0.));
#1657=VECTOR('',#1656,1.);
#1658=CARTESIAN_POINT('',(-15.25,1.,5.25));
#1659=LINE('',#1658,#1657);
#1660=EDGE_CURVE('E169',#1636,#1653,#1659,.T.);
#1661=ORIENTED_EDGE('',*,*,#1660,.F.);
#1662=EDGE_LOOP('',(#1638,#1646,#1655,#1661));
#1663=FACE_BOUND('',#1662,.T.);
#1664=ADVANCED_FACE('F179',(#1627,#1663),#1083,.T.);
#1665=CARTESIAN_POINT('',(0.,11.,0.));
#1666=DIRECTION('',(0.,1.,0.));
#1667=DIRECTION('',(0.,0.,-1.));
#1668=AXIS2_PLACEMENT_3D('',#1665,#1666,#1667);
#1669=ELLIPSE('',#1668,31.5,27.);
#1670=DIRECTION('',(0.,-1.,0.));
#1671=VECTOR('',#1670,1.);
#1672=SURFACE_OF_LINEAR_EXTRUSION('',#1669,#1671);
#1673=OFFSET_SURFACE('',#1672,1.,.F.);
#1674=CARTESIAN_POINT('',(-0.852127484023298,3.,30.4835993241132));
#1675=CARTESIAN_POINT('',(-1.48441312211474,3.,30.4592585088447));
#1676=CARTESIAN_POINT('',(-2.11552294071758,3.,30.4077956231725));
#1677=CARTESIAN_POINT('',(-3.37048370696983,3.,30.2514603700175));
#1678=CARTESIAN_POINT('',(-3.99433534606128,3.,30.1465931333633));
#1679=CARTESIAN_POINT('',(-5.23009165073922,3.,29.885060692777));
#1680=CARTESIAN_POINT('',(-5.84199721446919,3.,29.7283993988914));
#1681=CARTESIAN_POINT('',(-7.04969616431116,3.,29.3655467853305));
#1682=CARTESIAN_POINT('',(-7.64548899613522,3.,29.1593537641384));
#1683=CARTESIAN_POINT('',(-8.81949779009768,3.,28.6993444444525));
#1684=CARTESIAN_POINT('',(-9.39763688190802,3.,28.4453470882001));
#1685=CARTESIAN_POINT('',(-10.5307464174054,3.,27.8934440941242));
#1686=CARTESIAN_POINT('',(-11.0857170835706,3.,27.5955388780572));
#1687=CARTESIAN_POINT('',(-12.1699389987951,3.,26.9591917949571));
#1688=CARTESIAN_POINT('',(-12.6991895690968,3.,26.6207488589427));
#1689=CARTESIAN_POINT('',(-13.7301084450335,3.,25.9066678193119));
#1690=CARTESIAN_POINT('',(-14.2317662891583,3.,25.5310157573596));
#1691=CARTESIAN_POINT('',(-15.2546879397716,3.,24.7065809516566));
#1692=CARTESIAN_POINT('',(-15.7728649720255,3.,24.2542424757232));
#1693=CARTESIAN_POINT('',(-16.7723361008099,3.,23.3130969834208));
#1694=CARTESIAN_POINT('',(-17.2536164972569,3.,22.8242765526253));
#1695=CARTESIAN_POINT('',(-18.6404370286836,3.,21.3093664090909));
#1696=CARTESIAN_POINT('',(-19.4893788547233,3.,20.2344823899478));
#1697=CARTESIAN_POINT('',(-21.1476564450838,3.,17.8158425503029));
#1698=CARTESIAN_POINT('',(-21.9315814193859,3.,16.4560094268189));
#1699=CARTESIAN_POINT('',(-23.2927075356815,3.,13.6431180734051));
#1700=CARTESIAN_POINT('',(-23.8697904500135,3.,12.1900070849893));
#1701=CARTESIAN_POINT('',(-24.891136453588,3.,8.99626356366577));
#1702=CARTESIAN_POINT('',(-25.3017130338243,3.,7.24558330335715));
#1703=CARTESIAN_POINT('',(-25.8530212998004,3.,3.70399488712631));
#1704=CARTESIAN_POINT('',(-25.9936128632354,3.,1.91306632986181));
#1705=CARTESIAN_POINT('',(-26.0031903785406,3.,-0.863109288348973));
#1706=CARTESIAN_POINT('',(-25.9658018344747,3.,-1.84895501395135));
#1707=CARTESIAN_POINT('',(-25.8093757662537,3.,-3.81499186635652));
#1708=CARTESIAN_POINT('',(-25.6903229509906,3.,-4.79518189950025));
#1709=CARTESIAN_POINT('',(-25.3701131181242,3.,-6.74375741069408));
#1710=CARTESIAN_POINT('',(-25.1688895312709,3.,-7.71213266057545));
#1711=CARTESIAN_POINT('',(-24.6839927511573,3.,-9.62902842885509));
#1712=CARTESIAN_POINT('',(-24.4003571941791,3.,-10.5775577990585));
#1713=CARTESIAN_POINT('',(-23.7489948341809,3.,-12.4508599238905));
#1714=CARTESIAN_POINT('',(-23.380993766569,3.,-13.3755440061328));
#1715=CARTESIAN_POINT('',(-22.560890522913,3.,-15.1897186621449));
#1716=CARTESIAN_POINT('',(-22.1087797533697,3.,-16.0792056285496));
#1717=CARTESIAN_POINT('',(-21.1210199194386,3.,-17.8122984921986));
#1718=CARTESIAN_POINT('',(-20.5854950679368,3.,-18.6559701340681));
#1719=CARTESIAN_POINT('',(-19.4308784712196,3.,-20.2882286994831));
#1720=CARTESIAN_POINT('',(-18.8118193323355,3.,-21.0768369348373));
#1721=CARTESIAN_POINT('',(-17.6735773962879,3.,-22.3791400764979));
#1722=CARTESIAN_POINT('',(-17.1738568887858,3.,-22.9087236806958));
#1723=CARTESIAN_POINT('',(-16.1323991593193,3.,-23.9279742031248));
#1724=CARTESIAN_POINT('',(-15.5906714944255,3.,-24.4176501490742));
#1725=CARTESIAN_POINT('',(-14.4669080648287,3.,-25.3518279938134));
#1726=CARTESIAN_POINT('',(-13.8848830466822,3.,-25.7963418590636));
#1727=CARTESIAN_POINT('',(-12.6827326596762,3.,-26.6349270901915));
#1728=CARTESIAN_POINT('',(-12.0626061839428,3.,-27.0289969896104));
#1729=CARTESIAN_POINT('',(-10.783025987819,3.,-27.7637450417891));
#1730=CARTESIAN_POINT('',(-10.1233251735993,3.,-28.1040259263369));
#1731=CARTESIAN_POINT('',(-8.77298140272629,3.,-28.7223406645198));
#1732=CARTESIAN_POINT('',(-8.08233704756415,3.,-29.0003717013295));
#1733=CARTESIAN_POINT('',(-6.67645318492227,3.,-29.4888994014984));
#1734=CARTESIAN_POINT('',(-5.96124058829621,3.,-29.6994675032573));
#1735=CARTESIAN_POINT('',(-4.51225347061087,3.,-30.049274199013));
#1736=CARTESIAN_POINT('',(-3.77848413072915,3.,-30.1885324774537));
#1737=CARTESIAN_POINT('',(-2.49418411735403,3.,-30.3660438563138));
#1738=CARTESIAN_POINT('',(-1.94612685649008,3.,-30.4212167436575));
#1739=CARTESIAN_POINT('',(-0.847230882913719,3.,-30.4906231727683));
#1740=CARTESIAN_POINT('',(-0.296392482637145,3.,-30.5048612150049));
#1741=CARTESIAN_POINT('',(0.804659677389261,3.,-30.4922220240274));
#1742=CARTESIAN_POINT('',(1.35487353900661,3.,-30.4653529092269));
#1743=CARTESIAN_POINT('',(2.45155714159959,3.,-30.3708436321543));
#1744=CARTESIAN_POINT('',(2.99802627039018,3.,-30.3031969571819));
#1745=CARTESIAN_POINT('',(4.20471419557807,3.,-30.1084085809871));
#1746=CARTESIAN_POINT('',(4.86322638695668,3.,-29.9713867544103));
#1747=CARTESIAN_POINT('',(6.16442847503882,3.,-29.6398674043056));
#1748=CARTESIAN_POINT('',(6.8071159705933,3.,-29.4453612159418));
#1749=CARTESIAN_POINT('',(8.0722777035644,3.,-29.0018130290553));
#1750=CARTESIAN_POINT('',(8.69473731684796,3.,-28.7527325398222));
#1751=CARTESIAN_POINT('',(9.91486759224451,3.,-28.2037696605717));
#1752=CARTESIAN_POINT('',(10.5125389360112,3.,-27.9038886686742));
#1753=CARTESIAN_POINT('',(11.6768482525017,3.,-27.2589289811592));
#1754=CARTESIAN_POINT('',(12.2436276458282,3.,-26.9140860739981));
#1755=CARTESIAN_POINT('',(13.3470190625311,3.,-26.1819583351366));
#1756=CARTESIAN_POINT('',(13.8836200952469,3.,-25.794658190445));
#1757=CARTESIAN_POINT('',(14.9243041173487,3.,-24.981901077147));
#1758=CARTESIAN_POINT('',(15.4283990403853,3.,-24.5564582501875));
#1759=CARTESIAN_POINT('',(16.4030550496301,3.,-23.6710547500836));
#1760=CARTESIAN_POINT('',(16.8736033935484,3.,-23.2110810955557));
#1761=CARTESIAN_POINT('',(17.8280299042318,3.,-22.2100796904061));
#1762=CARTESIAN_POINT('',(18.3080442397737,3.,-21.6656265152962));
#1763=CARTESIAN_POINT('',(19.2249068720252,3.,-20.543820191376));
#1764=CARTESIAN_POINT('',(19.6617392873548,3.,-19.9664550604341));
#1765=CARTESIAN_POINT('',(20.9066563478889,3.,-18.1915365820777));
#1766=CARTESIAN_POINT('',(21.6495131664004,3.,-16.9507853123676));
#1767=CARTESIAN_POINT('',(23.0639150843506,3.,-14.1814101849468));
#1768=CARTESIAN_POINT('',(23.7051156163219,3.,-12.6384608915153));
#1769=CARTESIAN_POINT('',(24.7534588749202,3.,-9.47995182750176));
#1770=CARTESIAN_POINT('',(25.1604715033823,3.,-7.86435223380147));
#1771=CARTESIAN_POINT('',(25.7820877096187,3.,-4.37217195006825));
#1772=CARTESIAN_POINT('',(25.9630035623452,3.,-2.48997524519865));
#1773=CARTESIAN_POINT('',(26.0267757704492,3.,1.28108716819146));
#1774=CARTESIAN_POINT('',(25.9094195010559,3.,3.16995667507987));
#1775=CARTESIAN_POINT('',(25.5008212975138,3.,6.03023401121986));
#1776=CARTESIAN_POINT('',(25.3167636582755,3.,7.01700030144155));
#1777=CARTESIAN_POINT('',(24.8636129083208,3.,8.97254972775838));
#1778=CARTESIAN_POINT('',(24.5945106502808,3.,9.94133091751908));
#1779=CARTESIAN_POINT('',(23.9710636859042,3.,11.8519456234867));
#1780=CARTESIAN_POINT('',(23.6168001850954,3.,12.793803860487));
#1781=CARTESIAN_POINT('',(22.8222425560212,3.,14.6434715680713));
#1782=CARTESIAN_POINT('',(22.3819340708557,3.,15.5512753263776));
#1783=CARTESIAN_POINT('',(21.5127172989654,3.,17.1442502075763));
#1784=CARTESIAN_POINT('',(21.0994270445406,3.,17.8373904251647));
#1785=CARTESIAN_POINT('',(20.2180515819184,3.,19.1904094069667));
#1786=CARTESIAN_POINT('',(19.749976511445,3.,19.8502942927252));
#1787=CARTESIAN_POINT('',(18.7593206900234,3.,21.1311634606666));
#1788=CARTESIAN_POINT('',(18.2367286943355,3.,21.7521396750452));
#1789=CARTESIAN_POINT('',(17.1383629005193,3.,22.9483024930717));
#1790=CARTESIAN_POINT('',(16.56261692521,3.,23.5235127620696));
#1791=CARTESIAN_POINT('',(15.3540947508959,3.,24.626383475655));
#1792=CARTESIAN_POINT('',(14.7208588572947,3.,25.1535779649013));
#1793=CARTESIAN_POINT('',(13.4049605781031,3.,26.1466892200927));
#1794=CARTESIAN_POINT('',(12.7223274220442,3.,26.612641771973));
#1795=CARTESIAN_POINT('',(11.3118783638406,3.,27.4755071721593));
#1796=CARTESIAN_POINT('',(10.5840883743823,3.,27.872459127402));
#1797=CARTESIAN_POINT('',(9.08881917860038,3.,28.589834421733));
#1798=CARTESIAN_POINT('',(8.32134860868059,3.,28.9102743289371));
#1799=CARTESIAN_POINT('',(6.86907257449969,3.,29.4267795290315));
#1800=CARTESIAN_POINT('',(6.18861490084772,3.,29.6341854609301));
#1801=CARTESIAN_POINT('',(4.80994534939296,3.,29.984471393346));
#1802=CARTESIAN_POINT('',(4.111735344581,3.,30.1273581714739));
#1803=CARTESIAN_POINT('',(2.70448121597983,3.,30.3458195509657));
#1804=CARTESIAN_POINT('',(1.99544484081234,3.,30.4214401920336));
#1805=CARTESIAN_POINT('',(0.57306614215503,3.,30.5040294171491));
#1806=CARTESIAN_POINT('',(-0.140275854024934,3.,30.5110031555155));
#1807=CARTESIAN_POINT('',(-0.852127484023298,3.,30.4835993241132));
#1808=B_SPLINE_CURVE_WITH_KNOTS('',3,(#1674,#1675,#1676,#1677,#1678,#1679,#1680,#1681,#1682,
#1683,#1684,#1685,#1686,#1687,#1688,#1689,#1690,#1691,#1692,#1693,#1694,#1695,#1696,#1697,#1698,
#1699,#1700,#1701,#1702,#1703,#1704,#1705,#1706,#1707,#1708,#1709,#1710,#1711,#1712,#1713,#1714,
#1715,#1716,#1717,#1718,#1719,#1720,#1721,#1722,#1723,#1724,#1725,#1726,#1727,#1728,#1729,#1730,
#1731,#1732,#1733,#1734,#1735,#1736,#1737,#1738,#1739,#1740,#1741,#1742,#1743,#1744,#1745,#1746,
#1747,#1748,#1749,#1750,#1751,#1752,#1753,#1754,#1755,#1756,#1757,#1758,#1759,#1760,#1761,#1762,
#1763,#1764,#1765,#1766,#1767,#1768,#1769,#1770,#1771,#1772,#1773,#1774,#1775,#1776,#1777,#1778,
#1779,#1780,#1781,#1782,#1783,#1784,#1785,#1786,#1787,#1788,#1789,#1790,#1791,#1792,#1793,#1794,
#1795,#1796,#1797,#1798,#1799,#1800,#1801,#1802,#1803,#1804,#1805,#1806,#1807),.UNSPECIFIED.,
.T.,.F.,(4,2,2,2,2,2,2,2,2,2,2,2,2,2,2,2,2,2,2,2,2,2,2,2,2,2,2,2,2,2,2,2,2,2,2,2,2,2,2,2,2,2,2,
2,2,2,2,2,2,2,2,2,2,2,2,2,2,2,2,2,2,2,2,2,2,2,4),(0.,1.72631974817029,3.45247367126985,
5.17849731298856,6.90458025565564,8.63733728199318,10.3700776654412,12.1028637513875,
13.8363023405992,15.7437444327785,17.6518913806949,21.4666870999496,25.8584642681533,
30.2527477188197,35.317311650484,40.3845033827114,43.1758990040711,45.9678174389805,
48.7620022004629,51.5549129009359,54.3570351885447,57.1594439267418,59.9577187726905,
62.7549044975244,64.78156437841,66.8077645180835,68.8334263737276,70.8591471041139,
72.8991928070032,74.9393308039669,76.9773012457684,79.0147088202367,80.5171731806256,
82.0194723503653,83.5214748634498,85.0237173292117,86.8597702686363,88.6961001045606,
90.5337292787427,92.3713078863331,94.1996108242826,96.0285753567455,97.8568645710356,
99.6858445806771,101.708478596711,103.731853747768,107.777184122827,112.468687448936,
117.16279453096,122.495176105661,127.831359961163,130.668292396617,133.505530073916,
136.340072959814,139.175089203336,141.438207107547,143.700906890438,145.964074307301,
148.226063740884,150.508075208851,152.788747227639,155.068122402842,157.347003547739,
159.292243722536,161.237279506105,163.180983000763,165.124540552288),.UNSPECIFIED.);
#1809=CARTESIAN_POINT('',(-0.852127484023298,3.,30.4835993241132));
#1810=VERTEX_POINT('',#1809);
#1811=EDGE_CURVE('E12',#1810,#1810,#1808,.T.);
#1812=ORIENTED_EDGE('',*,*,#1811,.T.);
#1813=EDGE_LOOP('',(#1812));
#1814=FACE_BOUND('',#1813,.T.);
#1815=ORIENTED_EDGE('',*,*,#202,.T.);
#1816=EDGE_LOOP('',(#1815));
#1817=FACE_BOUND('',#1816,.T.);
#1818=ADVANCED_FACE('F156',(#1814,#1817),#1673,.T.);
#1819=CARTESIAN_POINT('',(-15.25,11.,0.));
#1820=DIRECTION('',(0.,-1.,0.));
#1821=DIRECTION('',(0.,0.,-1.));
#1822=AXIS2_PLACEMENT_3D('',#1819,#1820,#1821);
#1823=CYLINDRICAL_SURFACE('',#1822,5.25);
#1824=DIRECTION('',(0.,-1.,0.));
#1825=VECTOR('',#1824,1.);
#1826=CARTESIAN_POINT('',(-15.25,11.,5.25));
#1827=LINE('',#1826,#1825);
#1828=CARTESIAN_POINT('',(-15.25,1.06856936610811,5.25));
#1829=VERTEX_POINT('',#1828);
#1830=EDGE_CURVE('E131',#1829,#1636,#1827,.T.);
#1831=ORIENTED_EDGE('',*,*,#1830,.F.);
#1832=CARTESIAN_POINT('',(-15.25,1.06856936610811,0.));
#1833=DIRECTION('',(0.,-1.,0.));
#1834=DIRECTION('',(0.,0.,-1.));
#1835=AXIS2_PLACEMENT_3D('',#1832,#1833,#1834);
#1836=CIRCLE('',#1835,5.25);
#1837=CARTESIAN_POINT('',(-15.25,1.06856936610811,-5.25));
#1838=VERTEX_POINT('',#1837);
#1839=EDGE_CURVE('E117',#1829,#1838,#1836,.T.);
#1840=ORIENTED_EDGE('',*,*,#1839,.T.);
#1841=DIRECTION('',(0.,1.,0.));
#1842=VECTOR('',#1841,1.);
#1843=CARTESIAN_POINT('',(-15.25,11.,-5.25));
#1844=LINE('',#1843,#1842);
#1845=EDGE_CURVE('E147',#1838,#1634,#1844,.F.);
#1846=ORIENTED_EDGE('',*,*,#1845,.T.);
#1847=ORIENTED_EDGE('',*,*,#1637,.T.);
#1848=EDGE_LOOP('',(#1831,#1840,#1846,#1847));
#1849=FACE_BOUND('',#1848,.T.);
#1850=ADVANCED_FACE('F136',(#1849),#1823,.T.);
#1851=CARTESIAN_POINT('',(-15.25,11.,5.25));
#1852=DIRECTION('',(0.,0.,-1.));
#1853=DIRECTION('',(-1.,0.,0.));
#1854=AXIS2_PLACEMENT_3D('',#1851,#1852,#1853);
#1855=PLANE('',#1854);
#1856=DIRECTION('',(0.,1.,0.));
#1857=VECTOR('',#1856,1.);
#1858=CARTESIAN_POINT('',(15.25,11.,5.25));
#1859=LINE('',#1858,#1857);
#1860=CARTESIAN_POINT('',(15.25,1.06856936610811,5.25));
#1861=VERTEX_POINT('',#1860);
#1862=EDGE_CURVE('E133',#1861,#1653,#1859,.F.);
#1863=ORIENTED_EDGE('',*,*,#1862,.F.);
#1864=DIRECTION('',(1.,0.,0.));
#1865=VECTOR('',#1864,1.);
#1866=CARTESIAN_POINT('',(-20.584255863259,1.06856936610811,5.25));
#1867=LINE('',#1866,#1865);
#1868=EDGE_CURVE('E120',#1829,#1861,#1867,.T.);
#1869=ORIENTED_EDGE('',*,*,#1868,.F.);
#1870=ORIENTED_EDGE('',*,*,#1830,.T.);
#1871=ORIENTED_EDGE('',*,*,#1660,.T.);
#1872=EDGE_LOOP('',(#1863,#1869,#1870,#1871));
#1873=FACE_BOUND('',#1872,.T.);
#1874=ADVANCED_FACE('F129',(#1873),#1855,.F.);
#1875=CARTESIAN_POINT('',(15.25,11.,0.));
#1876=DIRECTION('',(0.,-1.,0.));
#1877=DIRECTION('',(0.,0.,-1.));
#1878=AXIS2_PLACEMENT_3D('',#1875,#1876,#1877);
#1879=CYLINDRICAL_SURFACE('',#1878,5.25);
#1880=CARTESIAN_POINT('',(15.25,1.06856936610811,0.));
#1881=DIRECTION('',(0.,-1.,0.));
#1882=DIRECTION('',(0.,0.,-1.));
#1883=AXIS2_PLACEMENT_3D('',#1880,#1881,#1882);
#1884=CIRCLE('',#1883,5.25);
#1885=CARTESIAN_POINT('',(15.25,1.06856936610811,-5.25));
#1886=VERTEX_POINT('',#1885);
#1887=EDGE_CURVE('E77',#1861,#1886,#1884,.F.);
#1888=ORIENTED_EDGE('',*,*,#1887,.F.);
#1889=ORIENTED_EDGE('',*,*,#1862,.T.);
#1890=ORIENTED_EDGE('',*,*,#1654,.F.);
#1891=DIRECTION('',(0.,-1.,0.));
#1892=VECTOR('',#1891,1.);
#1893=CARTESIAN_POINT('',(15.25,11.,-5.25));
#1894=LINE('',#1893,#1892);
#1895=EDGE_CURVE('E144',#1886,#1644,#1894,.T.);
#1896=ORIENTED_EDGE('',*,*,#1895,.F.);
#1897=EDGE_LOOP('',(#1888,#1889,#1890,#1896));
#1898=FACE_BOUND('',#1897,.T.);
#1899=ADVANCED_FACE('F183',(#1898),#1879,.T.);
#1900=CARTESIAN_POINT('',(-15.25,11.,-5.25));
#1901=DIRECTION('',(0.,0.,-1.));
#1902=DIRECTION('',(-1.,0.,0.));
#1903=AXIS2_PLACEMENT_3D('',#1900,#1901,#1902);
#1904=PLANE('',#1903);
#1905=DIRECTION('',(-1.,0.,0.));
#1906=VECTOR('',#1905,1.);
#1907=CARTESIAN_POINT('',(-15.25,1.06856936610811,-5.25));
#1908=LINE('',#1907,#1906);
#1909=EDGE_CURVE('E121',#1886,#1838,#1908,.T.);
#1910=ORIENTED_EDGE('',*,*,#1909,.F.);
#1911=ORIENTED_EDGE('',*,*,#1895,.T.);
#1912=ORIENTED_EDGE('',*,*,#1645,.F.);
#1913=ORIENTED_EDGE('',*,*,#1845,.F.);
#1914=EDGE_LOOP('',(#1910,#1911,#1912,#1913));
#1915=FACE_BOUND('',#1914,.T.);
#1916=ADVANCED_FACE('F180',(#1915),#1904,.T.);
#1917=CARTESIAN_POINT('',(3.32786790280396,3.,-28.2237790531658));
#1918=DIRECTION('',(0.986371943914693,0.,0.164530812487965));
#1919=DIRECTION('',(0.,-1.,0.));
#1920=AXIS2_PLACEMENT_3D('',#1917,#1918,#1919);
#1921=CIRCLE('',#1920,3.);
#1922=EDGE_CURVE('',#783,#972,#1921,.T.);
#1923=ORIENTED_EDGE('',*,*,#784,.F.);
#1924=ORIENTED_EDGE('',*,*,#973,.F.);
#1925=ORIENTED_EDGE('',*,*,#1922,.T.);
#1926=ORIENTED_EDGE('',*,*,#1922,.F.);
#1927=EDGE_LOOP('',(#1923,#1925,#1924,#1926));
#1928=FACE_BOUND('',#1927,.T.);
#1929=ADVANCED_FACE('F234',(#1928),#638,.T.);
#1930=CARTESIAN_POINT('',(-20.584255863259,1.06856936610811,-6.75));
#1931=DIRECTION('',(0.,-1.,0.));
#1932=DIRECTION('',(0.,0.,-1.));
#1933=AXIS2_PLACEMENT_3D('',#1930,#1931,#1932);
#1934=PLANE('',#1933);
#1935=ORIENTED_EDGE('',*,*,#995,.T.);
#1936=ORIENTED_EDGE('',*,*,#1072,.F.);
#1937=ORIENTED_EDGE('',*,*,#1050,.F.);
#1938=ORIENTED_EDGE('',*,*,#1024,.T.);
#1939=EDGE_LOOP('',(#1935,#1936,#1937,#1938));
#1940=FACE_BOUND('',#1939,.T.);
#1941=ORIENTED_EDGE('',*,*,#1868,.T.);
#1942=ORIENTED_EDGE('',*,*,#1887,.T.);
#1943=ORIENTED_EDGE('',*,*,#1909,.T.);
#1944=ORIENTED_EDGE('',*,*,#1839,.F.);
#1945=EDGE_LOOP('',(#1941,#1942,#1943,#1944));
#1946=FACE_BOUND('',#1945,.T.);
#1947=ADVANCED_FACE('F119',(#1940,#1946),#1934,.F.);
#1948=CARTESIAN_POINT('',(-0.77517688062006,3.,28.4850802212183));
#1949=DIRECTION('',(0.999259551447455,0.,0.0384753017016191));
#1950=DIRECTION('',(-0.0384753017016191,0.,0.999259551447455));
#1951=AXIS2_PLACEMENT_3D('',#1948,#1949,#1950);
#1952=CIRCLE('',#1951,2.);
#1953=EDGE_CURVE('',#1810,#1623,#1952,.T.);
#1954=ORIENTED_EDGE('',*,*,#1811,.F.);
#1955=ORIENTED_EDGE('',*,*,#1624,.F.);
#1956=ORIENTED_EDGE('',*,*,#1953,.T.);
#1957=ORIENTED_EDGE('',*,*,#1953,.F.);
#1958=EDGE_LOOP('',(#1954,#1956,#1955,#1957));
#1959=FACE_BOUND('',#1958,.T.);
#1960=ADVANCED_FACE('F265',(#1959),#1486,.F.);
#1961=CLOSED_SHELL('',(#206,#824,#980,#1012,#1036,#1061,#1078,#1664,#1818,#1850,#1874,#1899,
#1916,#1929,#1947,#1960));
#1962=MANIFOLD_SOLID_BREP('B2',#1961);
#1963=ADVANCED_BREP_SHAPE_REPRESENTATION('',(#18,#1962),#14);
#1964=SHAPE_DEFINITION_REPRESENTATION(#9,#1963);
ENDSEC;
END-ISO-10303-21;
